VERSION 5.8 ;
BUSBITCHARS "[]" ;
DIVIDERCHAR "/" ;
UNITS
    DATABASE MICRONS 1000 ;
END UNITS

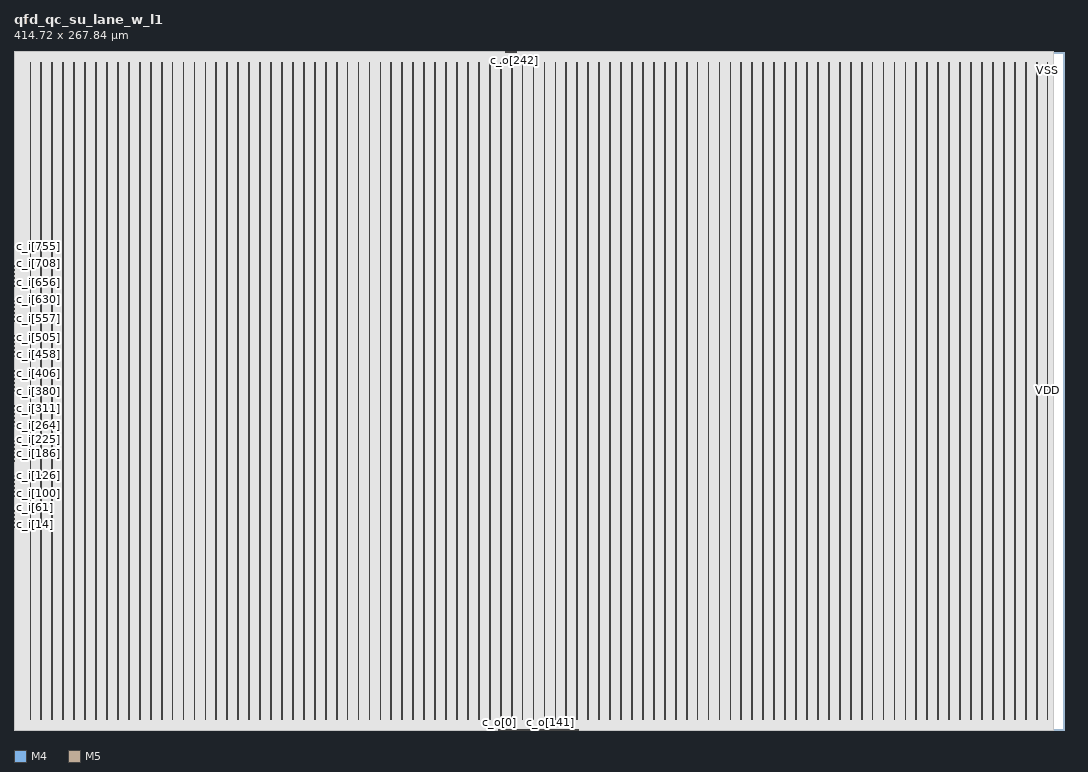
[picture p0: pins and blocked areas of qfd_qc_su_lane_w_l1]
MACRO qfd_qc_su_lane_w_l1
  FOREIGN qfd_qc_su_lane_w_l1 0 0 ;
  CLASS BLOCK ;
  SIZE 414.72 BY 267.84 ;
  PIN c_i[0]
    DIRECTION INPUT ;
    USE SIGNAL ;
    PORT
      LAYER M4 ;
        RECT  0 79.152 0.084 79.176 ;
    END
  END c_i[0]
  PIN c_i[100]
    DIRECTION INPUT ;
    USE SIGNAL ;
    PORT
      LAYER M4 ;
        RECT  0 93.552 0.084 93.576 ;
    END
  END c_i[100]
  PIN c_i[101]
    DIRECTION INPUT ;
    USE SIGNAL ;
    PORT
      LAYER M4 ;
        RECT  0 93.696 0.084 93.72 ;
    END
  END c_i[101]
  PIN c_i[102]
    DIRECTION INPUT ;
    USE SIGNAL ;
    PORT
      LAYER M4 ;
        RECT  0 93.84 0.084 93.864 ;
    END
  END c_i[102]
  PIN c_i[103]
    DIRECTION INPUT ;
    USE SIGNAL ;
    PORT
      LAYER M4 ;
        RECT  0 93.984 0.084 94.008 ;
    END
  END c_i[103]
  PIN c_i[104]
    DIRECTION INPUT ;
    USE SIGNAL ;
    PORT
      LAYER M4 ;
        RECT  0 94.128 0.084 94.152 ;
    END
  END c_i[104]
  PIN c_i[105]
    DIRECTION INPUT ;
    USE SIGNAL ;
    PORT
      LAYER M4 ;
        RECT  0 94.272 0.084 94.296 ;
    END
  END c_i[105]
  PIN c_i[106]
    DIRECTION INPUT ;
    USE SIGNAL ;
    PORT
      LAYER M4 ;
        RECT  0 94.416 0.084 94.44 ;
    END
  END c_i[106]
  PIN c_i[107]
    DIRECTION INPUT ;
    USE SIGNAL ;
    PORT
      LAYER M4 ;
        RECT  0 94.56 0.084 94.584 ;
    END
  END c_i[107]
  PIN c_i[108]
    DIRECTION INPUT ;
    USE SIGNAL ;
    PORT
      LAYER M4 ;
        RECT  0 94.704 0.084 94.728 ;
    END
  END c_i[108]
  PIN c_i[109]
    DIRECTION INPUT ;
    USE SIGNAL ;
    PORT
      LAYER M4 ;
        RECT  0 94.848 0.084 94.872 ;
    END
  END c_i[109]
  PIN c_i[10]
    DIRECTION INPUT ;
    USE SIGNAL ;
    PORT
      LAYER M4 ;
        RECT  0 80.592 0.084 80.616 ;
    END
  END c_i[10]
  PIN c_i[110]
    DIRECTION INPUT ;
    USE SIGNAL ;
    PORT
      LAYER M4 ;
        RECT  0 94.992 0.084 95.016 ;
    END
  END c_i[110]
  PIN c_i[111]
    DIRECTION INPUT ;
    USE SIGNAL ;
    PORT
      LAYER M4 ;
        RECT  0 95.136 0.084 95.16 ;
    END
  END c_i[111]
  PIN c_i[112]
    DIRECTION INPUT ;
    USE SIGNAL ;
    PORT
      LAYER M4 ;
        RECT  0 95.28 0.084 95.304 ;
    END
  END c_i[112]
  PIN c_i[113]
    DIRECTION INPUT ;
    USE SIGNAL ;
    PORT
      LAYER M4 ;
        RECT  0 95.424 0.084 95.448 ;
    END
  END c_i[113]
  PIN c_i[114]
    DIRECTION INPUT ;
    USE SIGNAL ;
    PORT
      LAYER M4 ;
        RECT  0 95.568 0.084 95.592 ;
    END
  END c_i[114]
  PIN c_i[115]
    DIRECTION INPUT ;
    USE SIGNAL ;
    PORT
      LAYER M4 ;
        RECT  0 95.712 0.084 95.736 ;
    END
  END c_i[115]
  PIN c_i[116]
    DIRECTION INPUT ;
    USE SIGNAL ;
    PORT
      LAYER M4 ;
        RECT  0 95.856 0.084 95.88 ;
    END
  END c_i[116]
  PIN c_i[117]
    DIRECTION INPUT ;
    USE SIGNAL ;
    PORT
      LAYER M4 ;
        RECT  0 96 0.084 96.024 ;
    END
  END c_i[117]
  PIN c_i[118]
    DIRECTION INPUT ;
    USE SIGNAL ;
    PORT
      LAYER M4 ;
        RECT  0 96.144 0.084 96.168 ;
    END
  END c_i[118]
  PIN c_i[119]
    DIRECTION INPUT ;
    USE SIGNAL ;
    PORT
      LAYER M4 ;
        RECT  0 96.288 0.084 96.312 ;
    END
  END c_i[119]
  PIN c_i[11]
    DIRECTION INPUT ;
    USE SIGNAL ;
    PORT
      LAYER M4 ;
        RECT  0 80.736 0.084 80.76 ;
    END
  END c_i[11]
  PIN c_i[120]
    DIRECTION INPUT ;
    USE SIGNAL ;
    PORT
      LAYER M4 ;
        RECT  0 96.432 0.084 96.456 ;
    END
  END c_i[120]
  PIN c_i[121]
    DIRECTION INPUT ;
    USE SIGNAL ;
    PORT
      LAYER M4 ;
        RECT  0 96.576 0.084 96.6 ;
    END
  END c_i[121]
  PIN c_i[122]
    DIRECTION INPUT ;
    USE SIGNAL ;
    PORT
      LAYER M4 ;
        RECT  0 96.72 0.084 96.744 ;
    END
  END c_i[122]
  PIN c_i[123]
    DIRECTION INPUT ;
    USE SIGNAL ;
    PORT
      LAYER M4 ;
        RECT  0 96.864 0.084 96.888 ;
    END
  END c_i[123]
  PIN c_i[124]
    DIRECTION INPUT ;
    USE SIGNAL ;
    PORT
      LAYER M4 ;
        RECT  0 97.008 0.084 97.032 ;
    END
  END c_i[124]
  PIN c_i[125]
    DIRECTION INPUT ;
    USE SIGNAL ;
    PORT
      LAYER M4 ;
        RECT  0 97.152 0.084 97.176 ;
    END
  END c_i[125]
  PIN c_i[126]
    DIRECTION INPUT ;
    USE SIGNAL ;
    PORT
      LAYER M4 ;
        RECT  0 97.296 0.084 97.32 ;
    END
  END c_i[126]
  PIN c_i[127]
    DIRECTION INPUT ;
    USE SIGNAL ;
    PORT
      LAYER M4 ;
        RECT  0 97.44 0.084 97.464 ;
    END
  END c_i[127]
  PIN c_i[128]
    DIRECTION INPUT ;
    USE SIGNAL ;
    PORT
      LAYER M4 ;
        RECT  0 97.584 0.084 97.608 ;
    END
  END c_i[128]
  PIN c_i[129]
    DIRECTION INPUT ;
    USE SIGNAL ;
    PORT
      LAYER M4 ;
        RECT  0 97.728 0.084 97.752 ;
    END
  END c_i[129]
  PIN c_i[12]
    DIRECTION INPUT ;
    USE SIGNAL ;
    PORT
      LAYER M4 ;
        RECT  0 80.88 0.084 80.904 ;
    END
  END c_i[12]
  PIN c_i[130]
    DIRECTION INPUT ;
    USE SIGNAL ;
    PORT
      LAYER M4 ;
        RECT  0 97.872 0.084 97.896 ;
    END
  END c_i[130]
  PIN c_i[131]
    DIRECTION INPUT ;
    USE SIGNAL ;
    PORT
      LAYER M4 ;
        RECT  0 98.016 0.084 98.04 ;
    END
  END c_i[131]
  PIN c_i[132]
    DIRECTION INPUT ;
    USE SIGNAL ;
    PORT
      LAYER M4 ;
        RECT  0 98.16 0.084 98.184 ;
    END
  END c_i[132]
  PIN c_i[133]
    DIRECTION INPUT ;
    USE SIGNAL ;
    PORT
      LAYER M4 ;
        RECT  0 98.304 0.084 98.328 ;
    END
  END c_i[133]
  PIN c_i[134]
    DIRECTION INPUT ;
    USE SIGNAL ;
    PORT
      LAYER M4 ;
        RECT  0 98.448 0.084 98.472 ;
    END
  END c_i[134]
  PIN c_i[135]
    DIRECTION INPUT ;
    USE SIGNAL ;
    PORT
      LAYER M4 ;
        RECT  0 98.592 0.084 98.616 ;
    END
  END c_i[135]
  PIN c_i[136]
    DIRECTION INPUT ;
    USE SIGNAL ;
    PORT
      LAYER M4 ;
        RECT  0 98.736 0.084 98.76 ;
    END
  END c_i[136]
  PIN c_i[137]
    DIRECTION INPUT ;
    USE SIGNAL ;
    PORT
      LAYER M4 ;
        RECT  0 98.88 0.084 98.904 ;
    END
  END c_i[137]
  PIN c_i[138]
    DIRECTION INPUT ;
    USE SIGNAL ;
    PORT
      LAYER M4 ;
        RECT  0 99.024 0.084 99.048 ;
    END
  END c_i[138]
  PIN c_i[139]
    DIRECTION INPUT ;
    USE SIGNAL ;
    PORT
      LAYER M4 ;
        RECT  0 99.168 0.084 99.192 ;
    END
  END c_i[139]
  PIN c_i[13]
    DIRECTION INPUT ;
    USE SIGNAL ;
    PORT
      LAYER M4 ;
        RECT  0 81.024 0.084 81.048 ;
    END
  END c_i[13]
  PIN c_i[140]
    DIRECTION INPUT ;
    USE SIGNAL ;
    PORT
      LAYER M4 ;
        RECT  0 99.312 0.084 99.336 ;
    END
  END c_i[140]
  PIN c_i[141]
    DIRECTION INPUT ;
    USE SIGNAL ;
    PORT
      LAYER M4 ;
        RECT  0 99.456 0.084 99.48 ;
    END
  END c_i[141]
  PIN c_i[142]
    DIRECTION INPUT ;
    USE SIGNAL ;
    PORT
      LAYER M4 ;
        RECT  0 99.6 0.084 99.624 ;
    END
  END c_i[142]
  PIN c_i[143]
    DIRECTION INPUT ;
    USE SIGNAL ;
    PORT
      LAYER M4 ;
        RECT  0 99.744 0.084 99.768 ;
    END
  END c_i[143]
  PIN c_i[144]
    DIRECTION INPUT ;
    USE SIGNAL ;
    PORT
      LAYER M4 ;
        RECT  0 99.888 0.084 99.912 ;
    END
  END c_i[144]
  PIN c_i[145]
    DIRECTION INPUT ;
    USE SIGNAL ;
    PORT
      LAYER M4 ;
        RECT  0 100.032 0.084 100.056 ;
    END
  END c_i[145]
  PIN c_i[146]
    DIRECTION INPUT ;
    USE SIGNAL ;
    PORT
      LAYER M4 ;
        RECT  0 100.176 0.084 100.2 ;
    END
  END c_i[146]
  PIN c_i[147]
    DIRECTION INPUT ;
    USE SIGNAL ;
    PORT
      LAYER M4 ;
        RECT  0 100.32 0.084 100.344 ;
    END
  END c_i[147]
  PIN c_i[148]
    DIRECTION INPUT ;
    USE SIGNAL ;
    PORT
      LAYER M4 ;
        RECT  0 100.464 0.084 100.488 ;
    END
  END c_i[148]
  PIN c_i[149]
    DIRECTION INPUT ;
    USE SIGNAL ;
    PORT
      LAYER M4 ;
        RECT  0 100.608 0.084 100.632 ;
    END
  END c_i[149]
  PIN c_i[14]
    DIRECTION INPUT ;
    USE SIGNAL ;
    PORT
      LAYER M4 ;
        RECT  0 81.168 0.084 81.192 ;
    END
  END c_i[14]
  PIN c_i[150]
    DIRECTION INPUT ;
    USE SIGNAL ;
    PORT
      LAYER M4 ;
        RECT  0 100.752 0.084 100.776 ;
    END
  END c_i[150]
  PIN c_i[151]
    DIRECTION INPUT ;
    USE SIGNAL ;
    PORT
      LAYER M4 ;
        RECT  0 100.896 0.084 100.92 ;
    END
  END c_i[151]
  PIN c_i[152]
    DIRECTION INPUT ;
    USE SIGNAL ;
    PORT
      LAYER M4 ;
        RECT  0 101.04 0.084 101.064 ;
    END
  END c_i[152]
  PIN c_i[153]
    DIRECTION INPUT ;
    USE SIGNAL ;
    PORT
      LAYER M4 ;
        RECT  0 101.184 0.084 101.208 ;
    END
  END c_i[153]
  PIN c_i[154]
    DIRECTION INPUT ;
    USE SIGNAL ;
    PORT
      LAYER M4 ;
        RECT  0 101.328 0.084 101.352 ;
    END
  END c_i[154]
  PIN c_i[155]
    DIRECTION INPUT ;
    USE SIGNAL ;
    PORT
      LAYER M4 ;
        RECT  0 101.472 0.084 101.496 ;
    END
  END c_i[155]
  PIN c_i[156]
    DIRECTION INPUT ;
    USE SIGNAL ;
    PORT
      LAYER M4 ;
        RECT  0 101.616 0.084 101.64 ;
    END
  END c_i[156]
  PIN c_i[157]
    DIRECTION INPUT ;
    USE SIGNAL ;
    PORT
      LAYER M4 ;
        RECT  0 101.76 0.084 101.784 ;
    END
  END c_i[157]
  PIN c_i[158]
    DIRECTION INPUT ;
    USE SIGNAL ;
    PORT
      LAYER M4 ;
        RECT  0 101.904 0.084 101.928 ;
    END
  END c_i[158]
  PIN c_i[159]
    DIRECTION INPUT ;
    USE SIGNAL ;
    PORT
      LAYER M4 ;
        RECT  0 102.048 0.084 102.072 ;
    END
  END c_i[159]
  PIN c_i[15]
    DIRECTION INPUT ;
    USE SIGNAL ;
    PORT
      LAYER M4 ;
        RECT  0 81.312 0.084 81.336 ;
    END
  END c_i[15]
  PIN c_i[160]
    DIRECTION INPUT ;
    USE SIGNAL ;
    PORT
      LAYER M4 ;
        RECT  0 102.192 0.084 102.216 ;
    END
  END c_i[160]
  PIN c_i[161]
    DIRECTION INPUT ;
    USE SIGNAL ;
    PORT
      LAYER M4 ;
        RECT  0 102.336 0.084 102.36 ;
    END
  END c_i[161]
  PIN c_i[162]
    DIRECTION INPUT ;
    USE SIGNAL ;
    PORT
      LAYER M4 ;
        RECT  0 102.48 0.084 102.504 ;
    END
  END c_i[162]
  PIN c_i[163]
    DIRECTION INPUT ;
    USE SIGNAL ;
    PORT
      LAYER M4 ;
        RECT  0 102.624 0.084 102.648 ;
    END
  END c_i[163]
  PIN c_i[164]
    DIRECTION INPUT ;
    USE SIGNAL ;
    PORT
      LAYER M4 ;
        RECT  0 102.768 0.084 102.792 ;
    END
  END c_i[164]
  PIN c_i[165]
    DIRECTION INPUT ;
    USE SIGNAL ;
    PORT
      LAYER M4 ;
        RECT  0 102.912 0.084 102.936 ;
    END
  END c_i[165]
  PIN c_i[166]
    DIRECTION INPUT ;
    USE SIGNAL ;
    PORT
      LAYER M4 ;
        RECT  0 103.056 0.084 103.08 ;
    END
  END c_i[166]
  PIN c_i[167]
    DIRECTION INPUT ;
    USE SIGNAL ;
    PORT
      LAYER M4 ;
        RECT  0 103.2 0.084 103.224 ;
    END
  END c_i[167]
  PIN c_i[168]
    DIRECTION INPUT ;
    USE SIGNAL ;
    PORT
      LAYER M4 ;
        RECT  0 103.344 0.084 103.368 ;
    END
  END c_i[168]
  PIN c_i[169]
    DIRECTION INPUT ;
    USE SIGNAL ;
    PORT
      LAYER M4 ;
        RECT  0 103.488 0.084 103.512 ;
    END
  END c_i[169]
  PIN c_i[16]
    DIRECTION INPUT ;
    USE SIGNAL ;
    PORT
      LAYER M4 ;
        RECT  0 81.456 0.084 81.48 ;
    END
  END c_i[16]
  PIN c_i[170]
    DIRECTION INPUT ;
    USE SIGNAL ;
    PORT
      LAYER M4 ;
        RECT  0 103.632 0.084 103.656 ;
    END
  END c_i[170]
  PIN c_i[171]
    DIRECTION INPUT ;
    USE SIGNAL ;
    PORT
      LAYER M4 ;
        RECT  0 103.776 0.084 103.8 ;
    END
  END c_i[171]
  PIN c_i[172]
    DIRECTION INPUT ;
    USE SIGNAL ;
    PORT
      LAYER M4 ;
        RECT  0 103.92 0.084 103.944 ;
    END
  END c_i[172]
  PIN c_i[173]
    DIRECTION INPUT ;
    USE SIGNAL ;
    PORT
      LAYER M4 ;
        RECT  0 104.064 0.084 104.088 ;
    END
  END c_i[173]
  PIN c_i[174]
    DIRECTION INPUT ;
    USE SIGNAL ;
    PORT
      LAYER M4 ;
        RECT  0 104.208 0.084 104.232 ;
    END
  END c_i[174]
  PIN c_i[175]
    DIRECTION INPUT ;
    USE SIGNAL ;
    PORT
      LAYER M4 ;
        RECT  0 104.352 0.084 104.376 ;
    END
  END c_i[175]
  PIN c_i[176]
    DIRECTION INPUT ;
    USE SIGNAL ;
    PORT
      LAYER M4 ;
        RECT  0 104.496 0.084 104.52 ;
    END
  END c_i[176]
  PIN c_i[177]
    DIRECTION INPUT ;
    USE SIGNAL ;
    PORT
      LAYER M4 ;
        RECT  0 104.64 0.084 104.664 ;
    END
  END c_i[177]
  PIN c_i[178]
    DIRECTION INPUT ;
    USE SIGNAL ;
    PORT
      LAYER M4 ;
        RECT  0 104.784 0.084 104.808 ;
    END
  END c_i[178]
  PIN c_i[179]
    DIRECTION INPUT ;
    USE SIGNAL ;
    PORT
      LAYER M4 ;
        RECT  0 104.928 0.084 104.952 ;
    END
  END c_i[179]
  PIN c_i[17]
    DIRECTION INPUT ;
    USE SIGNAL ;
    PORT
      LAYER M4 ;
        RECT  0 81.6 0.084 81.624 ;
    END
  END c_i[17]
  PIN c_i[180]
    DIRECTION INPUT ;
    USE SIGNAL ;
    PORT
      LAYER M4 ;
        RECT  0 105.072 0.084 105.096 ;
    END
  END c_i[180]
  PIN c_i[181]
    DIRECTION INPUT ;
    USE SIGNAL ;
    PORT
      LAYER M4 ;
        RECT  0 105.216 0.084 105.24 ;
    END
  END c_i[181]
  PIN c_i[182]
    DIRECTION INPUT ;
    USE SIGNAL ;
    PORT
      LAYER M4 ;
        RECT  0 105.36 0.084 105.384 ;
    END
  END c_i[182]
  PIN c_i[183]
    DIRECTION INPUT ;
    USE SIGNAL ;
    PORT
      LAYER M4 ;
        RECT  0 105.504 0.084 105.528 ;
    END
  END c_i[183]
  PIN c_i[184]
    DIRECTION INPUT ;
    USE SIGNAL ;
    PORT
      LAYER M4 ;
        RECT  0 105.648 0.084 105.672 ;
    END
  END c_i[184]
  PIN c_i[185]
    DIRECTION INPUT ;
    USE SIGNAL ;
    PORT
      LAYER M4 ;
        RECT  0 105.792 0.084 105.816 ;
    END
  END c_i[185]
  PIN c_i[186]
    DIRECTION INPUT ;
    USE SIGNAL ;
    PORT
      LAYER M4 ;
        RECT  0 105.936 0.084 105.96 ;
    END
  END c_i[186]
  PIN c_i[187]
    DIRECTION INPUT ;
    USE SIGNAL ;
    PORT
      LAYER M4 ;
        RECT  0 106.08 0.084 106.104 ;
    END
  END c_i[187]
  PIN c_i[188]
    DIRECTION INPUT ;
    USE SIGNAL ;
    PORT
      LAYER M4 ;
        RECT  0 106.224 0.084 106.248 ;
    END
  END c_i[188]
  PIN c_i[189]
    DIRECTION INPUT ;
    USE SIGNAL ;
    PORT
      LAYER M4 ;
        RECT  0 106.368 0.084 106.392 ;
    END
  END c_i[189]
  PIN c_i[18]
    DIRECTION INPUT ;
    USE SIGNAL ;
    PORT
      LAYER M4 ;
        RECT  0 81.744 0.084 81.768 ;
    END
  END c_i[18]
  PIN c_i[190]
    DIRECTION INPUT ;
    USE SIGNAL ;
    PORT
      LAYER M4 ;
        RECT  0 106.512 0.084 106.536 ;
    END
  END c_i[190]
  PIN c_i[191]
    DIRECTION INPUT ;
    USE SIGNAL ;
    PORT
      LAYER M4 ;
        RECT  0 106.656 0.084 106.68 ;
    END
  END c_i[191]
  PIN c_i[192]
    DIRECTION INPUT ;
    USE SIGNAL ;
    PORT
      LAYER M4 ;
        RECT  0 106.8 0.084 106.824 ;
    END
  END c_i[192]
  PIN c_i[193]
    DIRECTION INPUT ;
    USE SIGNAL ;
    PORT
      LAYER M4 ;
        RECT  0 106.944 0.084 106.968 ;
    END
  END c_i[193]
  PIN c_i[194]
    DIRECTION INPUT ;
    USE SIGNAL ;
    PORT
      LAYER M4 ;
        RECT  0 107.088 0.084 107.112 ;
    END
  END c_i[194]
  PIN c_i[195]
    DIRECTION INPUT ;
    USE SIGNAL ;
    PORT
      LAYER M4 ;
        RECT  0 107.232 0.084 107.256 ;
    END
  END c_i[195]
  PIN c_i[196]
    DIRECTION INPUT ;
    USE SIGNAL ;
    PORT
      LAYER M4 ;
        RECT  0 107.376 0.084 107.4 ;
    END
  END c_i[196]
  PIN c_i[197]
    DIRECTION INPUT ;
    USE SIGNAL ;
    PORT
      LAYER M4 ;
        RECT  0 107.52 0.084 107.544 ;
    END
  END c_i[197]
  PIN c_i[198]
    DIRECTION INPUT ;
    USE SIGNAL ;
    PORT
      LAYER M4 ;
        RECT  0 107.664 0.084 107.688 ;
    END
  END c_i[198]
  PIN c_i[199]
    DIRECTION INPUT ;
    USE SIGNAL ;
    PORT
      LAYER M4 ;
        RECT  0 107.808 0.084 107.832 ;
    END
  END c_i[199]
  PIN c_i[19]
    DIRECTION INPUT ;
    USE SIGNAL ;
    PORT
      LAYER M4 ;
        RECT  0 81.888 0.084 81.912 ;
    END
  END c_i[19]
  PIN c_i[1]
    DIRECTION INPUT ;
    USE SIGNAL ;
    PORT
      LAYER M4 ;
        RECT  0 79.296 0.084 79.32 ;
    END
  END c_i[1]
  PIN c_i[200]
    DIRECTION INPUT ;
    USE SIGNAL ;
    PORT
      LAYER M4 ;
        RECT  0 107.952 0.084 107.976 ;
    END
  END c_i[200]
  PIN c_i[201]
    DIRECTION INPUT ;
    USE SIGNAL ;
    PORT
      LAYER M4 ;
        RECT  0 108.096 0.084 108.12 ;
    END
  END c_i[201]
  PIN c_i[202]
    DIRECTION INPUT ;
    USE SIGNAL ;
    PORT
      LAYER M4 ;
        RECT  0 108.24 0.084 108.264 ;
    END
  END c_i[202]
  PIN c_i[203]
    DIRECTION INPUT ;
    USE SIGNAL ;
    PORT
      LAYER M4 ;
        RECT  0 108.384 0.084 108.408 ;
    END
  END c_i[203]
  PIN c_i[204]
    DIRECTION INPUT ;
    USE SIGNAL ;
    PORT
      LAYER M4 ;
        RECT  0 108.528 0.084 108.552 ;
    END
  END c_i[204]
  PIN c_i[205]
    DIRECTION INPUT ;
    USE SIGNAL ;
    PORT
      LAYER M4 ;
        RECT  0 108.672 0.084 108.696 ;
    END
  END c_i[205]
  PIN c_i[206]
    DIRECTION INPUT ;
    USE SIGNAL ;
    PORT
      LAYER M4 ;
        RECT  0 108.816 0.084 108.84 ;
    END
  END c_i[206]
  PIN c_i[207]
    DIRECTION INPUT ;
    USE SIGNAL ;
    PORT
      LAYER M4 ;
        RECT  0 108.96 0.084 108.984 ;
    END
  END c_i[207]
  PIN c_i[208]
    DIRECTION INPUT ;
    USE SIGNAL ;
    PORT
      LAYER M4 ;
        RECT  0 109.104 0.084 109.128 ;
    END
  END c_i[208]
  PIN c_i[209]
    DIRECTION INPUT ;
    USE SIGNAL ;
    PORT
      LAYER M4 ;
        RECT  0 109.248 0.084 109.272 ;
    END
  END c_i[209]
  PIN c_i[20]
    DIRECTION INPUT ;
    USE SIGNAL ;
    PORT
      LAYER M4 ;
        RECT  0 82.032 0.084 82.056 ;
    END
  END c_i[20]
  PIN c_i[210]
    DIRECTION INPUT ;
    USE SIGNAL ;
    PORT
      LAYER M4 ;
        RECT  0 109.392 0.084 109.416 ;
    END
  END c_i[210]
  PIN c_i[211]
    DIRECTION INPUT ;
    USE SIGNAL ;
    PORT
      LAYER M4 ;
        RECT  0 109.536 0.084 109.56 ;
    END
  END c_i[211]
  PIN c_i[212]
    DIRECTION INPUT ;
    USE SIGNAL ;
    PORT
      LAYER M4 ;
        RECT  0 109.68 0.084 109.704 ;
    END
  END c_i[212]
  PIN c_i[213]
    DIRECTION INPUT ;
    USE SIGNAL ;
    PORT
      LAYER M4 ;
        RECT  0 109.824 0.084 109.848 ;
    END
  END c_i[213]
  PIN c_i[214]
    DIRECTION INPUT ;
    USE SIGNAL ;
    PORT
      LAYER M4 ;
        RECT  0 109.968 0.084 109.992 ;
    END
  END c_i[214]
  PIN c_i[215]
    DIRECTION INPUT ;
    USE SIGNAL ;
    PORT
      LAYER M4 ;
        RECT  0 110.112 0.084 110.136 ;
    END
  END c_i[215]
  PIN c_i[216]
    DIRECTION INPUT ;
    USE SIGNAL ;
    PORT
      LAYER M4 ;
        RECT  0 110.256 0.084 110.28 ;
    END
  END c_i[216]
  PIN c_i[217]
    DIRECTION INPUT ;
    USE SIGNAL ;
    PORT
      LAYER M4 ;
        RECT  0 110.4 0.084 110.424 ;
    END
  END c_i[217]
  PIN c_i[218]
    DIRECTION INPUT ;
    USE SIGNAL ;
    PORT
      LAYER M4 ;
        RECT  0 110.544 0.084 110.568 ;
    END
  END c_i[218]
  PIN c_i[219]
    DIRECTION INPUT ;
    USE SIGNAL ;
    PORT
      LAYER M4 ;
        RECT  0 110.688 0.084 110.712 ;
    END
  END c_i[219]
  PIN c_i[21]
    DIRECTION INPUT ;
    USE SIGNAL ;
    PORT
      LAYER M4 ;
        RECT  0 82.176 0.084 82.2 ;
    END
  END c_i[21]
  PIN c_i[220]
    DIRECTION INPUT ;
    USE SIGNAL ;
    PORT
      LAYER M4 ;
        RECT  0 110.832 0.084 110.856 ;
    END
  END c_i[220]
  PIN c_i[221]
    DIRECTION INPUT ;
    USE SIGNAL ;
    PORT
      LAYER M4 ;
        RECT  0 110.976 0.084 111 ;
    END
  END c_i[221]
  PIN c_i[222]
    DIRECTION INPUT ;
    USE SIGNAL ;
    PORT
      LAYER M4 ;
        RECT  0 111.12 0.084 111.144 ;
    END
  END c_i[222]
  PIN c_i[223]
    DIRECTION INPUT ;
    USE SIGNAL ;
    PORT
      LAYER M4 ;
        RECT  0 111.264 0.084 111.288 ;
    END
  END c_i[223]
  PIN c_i[224]
    DIRECTION INPUT ;
    USE SIGNAL ;
    PORT
      LAYER M4 ;
        RECT  0 111.408 0.084 111.432 ;
    END
  END c_i[224]
  PIN c_i[225]
    DIRECTION INPUT ;
    USE SIGNAL ;
    PORT
      LAYER M4 ;
        RECT  0 111.552 0.084 111.576 ;
    END
  END c_i[225]
  PIN c_i[226]
    DIRECTION INPUT ;
    USE SIGNAL ;
    PORT
      LAYER M4 ;
        RECT  0 111.696 0.084 111.72 ;
    END
  END c_i[226]
  PIN c_i[227]
    DIRECTION INPUT ;
    USE SIGNAL ;
    PORT
      LAYER M4 ;
        RECT  0 111.84 0.084 111.864 ;
    END
  END c_i[227]
  PIN c_i[228]
    DIRECTION INPUT ;
    USE SIGNAL ;
    PORT
      LAYER M4 ;
        RECT  0 111.984 0.084 112.008 ;
    END
  END c_i[228]
  PIN c_i[229]
    DIRECTION INPUT ;
    USE SIGNAL ;
    PORT
      LAYER M4 ;
        RECT  0 112.128 0.084 112.152 ;
    END
  END c_i[229]
  PIN c_i[22]
    DIRECTION INPUT ;
    USE SIGNAL ;
    PORT
      LAYER M4 ;
        RECT  0 82.32 0.084 82.344 ;
    END
  END c_i[22]
  PIN c_i[230]
    DIRECTION INPUT ;
    USE SIGNAL ;
    PORT
      LAYER M4 ;
        RECT  0 112.272 0.084 112.296 ;
    END
  END c_i[230]
  PIN c_i[231]
    DIRECTION INPUT ;
    USE SIGNAL ;
    PORT
      LAYER M4 ;
        RECT  0 112.416 0.084 112.44 ;
    END
  END c_i[231]
  PIN c_i[232]
    DIRECTION INPUT ;
    USE SIGNAL ;
    PORT
      LAYER M4 ;
        RECT  0 112.56 0.084 112.584 ;
    END
  END c_i[232]
  PIN c_i[233]
    DIRECTION INPUT ;
    USE SIGNAL ;
    PORT
      LAYER M4 ;
        RECT  0 112.704 0.084 112.728 ;
    END
  END c_i[233]
  PIN c_i[234]
    DIRECTION INPUT ;
    USE SIGNAL ;
    PORT
      LAYER M4 ;
        RECT  0 112.848 0.084 112.872 ;
    END
  END c_i[234]
  PIN c_i[235]
    DIRECTION INPUT ;
    USE SIGNAL ;
    PORT
      LAYER M4 ;
        RECT  0 112.992 0.084 113.016 ;
    END
  END c_i[235]
  PIN c_i[236]
    DIRECTION INPUT ;
    USE SIGNAL ;
    PORT
      LAYER M4 ;
        RECT  0 113.136 0.084 113.16 ;
    END
  END c_i[236]
  PIN c_i[237]
    DIRECTION INPUT ;
    USE SIGNAL ;
    PORT
      LAYER M4 ;
        RECT  0 113.28 0.084 113.304 ;
    END
  END c_i[237]
  PIN c_i[238]
    DIRECTION INPUT ;
    USE SIGNAL ;
    PORT
      LAYER M4 ;
        RECT  0 113.424 0.084 113.448 ;
    END
  END c_i[238]
  PIN c_i[239]
    DIRECTION INPUT ;
    USE SIGNAL ;
    PORT
      LAYER M4 ;
        RECT  0 113.568 0.084 113.592 ;
    END
  END c_i[239]
  PIN c_i[23]
    DIRECTION INPUT ;
    USE SIGNAL ;
    PORT
      LAYER M4 ;
        RECT  0 82.464 0.084 82.488 ;
    END
  END c_i[23]
  PIN c_i[240]
    DIRECTION INPUT ;
    USE SIGNAL ;
    PORT
      LAYER M4 ;
        RECT  0 113.712 0.084 113.736 ;
    END
  END c_i[240]
  PIN c_i[241]
    DIRECTION INPUT ;
    USE SIGNAL ;
    PORT
      LAYER M4 ;
        RECT  0 113.856 0.084 113.88 ;
    END
  END c_i[241]
  PIN c_i[242]
    DIRECTION INPUT ;
    USE SIGNAL ;
    PORT
      LAYER M4 ;
        RECT  0 114 0.084 114.024 ;
    END
  END c_i[242]
  PIN c_i[243]
    DIRECTION INPUT ;
    USE SIGNAL ;
    PORT
      LAYER M4 ;
        RECT  0 114.144 0.084 114.168 ;
    END
  END c_i[243]
  PIN c_i[244]
    DIRECTION INPUT ;
    USE SIGNAL ;
    PORT
      LAYER M4 ;
        RECT  0 114.288 0.084 114.312 ;
    END
  END c_i[244]
  PIN c_i[245]
    DIRECTION INPUT ;
    USE SIGNAL ;
    PORT
      LAYER M4 ;
        RECT  0 114.432 0.084 114.456 ;
    END
  END c_i[245]
  PIN c_i[246]
    DIRECTION INPUT ;
    USE SIGNAL ;
    PORT
      LAYER M4 ;
        RECT  0 114.576 0.084 114.6 ;
    END
  END c_i[246]
  PIN c_i[247]
    DIRECTION INPUT ;
    USE SIGNAL ;
    PORT
      LAYER M4 ;
        RECT  0 114.72 0.084 114.744 ;
    END
  END c_i[247]
  PIN c_i[248]
    DIRECTION INPUT ;
    USE SIGNAL ;
    PORT
      LAYER M4 ;
        RECT  0 114.864 0.084 114.888 ;
    END
  END c_i[248]
  PIN c_i[249]
    DIRECTION INPUT ;
    USE SIGNAL ;
    PORT
      LAYER M4 ;
        RECT  0 115.008 0.084 115.032 ;
    END
  END c_i[249]
  PIN c_i[24]
    DIRECTION INPUT ;
    USE SIGNAL ;
    PORT
      LAYER M4 ;
        RECT  0 82.608 0.084 82.632 ;
    END
  END c_i[24]
  PIN c_i[250]
    DIRECTION INPUT ;
    USE SIGNAL ;
    PORT
      LAYER M4 ;
        RECT  0 115.152 0.084 115.176 ;
    END
  END c_i[250]
  PIN c_i[251]
    DIRECTION INPUT ;
    USE SIGNAL ;
    PORT
      LAYER M4 ;
        RECT  0 115.296 0.084 115.32 ;
    END
  END c_i[251]
  PIN c_i[252]
    DIRECTION INPUT ;
    USE SIGNAL ;
    PORT
      LAYER M4 ;
        RECT  0 115.44 0.084 115.464 ;
    END
  END c_i[252]
  PIN c_i[253]
    DIRECTION INPUT ;
    USE SIGNAL ;
    PORT
      LAYER M4 ;
        RECT  0 115.584 0.084 115.608 ;
    END
  END c_i[253]
  PIN c_i[254]
    DIRECTION INPUT ;
    USE SIGNAL ;
    PORT
      LAYER M4 ;
        RECT  0 115.728 0.084 115.752 ;
    END
  END c_i[254]
  PIN c_i[255]
    DIRECTION INPUT ;
    USE SIGNAL ;
    PORT
      LAYER M4 ;
        RECT  0 115.872 0.084 115.896 ;
    END
  END c_i[255]
  PIN c_i[256]
    DIRECTION INPUT ;
    USE SIGNAL ;
    PORT
      LAYER M4 ;
        RECT  0 116.016 0.084 116.04 ;
    END
  END c_i[256]
  PIN c_i[257]
    DIRECTION INPUT ;
    USE SIGNAL ;
    PORT
      LAYER M4 ;
        RECT  0 116.16 0.084 116.184 ;
    END
  END c_i[257]
  PIN c_i[258]
    DIRECTION INPUT ;
    USE SIGNAL ;
    PORT
      LAYER M4 ;
        RECT  0 116.304 0.084 116.328 ;
    END
  END c_i[258]
  PIN c_i[259]
    DIRECTION INPUT ;
    USE SIGNAL ;
    PORT
      LAYER M4 ;
        RECT  0 116.448 0.084 116.472 ;
    END
  END c_i[259]
  PIN c_i[25]
    DIRECTION INPUT ;
    USE SIGNAL ;
    PORT
      LAYER M4 ;
        RECT  0 82.752 0.084 82.776 ;
    END
  END c_i[25]
  PIN c_i[260]
    DIRECTION INPUT ;
    USE SIGNAL ;
    PORT
      LAYER M4 ;
        RECT  0 116.592 0.084 116.616 ;
    END
  END c_i[260]
  PIN c_i[261]
    DIRECTION INPUT ;
    USE SIGNAL ;
    PORT
      LAYER M4 ;
        RECT  0 116.736 0.084 116.76 ;
    END
  END c_i[261]
  PIN c_i[262]
    DIRECTION INPUT ;
    USE SIGNAL ;
    PORT
      LAYER M4 ;
        RECT  0 116.88 0.084 116.904 ;
    END
  END c_i[262]
  PIN c_i[263]
    DIRECTION INPUT ;
    USE SIGNAL ;
    PORT
      LAYER M4 ;
        RECT  0 117.024 0.084 117.048 ;
    END
  END c_i[263]
  PIN c_i[264]
    DIRECTION INPUT ;
    USE SIGNAL ;
    PORT
      LAYER M4 ;
        RECT  0 117.168 0.084 117.192 ;
    END
  END c_i[264]
  PIN c_i[265]
    DIRECTION INPUT ;
    USE SIGNAL ;
    PORT
      LAYER M4 ;
        RECT  0 117.312 0.084 117.336 ;
    END
  END c_i[265]
  PIN c_i[266]
    DIRECTION INPUT ;
    USE SIGNAL ;
    PORT
      LAYER M4 ;
        RECT  0 117.456 0.084 117.48 ;
    END
  END c_i[266]
  PIN c_i[267]
    DIRECTION INPUT ;
    USE SIGNAL ;
    PORT
      LAYER M4 ;
        RECT  0 117.6 0.084 117.624 ;
    END
  END c_i[267]
  PIN c_i[268]
    DIRECTION INPUT ;
    USE SIGNAL ;
    PORT
      LAYER M4 ;
        RECT  0 117.744 0.084 117.768 ;
    END
  END c_i[268]
  PIN c_i[269]
    DIRECTION INPUT ;
    USE SIGNAL ;
    PORT
      LAYER M4 ;
        RECT  0 117.888 0.084 117.912 ;
    END
  END c_i[269]
  PIN c_i[26]
    DIRECTION INPUT ;
    USE SIGNAL ;
    PORT
      LAYER M4 ;
        RECT  0 82.896 0.084 82.92 ;
    END
  END c_i[26]
  PIN c_i[270]
    DIRECTION INPUT ;
    USE SIGNAL ;
    PORT
      LAYER M4 ;
        RECT  0 118.032 0.084 118.056 ;
    END
  END c_i[270]
  PIN c_i[271]
    DIRECTION INPUT ;
    USE SIGNAL ;
    PORT
      LAYER M4 ;
        RECT  0 118.176 0.084 118.2 ;
    END
  END c_i[271]
  PIN c_i[272]
    DIRECTION INPUT ;
    USE SIGNAL ;
    PORT
      LAYER M4 ;
        RECT  0 118.32 0.084 118.344 ;
    END
  END c_i[272]
  PIN c_i[273]
    DIRECTION INPUT ;
    USE SIGNAL ;
    PORT
      LAYER M4 ;
        RECT  0 118.464 0.084 118.488 ;
    END
  END c_i[273]
  PIN c_i[274]
    DIRECTION INPUT ;
    USE SIGNAL ;
    PORT
      LAYER M4 ;
        RECT  0 118.608 0.084 118.632 ;
    END
  END c_i[274]
  PIN c_i[275]
    DIRECTION INPUT ;
    USE SIGNAL ;
    PORT
      LAYER M4 ;
        RECT  0 118.752 0.084 118.776 ;
    END
  END c_i[275]
  PIN c_i[276]
    DIRECTION INPUT ;
    USE SIGNAL ;
    PORT
      LAYER M4 ;
        RECT  0 118.896 0.084 118.92 ;
    END
  END c_i[276]
  PIN c_i[277]
    DIRECTION INPUT ;
    USE SIGNAL ;
    PORT
      LAYER M4 ;
        RECT  0 119.04 0.084 119.064 ;
    END
  END c_i[277]
  PIN c_i[278]
    DIRECTION INPUT ;
    USE SIGNAL ;
    PORT
      LAYER M4 ;
        RECT  0 119.184 0.084 119.208 ;
    END
  END c_i[278]
  PIN c_i[279]
    DIRECTION INPUT ;
    USE SIGNAL ;
    PORT
      LAYER M4 ;
        RECT  0 119.328 0.084 119.352 ;
    END
  END c_i[279]
  PIN c_i[27]
    DIRECTION INPUT ;
    USE SIGNAL ;
    PORT
      LAYER M4 ;
        RECT  0 83.04 0.084 83.064 ;
    END
  END c_i[27]
  PIN c_i[280]
    DIRECTION INPUT ;
    USE SIGNAL ;
    PORT
      LAYER M4 ;
        RECT  0 119.472 0.084 119.496 ;
    END
  END c_i[280]
  PIN c_i[281]
    DIRECTION INPUT ;
    USE SIGNAL ;
    PORT
      LAYER M4 ;
        RECT  0 119.616 0.084 119.64 ;
    END
  END c_i[281]
  PIN c_i[282]
    DIRECTION INPUT ;
    USE SIGNAL ;
    PORT
      LAYER M4 ;
        RECT  0 119.76 0.084 119.784 ;
    END
  END c_i[282]
  PIN c_i[283]
    DIRECTION INPUT ;
    USE SIGNAL ;
    PORT
      LAYER M4 ;
        RECT  0 119.904 0.084 119.928 ;
    END
  END c_i[283]
  PIN c_i[284]
    DIRECTION INPUT ;
    USE SIGNAL ;
    PORT
      LAYER M4 ;
        RECT  0 120.048 0.084 120.072 ;
    END
  END c_i[284]
  PIN c_i[285]
    DIRECTION INPUT ;
    USE SIGNAL ;
    PORT
      LAYER M4 ;
        RECT  0 120.192 0.084 120.216 ;
    END
  END c_i[285]
  PIN c_i[286]
    DIRECTION INPUT ;
    USE SIGNAL ;
    PORT
      LAYER M4 ;
        RECT  0 120.336 0.084 120.36 ;
    END
  END c_i[286]
  PIN c_i[287]
    DIRECTION INPUT ;
    USE SIGNAL ;
    PORT
      LAYER M4 ;
        RECT  0 120.48 0.084 120.504 ;
    END
  END c_i[287]
  PIN c_i[288]
    DIRECTION INPUT ;
    USE SIGNAL ;
    PORT
      LAYER M4 ;
        RECT  0 120.624 0.084 120.648 ;
    END
  END c_i[288]
  PIN c_i[289]
    DIRECTION INPUT ;
    USE SIGNAL ;
    PORT
      LAYER M4 ;
        RECT  0 120.768 0.084 120.792 ;
    END
  END c_i[289]
  PIN c_i[28]
    DIRECTION INPUT ;
    USE SIGNAL ;
    PORT
      LAYER M4 ;
        RECT  0 83.184 0.084 83.208 ;
    END
  END c_i[28]
  PIN c_i[290]
    DIRECTION INPUT ;
    USE SIGNAL ;
    PORT
      LAYER M4 ;
        RECT  0 120.912 0.084 120.936 ;
    END
  END c_i[290]
  PIN c_i[291]
    DIRECTION INPUT ;
    USE SIGNAL ;
    PORT
      LAYER M4 ;
        RECT  0 121.056 0.084 121.08 ;
    END
  END c_i[291]
  PIN c_i[292]
    DIRECTION INPUT ;
    USE SIGNAL ;
    PORT
      LAYER M4 ;
        RECT  0 121.2 0.084 121.224 ;
    END
  END c_i[292]
  PIN c_i[293]
    DIRECTION INPUT ;
    USE SIGNAL ;
    PORT
      LAYER M4 ;
        RECT  0 121.344 0.084 121.368 ;
    END
  END c_i[293]
  PIN c_i[294]
    DIRECTION INPUT ;
    USE SIGNAL ;
    PORT
      LAYER M4 ;
        RECT  0 121.488 0.084 121.512 ;
    END
  END c_i[294]
  PIN c_i[295]
    DIRECTION INPUT ;
    USE SIGNAL ;
    PORT
      LAYER M4 ;
        RECT  0 121.632 0.084 121.656 ;
    END
  END c_i[295]
  PIN c_i[296]
    DIRECTION INPUT ;
    USE SIGNAL ;
    PORT
      LAYER M4 ;
        RECT  0 121.776 0.084 121.8 ;
    END
  END c_i[296]
  PIN c_i[297]
    DIRECTION INPUT ;
    USE SIGNAL ;
    PORT
      LAYER M4 ;
        RECT  0 121.92 0.084 121.944 ;
    END
  END c_i[297]
  PIN c_i[298]
    DIRECTION INPUT ;
    USE SIGNAL ;
    PORT
      LAYER M4 ;
        RECT  0 122.064 0.084 122.088 ;
    END
  END c_i[298]
  PIN c_i[299]
    DIRECTION INPUT ;
    USE SIGNAL ;
    PORT
      LAYER M4 ;
        RECT  0 122.208 0.084 122.232 ;
    END
  END c_i[299]
  PIN c_i[29]
    DIRECTION INPUT ;
    USE SIGNAL ;
    PORT
      LAYER M4 ;
        RECT  0 83.328 0.084 83.352 ;
    END
  END c_i[29]
  PIN c_i[2]
    DIRECTION INPUT ;
    USE SIGNAL ;
    PORT
      LAYER M4 ;
        RECT  0 79.44 0.084 79.464 ;
    END
  END c_i[2]
  PIN c_i[300]
    DIRECTION INPUT ;
    USE SIGNAL ;
    PORT
      LAYER M4 ;
        RECT  0 122.352 0.084 122.376 ;
    END
  END c_i[300]
  PIN c_i[301]
    DIRECTION INPUT ;
    USE SIGNAL ;
    PORT
      LAYER M4 ;
        RECT  0 122.496 0.084 122.52 ;
    END
  END c_i[301]
  PIN c_i[302]
    DIRECTION INPUT ;
    USE SIGNAL ;
    PORT
      LAYER M4 ;
        RECT  0 122.64 0.084 122.664 ;
    END
  END c_i[302]
  PIN c_i[303]
    DIRECTION INPUT ;
    USE SIGNAL ;
    PORT
      LAYER M4 ;
        RECT  0 122.784 0.084 122.808 ;
    END
  END c_i[303]
  PIN c_i[304]
    DIRECTION INPUT ;
    USE SIGNAL ;
    PORT
      LAYER M4 ;
        RECT  0 122.928 0.084 122.952 ;
    END
  END c_i[304]
  PIN c_i[305]
    DIRECTION INPUT ;
    USE SIGNAL ;
    PORT
      LAYER M4 ;
        RECT  0 123.072 0.084 123.096 ;
    END
  END c_i[305]
  PIN c_i[306]
    DIRECTION INPUT ;
    USE SIGNAL ;
    PORT
      LAYER M4 ;
        RECT  0 123.216 0.084 123.24 ;
    END
  END c_i[306]
  PIN c_i[307]
    DIRECTION INPUT ;
    USE SIGNAL ;
    PORT
      LAYER M4 ;
        RECT  0 123.36 0.084 123.384 ;
    END
  END c_i[307]
  PIN c_i[308]
    DIRECTION INPUT ;
    USE SIGNAL ;
    PORT
      LAYER M4 ;
        RECT  0 123.504 0.084 123.528 ;
    END
  END c_i[308]
  PIN c_i[309]
    DIRECTION INPUT ;
    USE SIGNAL ;
    PORT
      LAYER M4 ;
        RECT  0 123.648 0.084 123.672 ;
    END
  END c_i[309]
  PIN c_i[30]
    DIRECTION INPUT ;
    USE SIGNAL ;
    PORT
      LAYER M4 ;
        RECT  0 83.472 0.084 83.496 ;
    END
  END c_i[30]
  PIN c_i[310]
    DIRECTION INPUT ;
    USE SIGNAL ;
    PORT
      LAYER M4 ;
        RECT  0 123.792 0.084 123.816 ;
    END
  END c_i[310]
  PIN c_i[311]
    DIRECTION INPUT ;
    USE SIGNAL ;
    PORT
      LAYER M4 ;
        RECT  0 123.936 0.084 123.96 ;
    END
  END c_i[311]
  PIN c_i[312]
    DIRECTION INPUT ;
    USE SIGNAL ;
    PORT
      LAYER M4 ;
        RECT  0 124.08 0.084 124.104 ;
    END
  END c_i[312]
  PIN c_i[313]
    DIRECTION INPUT ;
    USE SIGNAL ;
    PORT
      LAYER M4 ;
        RECT  0 124.224 0.084 124.248 ;
    END
  END c_i[313]
  PIN c_i[314]
    DIRECTION INPUT ;
    USE SIGNAL ;
    PORT
      LAYER M4 ;
        RECT  0 124.368 0.084 124.392 ;
    END
  END c_i[314]
  PIN c_i[315]
    DIRECTION INPUT ;
    USE SIGNAL ;
    PORT
      LAYER M4 ;
        RECT  0 124.512 0.084 124.536 ;
    END
  END c_i[315]
  PIN c_i[316]
    DIRECTION INPUT ;
    USE SIGNAL ;
    PORT
      LAYER M4 ;
        RECT  0 124.656 0.084 124.68 ;
    END
  END c_i[316]
  PIN c_i[317]
    DIRECTION INPUT ;
    USE SIGNAL ;
    PORT
      LAYER M4 ;
        RECT  0 124.8 0.084 124.824 ;
    END
  END c_i[317]
  PIN c_i[318]
    DIRECTION INPUT ;
    USE SIGNAL ;
    PORT
      LAYER M4 ;
        RECT  0 124.944 0.084 124.968 ;
    END
  END c_i[318]
  PIN c_i[319]
    DIRECTION INPUT ;
    USE SIGNAL ;
    PORT
      LAYER M4 ;
        RECT  0 125.088 0.084 125.112 ;
    END
  END c_i[319]
  PIN c_i[31]
    DIRECTION INPUT ;
    USE SIGNAL ;
    PORT
      LAYER M4 ;
        RECT  0 83.616 0.084 83.64 ;
    END
  END c_i[31]
  PIN c_i[320]
    DIRECTION INPUT ;
    USE SIGNAL ;
    PORT
      LAYER M4 ;
        RECT  0 125.232 0.084 125.256 ;
    END
  END c_i[320]
  PIN c_i[321]
    DIRECTION INPUT ;
    USE SIGNAL ;
    PORT
      LAYER M4 ;
        RECT  0 125.376 0.084 125.4 ;
    END
  END c_i[321]
  PIN c_i[322]
    DIRECTION INPUT ;
    USE SIGNAL ;
    PORT
      LAYER M4 ;
        RECT  0 125.52 0.084 125.544 ;
    END
  END c_i[322]
  PIN c_i[323]
    DIRECTION INPUT ;
    USE SIGNAL ;
    PORT
      LAYER M4 ;
        RECT  0 125.664 0.084 125.688 ;
    END
  END c_i[323]
  PIN c_i[324]
    DIRECTION INPUT ;
    USE SIGNAL ;
    PORT
      LAYER M4 ;
        RECT  0 125.808 0.084 125.832 ;
    END
  END c_i[324]
  PIN c_i[325]
    DIRECTION INPUT ;
    USE SIGNAL ;
    PORT
      LAYER M4 ;
        RECT  0 125.952 0.084 125.976 ;
    END
  END c_i[325]
  PIN c_i[326]
    DIRECTION INPUT ;
    USE SIGNAL ;
    PORT
      LAYER M4 ;
        RECT  0 126.096 0.084 126.12 ;
    END
  END c_i[326]
  PIN c_i[327]
    DIRECTION INPUT ;
    USE SIGNAL ;
    PORT
      LAYER M4 ;
        RECT  0 126.24 0.084 126.264 ;
    END
  END c_i[327]
  PIN c_i[328]
    DIRECTION INPUT ;
    USE SIGNAL ;
    PORT
      LAYER M4 ;
        RECT  0 126.384 0.084 126.408 ;
    END
  END c_i[328]
  PIN c_i[329]
    DIRECTION INPUT ;
    USE SIGNAL ;
    PORT
      LAYER M4 ;
        RECT  0 126.528 0.084 126.552 ;
    END
  END c_i[329]
  PIN c_i[32]
    DIRECTION INPUT ;
    USE SIGNAL ;
    PORT
      LAYER M4 ;
        RECT  0 83.76 0.084 83.784 ;
    END
  END c_i[32]
  PIN c_i[330]
    DIRECTION INPUT ;
    USE SIGNAL ;
    PORT
      LAYER M4 ;
        RECT  0 126.672 0.084 126.696 ;
    END
  END c_i[330]
  PIN c_i[331]
    DIRECTION INPUT ;
    USE SIGNAL ;
    PORT
      LAYER M4 ;
        RECT  0 126.816 0.084 126.84 ;
    END
  END c_i[331]
  PIN c_i[332]
    DIRECTION INPUT ;
    USE SIGNAL ;
    PORT
      LAYER M4 ;
        RECT  0 126.96 0.084 126.984 ;
    END
  END c_i[332]
  PIN c_i[333]
    DIRECTION INPUT ;
    USE SIGNAL ;
    PORT
      LAYER M4 ;
        RECT  0 127.104 0.084 127.128 ;
    END
  END c_i[333]
  PIN c_i[334]
    DIRECTION INPUT ;
    USE SIGNAL ;
    PORT
      LAYER M4 ;
        RECT  0 127.248 0.084 127.272 ;
    END
  END c_i[334]
  PIN c_i[335]
    DIRECTION INPUT ;
    USE SIGNAL ;
    PORT
      LAYER M4 ;
        RECT  0 127.392 0.084 127.416 ;
    END
  END c_i[335]
  PIN c_i[336]
    DIRECTION INPUT ;
    USE SIGNAL ;
    PORT
      LAYER M4 ;
        RECT  0 127.536 0.084 127.56 ;
    END
  END c_i[336]
  PIN c_i[337]
    DIRECTION INPUT ;
    USE SIGNAL ;
    PORT
      LAYER M4 ;
        RECT  0 127.68 0.084 127.704 ;
    END
  END c_i[337]
  PIN c_i[338]
    DIRECTION INPUT ;
    USE SIGNAL ;
    PORT
      LAYER M4 ;
        RECT  0 127.824 0.084 127.848 ;
    END
  END c_i[338]
  PIN c_i[339]
    DIRECTION INPUT ;
    USE SIGNAL ;
    PORT
      LAYER M4 ;
        RECT  0 127.968 0.084 127.992 ;
    END
  END c_i[339]
  PIN c_i[33]
    DIRECTION INPUT ;
    USE SIGNAL ;
    PORT
      LAYER M4 ;
        RECT  0 83.904 0.084 83.928 ;
    END
  END c_i[33]
  PIN c_i[340]
    DIRECTION INPUT ;
    USE SIGNAL ;
    PORT
      LAYER M4 ;
        RECT  0 128.112 0.084 128.136 ;
    END
  END c_i[340]
  PIN c_i[341]
    DIRECTION INPUT ;
    USE SIGNAL ;
    PORT
      LAYER M4 ;
        RECT  0 128.256 0.084 128.28 ;
    END
  END c_i[341]
  PIN c_i[342]
    DIRECTION INPUT ;
    USE SIGNAL ;
    PORT
      LAYER M4 ;
        RECT  0 128.4 0.084 128.424 ;
    END
  END c_i[342]
  PIN c_i[343]
    DIRECTION INPUT ;
    USE SIGNAL ;
    PORT
      LAYER M4 ;
        RECT  0 128.544 0.084 128.568 ;
    END
  END c_i[343]
  PIN c_i[344]
    DIRECTION INPUT ;
    USE SIGNAL ;
    PORT
      LAYER M4 ;
        RECT  0 128.688 0.084 128.712 ;
    END
  END c_i[344]
  PIN c_i[345]
    DIRECTION INPUT ;
    USE SIGNAL ;
    PORT
      LAYER M4 ;
        RECT  0 128.832 0.084 128.856 ;
    END
  END c_i[345]
  PIN c_i[346]
    DIRECTION INPUT ;
    USE SIGNAL ;
    PORT
      LAYER M4 ;
        RECT  0 128.976 0.084 129 ;
    END
  END c_i[346]
  PIN c_i[347]
    DIRECTION INPUT ;
    USE SIGNAL ;
    PORT
      LAYER M4 ;
        RECT  0 129.12 0.084 129.144 ;
    END
  END c_i[347]
  PIN c_i[348]
    DIRECTION INPUT ;
    USE SIGNAL ;
    PORT
      LAYER M4 ;
        RECT  0 129.264 0.084 129.288 ;
    END
  END c_i[348]
  PIN c_i[349]
    DIRECTION INPUT ;
    USE SIGNAL ;
    PORT
      LAYER M4 ;
        RECT  0 129.408 0.084 129.432 ;
    END
  END c_i[349]
  PIN c_i[34]
    DIRECTION INPUT ;
    USE SIGNAL ;
    PORT
      LAYER M4 ;
        RECT  0 84.048 0.084 84.072 ;
    END
  END c_i[34]
  PIN c_i[350]
    DIRECTION INPUT ;
    USE SIGNAL ;
    PORT
      LAYER M4 ;
        RECT  0 129.552 0.084 129.576 ;
    END
  END c_i[350]
  PIN c_i[351]
    DIRECTION INPUT ;
    USE SIGNAL ;
    PORT
      LAYER M4 ;
        RECT  0 129.696 0.084 129.72 ;
    END
  END c_i[351]
  PIN c_i[352]
    DIRECTION INPUT ;
    USE SIGNAL ;
    PORT
      LAYER M4 ;
        RECT  0 129.84 0.084 129.864 ;
    END
  END c_i[352]
  PIN c_i[353]
    DIRECTION INPUT ;
    USE SIGNAL ;
    PORT
      LAYER M4 ;
        RECT  0 129.984 0.084 130.008 ;
    END
  END c_i[353]
  PIN c_i[354]
    DIRECTION INPUT ;
    USE SIGNAL ;
    PORT
      LAYER M4 ;
        RECT  0 130.128 0.084 130.152 ;
    END
  END c_i[354]
  PIN c_i[355]
    DIRECTION INPUT ;
    USE SIGNAL ;
    PORT
      LAYER M4 ;
        RECT  0 130.272 0.084 130.296 ;
    END
  END c_i[355]
  PIN c_i[356]
    DIRECTION INPUT ;
    USE SIGNAL ;
    PORT
      LAYER M4 ;
        RECT  0 130.416 0.084 130.44 ;
    END
  END c_i[356]
  PIN c_i[357]
    DIRECTION INPUT ;
    USE SIGNAL ;
    PORT
      LAYER M4 ;
        RECT  0 130.56 0.084 130.584 ;
    END
  END c_i[357]
  PIN c_i[358]
    DIRECTION INPUT ;
    USE SIGNAL ;
    PORT
      LAYER M4 ;
        RECT  0 130.704 0.084 130.728 ;
    END
  END c_i[358]
  PIN c_i[359]
    DIRECTION INPUT ;
    USE SIGNAL ;
    PORT
      LAYER M4 ;
        RECT  0 130.848 0.084 130.872 ;
    END
  END c_i[359]
  PIN c_i[35]
    DIRECTION INPUT ;
    USE SIGNAL ;
    PORT
      LAYER M4 ;
        RECT  0 84.192 0.084 84.216 ;
    END
  END c_i[35]
  PIN c_i[360]
    DIRECTION INPUT ;
    USE SIGNAL ;
    PORT
      LAYER M4 ;
        RECT  0 130.992 0.084 131.016 ;
    END
  END c_i[360]
  PIN c_i[361]
    DIRECTION INPUT ;
    USE SIGNAL ;
    PORT
      LAYER M4 ;
        RECT  0 131.136 0.084 131.16 ;
    END
  END c_i[361]
  PIN c_i[362]
    DIRECTION INPUT ;
    USE SIGNAL ;
    PORT
      LAYER M4 ;
        RECT  0 131.28 0.084 131.304 ;
    END
  END c_i[362]
  PIN c_i[363]
    DIRECTION INPUT ;
    USE SIGNAL ;
    PORT
      LAYER M4 ;
        RECT  0 131.424 0.084 131.448 ;
    END
  END c_i[363]
  PIN c_i[364]
    DIRECTION INPUT ;
    USE SIGNAL ;
    PORT
      LAYER M4 ;
        RECT  0 131.568 0.084 131.592 ;
    END
  END c_i[364]
  PIN c_i[365]
    DIRECTION INPUT ;
    USE SIGNAL ;
    PORT
      LAYER M4 ;
        RECT  0 131.712 0.084 131.736 ;
    END
  END c_i[365]
  PIN c_i[366]
    DIRECTION INPUT ;
    USE SIGNAL ;
    PORT
      LAYER M4 ;
        RECT  0 131.856 0.084 131.88 ;
    END
  END c_i[366]
  PIN c_i[367]
    DIRECTION INPUT ;
    USE SIGNAL ;
    PORT
      LAYER M4 ;
        RECT  0 132 0.084 132.024 ;
    END
  END c_i[367]
  PIN c_i[368]
    DIRECTION INPUT ;
    USE SIGNAL ;
    PORT
      LAYER M4 ;
        RECT  0 132.144 0.084 132.168 ;
    END
  END c_i[368]
  PIN c_i[369]
    DIRECTION INPUT ;
    USE SIGNAL ;
    PORT
      LAYER M4 ;
        RECT  0 132.288 0.084 132.312 ;
    END
  END c_i[369]
  PIN c_i[36]
    DIRECTION INPUT ;
    USE SIGNAL ;
    PORT
      LAYER M4 ;
        RECT  0 84.336 0.084 84.36 ;
    END
  END c_i[36]
  PIN c_i[370]
    DIRECTION INPUT ;
    USE SIGNAL ;
    PORT
      LAYER M4 ;
        RECT  0 132.432 0.084 132.456 ;
    END
  END c_i[370]
  PIN c_i[371]
    DIRECTION INPUT ;
    USE SIGNAL ;
    PORT
      LAYER M4 ;
        RECT  0 132.576 0.084 132.6 ;
    END
  END c_i[371]
  PIN c_i[372]
    DIRECTION INPUT ;
    USE SIGNAL ;
    PORT
      LAYER M4 ;
        RECT  0 132.72 0.084 132.744 ;
    END
  END c_i[372]
  PIN c_i[373]
    DIRECTION INPUT ;
    USE SIGNAL ;
    PORT
      LAYER M4 ;
        RECT  0 132.864 0.084 132.888 ;
    END
  END c_i[373]
  PIN c_i[374]
    DIRECTION INPUT ;
    USE SIGNAL ;
    PORT
      LAYER M4 ;
        RECT  0 133.008 0.084 133.032 ;
    END
  END c_i[374]
  PIN c_i[375]
    DIRECTION INPUT ;
    USE SIGNAL ;
    PORT
      LAYER M4 ;
        RECT  0 133.152 0.084 133.176 ;
    END
  END c_i[375]
  PIN c_i[376]
    DIRECTION INPUT ;
    USE SIGNAL ;
    PORT
      LAYER M4 ;
        RECT  0 133.296 0.084 133.32 ;
    END
  END c_i[376]
  PIN c_i[377]
    DIRECTION INPUT ;
    USE SIGNAL ;
    PORT
      LAYER M4 ;
        RECT  0 133.44 0.084 133.464 ;
    END
  END c_i[377]
  PIN c_i[378]
    DIRECTION INPUT ;
    USE SIGNAL ;
    PORT
      LAYER M4 ;
        RECT  0 133.584 0.084 133.608 ;
    END
  END c_i[378]
  PIN c_i[379]
    DIRECTION INPUT ;
    USE SIGNAL ;
    PORT
      LAYER M4 ;
        RECT  0 133.728 0.084 133.752 ;
    END
  END c_i[379]
  PIN c_i[37]
    DIRECTION INPUT ;
    USE SIGNAL ;
    PORT
      LAYER M4 ;
        RECT  0 84.48 0.084 84.504 ;
    END
  END c_i[37]
  PIN c_i[380]
    DIRECTION INPUT ;
    USE SIGNAL ;
    PORT
      LAYER M4 ;
        RECT  0 133.872 0.084 133.896 ;
    END
  END c_i[380]
  PIN c_i[381]
    DIRECTION INPUT ;
    USE SIGNAL ;
    PORT
      LAYER M4 ;
        RECT  0 134.016 0.084 134.04 ;
    END
  END c_i[381]
  PIN c_i[382]
    DIRECTION INPUT ;
    USE SIGNAL ;
    PORT
      LAYER M4 ;
        RECT  0 134.16 0.084 134.184 ;
    END
  END c_i[382]
  PIN c_i[383]
    DIRECTION INPUT ;
    USE SIGNAL ;
    PORT
      LAYER M4 ;
        RECT  0 134.304 0.084 134.328 ;
    END
  END c_i[383]
  PIN c_i[384]
    DIRECTION INPUT ;
    USE SIGNAL ;
    PORT
      LAYER M4 ;
        RECT  0 134.448 0.084 134.472 ;
    END
  END c_i[384]
  PIN c_i[385]
    DIRECTION INPUT ;
    USE SIGNAL ;
    PORT
      LAYER M4 ;
        RECT  0 134.592 0.084 134.616 ;
    END
  END c_i[385]
  PIN c_i[386]
    DIRECTION INPUT ;
    USE SIGNAL ;
    PORT
      LAYER M4 ;
        RECT  0 134.736 0.084 134.76 ;
    END
  END c_i[386]
  PIN c_i[387]
    DIRECTION INPUT ;
    USE SIGNAL ;
    PORT
      LAYER M4 ;
        RECT  0 134.88 0.084 134.904 ;
    END
  END c_i[387]
  PIN c_i[388]
    DIRECTION INPUT ;
    USE SIGNAL ;
    PORT
      LAYER M4 ;
        RECT  0 135.024 0.084 135.048 ;
    END
  END c_i[388]
  PIN c_i[389]
    DIRECTION INPUT ;
    USE SIGNAL ;
    PORT
      LAYER M4 ;
        RECT  0 135.168 0.084 135.192 ;
    END
  END c_i[389]
  PIN c_i[38]
    DIRECTION INPUT ;
    USE SIGNAL ;
    PORT
      LAYER M4 ;
        RECT  0 84.624 0.084 84.648 ;
    END
  END c_i[38]
  PIN c_i[390]
    DIRECTION INPUT ;
    USE SIGNAL ;
    PORT
      LAYER M4 ;
        RECT  0 135.312 0.084 135.336 ;
    END
  END c_i[390]
  PIN c_i[391]
    DIRECTION INPUT ;
    USE SIGNAL ;
    PORT
      LAYER M4 ;
        RECT  0 135.456 0.084 135.48 ;
    END
  END c_i[391]
  PIN c_i[392]
    DIRECTION INPUT ;
    USE SIGNAL ;
    PORT
      LAYER M4 ;
        RECT  0 135.6 0.084 135.624 ;
    END
  END c_i[392]
  PIN c_i[393]
    DIRECTION INPUT ;
    USE SIGNAL ;
    PORT
      LAYER M4 ;
        RECT  0 135.744 0.084 135.768 ;
    END
  END c_i[393]
  PIN c_i[394]
    DIRECTION INPUT ;
    USE SIGNAL ;
    PORT
      LAYER M4 ;
        RECT  0 135.888 0.084 135.912 ;
    END
  END c_i[394]
  PIN c_i[395]
    DIRECTION INPUT ;
    USE SIGNAL ;
    PORT
      LAYER M4 ;
        RECT  0 136.032 0.084 136.056 ;
    END
  END c_i[395]
  PIN c_i[396]
    DIRECTION INPUT ;
    USE SIGNAL ;
    PORT
      LAYER M4 ;
        RECT  0 136.176 0.084 136.2 ;
    END
  END c_i[396]
  PIN c_i[397]
    DIRECTION INPUT ;
    USE SIGNAL ;
    PORT
      LAYER M4 ;
        RECT  0 136.32 0.084 136.344 ;
    END
  END c_i[397]
  PIN c_i[398]
    DIRECTION INPUT ;
    USE SIGNAL ;
    PORT
      LAYER M4 ;
        RECT  0 136.464 0.084 136.488 ;
    END
  END c_i[398]
  PIN c_i[399]
    DIRECTION INPUT ;
    USE SIGNAL ;
    PORT
      LAYER M4 ;
        RECT  0 136.608 0.084 136.632 ;
    END
  END c_i[399]
  PIN c_i[39]
    DIRECTION INPUT ;
    USE SIGNAL ;
    PORT
      LAYER M4 ;
        RECT  0 84.768 0.084 84.792 ;
    END
  END c_i[39]
  PIN c_i[3]
    DIRECTION INPUT ;
    USE SIGNAL ;
    PORT
      LAYER M4 ;
        RECT  0 79.584 0.084 79.608 ;
    END
  END c_i[3]
  PIN c_i[400]
    DIRECTION INPUT ;
    USE SIGNAL ;
    PORT
      LAYER M4 ;
        RECT  0 136.752 0.084 136.776 ;
    END
  END c_i[400]
  PIN c_i[401]
    DIRECTION INPUT ;
    USE SIGNAL ;
    PORT
      LAYER M4 ;
        RECT  0 136.896 0.084 136.92 ;
    END
  END c_i[401]
  PIN c_i[402]
    DIRECTION INPUT ;
    USE SIGNAL ;
    PORT
      LAYER M4 ;
        RECT  0 137.04 0.084 137.064 ;
    END
  END c_i[402]
  PIN c_i[403]
    DIRECTION INPUT ;
    USE SIGNAL ;
    PORT
      LAYER M4 ;
        RECT  0 137.184 0.084 137.208 ;
    END
  END c_i[403]
  PIN c_i[404]
    DIRECTION INPUT ;
    USE SIGNAL ;
    PORT
      LAYER M4 ;
        RECT  0 137.328 0.084 137.352 ;
    END
  END c_i[404]
  PIN c_i[405]
    DIRECTION INPUT ;
    USE SIGNAL ;
    PORT
      LAYER M4 ;
        RECT  0 137.472 0.084 137.496 ;
    END
  END c_i[405]
  PIN c_i[406]
    DIRECTION INPUT ;
    USE SIGNAL ;
    PORT
      LAYER M4 ;
        RECT  0 137.616 0.084 137.64 ;
    END
  END c_i[406]
  PIN c_i[407]
    DIRECTION INPUT ;
    USE SIGNAL ;
    PORT
      LAYER M4 ;
        RECT  0 137.76 0.084 137.784 ;
    END
  END c_i[407]
  PIN c_i[408]
    DIRECTION INPUT ;
    USE SIGNAL ;
    PORT
      LAYER M4 ;
        RECT  0 137.904 0.084 137.928 ;
    END
  END c_i[408]
  PIN c_i[409]
    DIRECTION INPUT ;
    USE SIGNAL ;
    PORT
      LAYER M4 ;
        RECT  0 138.048 0.084 138.072 ;
    END
  END c_i[409]
  PIN c_i[40]
    DIRECTION INPUT ;
    USE SIGNAL ;
    PORT
      LAYER M4 ;
        RECT  0 84.912 0.084 84.936 ;
    END
  END c_i[40]
  PIN c_i[410]
    DIRECTION INPUT ;
    USE SIGNAL ;
    PORT
      LAYER M4 ;
        RECT  0 138.192 0.084 138.216 ;
    END
  END c_i[410]
  PIN c_i[411]
    DIRECTION INPUT ;
    USE SIGNAL ;
    PORT
      LAYER M4 ;
        RECT  0 138.336 0.084 138.36 ;
    END
  END c_i[411]
  PIN c_i[412]
    DIRECTION INPUT ;
    USE SIGNAL ;
    PORT
      LAYER M4 ;
        RECT  0 138.48 0.084 138.504 ;
    END
  END c_i[412]
  PIN c_i[413]
    DIRECTION INPUT ;
    USE SIGNAL ;
    PORT
      LAYER M4 ;
        RECT  0 138.624 0.084 138.648 ;
    END
  END c_i[413]
  PIN c_i[414]
    DIRECTION INPUT ;
    USE SIGNAL ;
    PORT
      LAYER M4 ;
        RECT  0 138.768 0.084 138.792 ;
    END
  END c_i[414]
  PIN c_i[415]
    DIRECTION INPUT ;
    USE SIGNAL ;
    PORT
      LAYER M4 ;
        RECT  0 138.912 0.084 138.936 ;
    END
  END c_i[415]
  PIN c_i[416]
    DIRECTION INPUT ;
    USE SIGNAL ;
    PORT
      LAYER M4 ;
        RECT  0 139.056 0.084 139.08 ;
    END
  END c_i[416]
  PIN c_i[417]
    DIRECTION INPUT ;
    USE SIGNAL ;
    PORT
      LAYER M4 ;
        RECT  0 139.2 0.084 139.224 ;
    END
  END c_i[417]
  PIN c_i[418]
    DIRECTION INPUT ;
    USE SIGNAL ;
    PORT
      LAYER M4 ;
        RECT  0 139.344 0.084 139.368 ;
    END
  END c_i[418]
  PIN c_i[419]
    DIRECTION INPUT ;
    USE SIGNAL ;
    PORT
      LAYER M4 ;
        RECT  0 139.488 0.084 139.512 ;
    END
  END c_i[419]
  PIN c_i[41]
    DIRECTION INPUT ;
    USE SIGNAL ;
    PORT
      LAYER M4 ;
        RECT  0 85.056 0.084 85.08 ;
    END
  END c_i[41]
  PIN c_i[420]
    DIRECTION INPUT ;
    USE SIGNAL ;
    PORT
      LAYER M4 ;
        RECT  0 139.632 0.084 139.656 ;
    END
  END c_i[420]
  PIN c_i[421]
    DIRECTION INPUT ;
    USE SIGNAL ;
    PORT
      LAYER M4 ;
        RECT  0 139.776 0.084 139.8 ;
    END
  END c_i[421]
  PIN c_i[422]
    DIRECTION INPUT ;
    USE SIGNAL ;
    PORT
      LAYER M4 ;
        RECT  0 139.92 0.084 139.944 ;
    END
  END c_i[422]
  PIN c_i[423]
    DIRECTION INPUT ;
    USE SIGNAL ;
    PORT
      LAYER M4 ;
        RECT  0 140.064 0.084 140.088 ;
    END
  END c_i[423]
  PIN c_i[424]
    DIRECTION INPUT ;
    USE SIGNAL ;
    PORT
      LAYER M4 ;
        RECT  0 140.208 0.084 140.232 ;
    END
  END c_i[424]
  PIN c_i[425]
    DIRECTION INPUT ;
    USE SIGNAL ;
    PORT
      LAYER M4 ;
        RECT  0 140.352 0.084 140.376 ;
    END
  END c_i[425]
  PIN c_i[426]
    DIRECTION INPUT ;
    USE SIGNAL ;
    PORT
      LAYER M4 ;
        RECT  0 140.496 0.084 140.52 ;
    END
  END c_i[426]
  PIN c_i[427]
    DIRECTION INPUT ;
    USE SIGNAL ;
    PORT
      LAYER M4 ;
        RECT  0 140.64 0.084 140.664 ;
    END
  END c_i[427]
  PIN c_i[428]
    DIRECTION INPUT ;
    USE SIGNAL ;
    PORT
      LAYER M4 ;
        RECT  0 140.784 0.084 140.808 ;
    END
  END c_i[428]
  PIN c_i[429]
    DIRECTION INPUT ;
    USE SIGNAL ;
    PORT
      LAYER M4 ;
        RECT  0 140.928 0.084 140.952 ;
    END
  END c_i[429]
  PIN c_i[42]
    DIRECTION INPUT ;
    USE SIGNAL ;
    PORT
      LAYER M4 ;
        RECT  0 85.2 0.084 85.224 ;
    END
  END c_i[42]
  PIN c_i[430]
    DIRECTION INPUT ;
    USE SIGNAL ;
    PORT
      LAYER M4 ;
        RECT  0 141.072 0.084 141.096 ;
    END
  END c_i[430]
  PIN c_i[431]
    DIRECTION INPUT ;
    USE SIGNAL ;
    PORT
      LAYER M4 ;
        RECT  0 141.216 0.084 141.24 ;
    END
  END c_i[431]
  PIN c_i[432]
    DIRECTION INPUT ;
    USE SIGNAL ;
    PORT
      LAYER M4 ;
        RECT  0 141.36 0.084 141.384 ;
    END
  END c_i[432]
  PIN c_i[433]
    DIRECTION INPUT ;
    USE SIGNAL ;
    PORT
      LAYER M4 ;
        RECT  0 141.504 0.084 141.528 ;
    END
  END c_i[433]
  PIN c_i[434]
    DIRECTION INPUT ;
    USE SIGNAL ;
    PORT
      LAYER M4 ;
        RECT  0 141.648 0.084 141.672 ;
    END
  END c_i[434]
  PIN c_i[435]
    DIRECTION INPUT ;
    USE SIGNAL ;
    PORT
      LAYER M4 ;
        RECT  0 141.792 0.084 141.816 ;
    END
  END c_i[435]
  PIN c_i[436]
    DIRECTION INPUT ;
    USE SIGNAL ;
    PORT
      LAYER M4 ;
        RECT  0 141.936 0.084 141.96 ;
    END
  END c_i[436]
  PIN c_i[437]
    DIRECTION INPUT ;
    USE SIGNAL ;
    PORT
      LAYER M4 ;
        RECT  0 142.08 0.084 142.104 ;
    END
  END c_i[437]
  PIN c_i[438]
    DIRECTION INPUT ;
    USE SIGNAL ;
    PORT
      LAYER M4 ;
        RECT  0 142.224 0.084 142.248 ;
    END
  END c_i[438]
  PIN c_i[439]
    DIRECTION INPUT ;
    USE SIGNAL ;
    PORT
      LAYER M4 ;
        RECT  0 142.368 0.084 142.392 ;
    END
  END c_i[439]
  PIN c_i[43]
    DIRECTION INPUT ;
    USE SIGNAL ;
    PORT
      LAYER M4 ;
        RECT  0 85.344 0.084 85.368 ;
    END
  END c_i[43]
  PIN c_i[440]
    DIRECTION INPUT ;
    USE SIGNAL ;
    PORT
      LAYER M4 ;
        RECT  0 142.512 0.084 142.536 ;
    END
  END c_i[440]
  PIN c_i[441]
    DIRECTION INPUT ;
    USE SIGNAL ;
    PORT
      LAYER M4 ;
        RECT  0 142.656 0.084 142.68 ;
    END
  END c_i[441]
  PIN c_i[442]
    DIRECTION INPUT ;
    USE SIGNAL ;
    PORT
      LAYER M4 ;
        RECT  0 142.8 0.084 142.824 ;
    END
  END c_i[442]
  PIN c_i[443]
    DIRECTION INPUT ;
    USE SIGNAL ;
    PORT
      LAYER M4 ;
        RECT  0 142.944 0.084 142.968 ;
    END
  END c_i[443]
  PIN c_i[444]
    DIRECTION INPUT ;
    USE SIGNAL ;
    PORT
      LAYER M4 ;
        RECT  0 143.088 0.084 143.112 ;
    END
  END c_i[444]
  PIN c_i[445]
    DIRECTION INPUT ;
    USE SIGNAL ;
    PORT
      LAYER M4 ;
        RECT  0 143.232 0.084 143.256 ;
    END
  END c_i[445]
  PIN c_i[446]
    DIRECTION INPUT ;
    USE SIGNAL ;
    PORT
      LAYER M4 ;
        RECT  0 143.376 0.084 143.4 ;
    END
  END c_i[446]
  PIN c_i[447]
    DIRECTION INPUT ;
    USE SIGNAL ;
    PORT
      LAYER M4 ;
        RECT  0 143.52 0.084 143.544 ;
    END
  END c_i[447]
  PIN c_i[448]
    DIRECTION INPUT ;
    USE SIGNAL ;
    PORT
      LAYER M4 ;
        RECT  0 143.664 0.084 143.688 ;
    END
  END c_i[448]
  PIN c_i[449]
    DIRECTION INPUT ;
    USE SIGNAL ;
    PORT
      LAYER M4 ;
        RECT  0 143.808 0.084 143.832 ;
    END
  END c_i[449]
  PIN c_i[44]
    DIRECTION INPUT ;
    USE SIGNAL ;
    PORT
      LAYER M4 ;
        RECT  0 85.488 0.084 85.512 ;
    END
  END c_i[44]
  PIN c_i[450]
    DIRECTION INPUT ;
    USE SIGNAL ;
    PORT
      LAYER M4 ;
        RECT  0 143.952 0.084 143.976 ;
    END
  END c_i[450]
  PIN c_i[451]
    DIRECTION INPUT ;
    USE SIGNAL ;
    PORT
      LAYER M4 ;
        RECT  0 144.096 0.084 144.12 ;
    END
  END c_i[451]
  PIN c_i[452]
    DIRECTION INPUT ;
    USE SIGNAL ;
    PORT
      LAYER M4 ;
        RECT  0 144.24 0.084 144.264 ;
    END
  END c_i[452]
  PIN c_i[453]
    DIRECTION INPUT ;
    USE SIGNAL ;
    PORT
      LAYER M4 ;
        RECT  0 144.384 0.084 144.408 ;
    END
  END c_i[453]
  PIN c_i[454]
    DIRECTION INPUT ;
    USE SIGNAL ;
    PORT
      LAYER M4 ;
        RECT  0 144.528 0.084 144.552 ;
    END
  END c_i[454]
  PIN c_i[455]
    DIRECTION INPUT ;
    USE SIGNAL ;
    PORT
      LAYER M4 ;
        RECT  0 144.672 0.084 144.696 ;
    END
  END c_i[455]
  PIN c_i[456]
    DIRECTION INPUT ;
    USE SIGNAL ;
    PORT
      LAYER M4 ;
        RECT  0 144.816 0.084 144.84 ;
    END
  END c_i[456]
  PIN c_i[457]
    DIRECTION INPUT ;
    USE SIGNAL ;
    PORT
      LAYER M4 ;
        RECT  0 144.96 0.084 144.984 ;
    END
  END c_i[457]
  PIN c_i[458]
    DIRECTION INPUT ;
    USE SIGNAL ;
    PORT
      LAYER M4 ;
        RECT  0 145.104 0.084 145.128 ;
    END
  END c_i[458]
  PIN c_i[459]
    DIRECTION INPUT ;
    USE SIGNAL ;
    PORT
      LAYER M4 ;
        RECT  0 145.248 0.084 145.272 ;
    END
  END c_i[459]
  PIN c_i[45]
    DIRECTION INPUT ;
    USE SIGNAL ;
    PORT
      LAYER M4 ;
        RECT  0 85.632 0.084 85.656 ;
    END
  END c_i[45]
  PIN c_i[460]
    DIRECTION INPUT ;
    USE SIGNAL ;
    PORT
      LAYER M4 ;
        RECT  0 145.392 0.084 145.416 ;
    END
  END c_i[460]
  PIN c_i[461]
    DIRECTION INPUT ;
    USE SIGNAL ;
    PORT
      LAYER M4 ;
        RECT  0 145.536 0.084 145.56 ;
    END
  END c_i[461]
  PIN c_i[462]
    DIRECTION INPUT ;
    USE SIGNAL ;
    PORT
      LAYER M4 ;
        RECT  0 145.68 0.084 145.704 ;
    END
  END c_i[462]
  PIN c_i[463]
    DIRECTION INPUT ;
    USE SIGNAL ;
    PORT
      LAYER M4 ;
        RECT  0 145.824 0.084 145.848 ;
    END
  END c_i[463]
  PIN c_i[464]
    DIRECTION INPUT ;
    USE SIGNAL ;
    PORT
      LAYER M4 ;
        RECT  0 145.968 0.084 145.992 ;
    END
  END c_i[464]
  PIN c_i[465]
    DIRECTION INPUT ;
    USE SIGNAL ;
    PORT
      LAYER M4 ;
        RECT  0 146.112 0.084 146.136 ;
    END
  END c_i[465]
  PIN c_i[466]
    DIRECTION INPUT ;
    USE SIGNAL ;
    PORT
      LAYER M4 ;
        RECT  0 146.256 0.084 146.28 ;
    END
  END c_i[466]
  PIN c_i[467]
    DIRECTION INPUT ;
    USE SIGNAL ;
    PORT
      LAYER M4 ;
        RECT  0 146.4 0.084 146.424 ;
    END
  END c_i[467]
  PIN c_i[468]
    DIRECTION INPUT ;
    USE SIGNAL ;
    PORT
      LAYER M4 ;
        RECT  0 146.544 0.084 146.568 ;
    END
  END c_i[468]
  PIN c_i[469]
    DIRECTION INPUT ;
    USE SIGNAL ;
    PORT
      LAYER M4 ;
        RECT  0 146.688 0.084 146.712 ;
    END
  END c_i[469]
  PIN c_i[46]
    DIRECTION INPUT ;
    USE SIGNAL ;
    PORT
      LAYER M4 ;
        RECT  0 85.776 0.084 85.8 ;
    END
  END c_i[46]
  PIN c_i[470]
    DIRECTION INPUT ;
    USE SIGNAL ;
    PORT
      LAYER M4 ;
        RECT  0 146.832 0.084 146.856 ;
    END
  END c_i[470]
  PIN c_i[471]
    DIRECTION INPUT ;
    USE SIGNAL ;
    PORT
      LAYER M4 ;
        RECT  0 146.976 0.084 147 ;
    END
  END c_i[471]
  PIN c_i[472]
    DIRECTION INPUT ;
    USE SIGNAL ;
    PORT
      LAYER M4 ;
        RECT  0 147.12 0.084 147.144 ;
    END
  END c_i[472]
  PIN c_i[473]
    DIRECTION INPUT ;
    USE SIGNAL ;
    PORT
      LAYER M4 ;
        RECT  0 147.264 0.084 147.288 ;
    END
  END c_i[473]
  PIN c_i[474]
    DIRECTION INPUT ;
    USE SIGNAL ;
    PORT
      LAYER M4 ;
        RECT  0 147.408 0.084 147.432 ;
    END
  END c_i[474]
  PIN c_i[475]
    DIRECTION INPUT ;
    USE SIGNAL ;
    PORT
      LAYER M4 ;
        RECT  0 147.552 0.084 147.576 ;
    END
  END c_i[475]
  PIN c_i[476]
    DIRECTION INPUT ;
    USE SIGNAL ;
    PORT
      LAYER M4 ;
        RECT  0 147.696 0.084 147.72 ;
    END
  END c_i[476]
  PIN c_i[477]
    DIRECTION INPUT ;
    USE SIGNAL ;
    PORT
      LAYER M4 ;
        RECT  0 147.84 0.084 147.864 ;
    END
  END c_i[477]
  PIN c_i[478]
    DIRECTION INPUT ;
    USE SIGNAL ;
    PORT
      LAYER M4 ;
        RECT  0 147.984 0.084 148.008 ;
    END
  END c_i[478]
  PIN c_i[479]
    DIRECTION INPUT ;
    USE SIGNAL ;
    PORT
      LAYER M4 ;
        RECT  0 148.128 0.084 148.152 ;
    END
  END c_i[479]
  PIN c_i[47]
    DIRECTION INPUT ;
    USE SIGNAL ;
    PORT
      LAYER M4 ;
        RECT  0 85.92 0.084 85.944 ;
    END
  END c_i[47]
  PIN c_i[480]
    DIRECTION INPUT ;
    USE SIGNAL ;
    PORT
      LAYER M4 ;
        RECT  0 148.272 0.084 148.296 ;
    END
  END c_i[480]
  PIN c_i[481]
    DIRECTION INPUT ;
    USE SIGNAL ;
    PORT
      LAYER M4 ;
        RECT  0 148.416 0.084 148.44 ;
    END
  END c_i[481]
  PIN c_i[482]
    DIRECTION INPUT ;
    USE SIGNAL ;
    PORT
      LAYER M4 ;
        RECT  0 148.56 0.084 148.584 ;
    END
  END c_i[482]
  PIN c_i[483]
    DIRECTION INPUT ;
    USE SIGNAL ;
    PORT
      LAYER M4 ;
        RECT  0 148.704 0.084 148.728 ;
    END
  END c_i[483]
  PIN c_i[484]
    DIRECTION INPUT ;
    USE SIGNAL ;
    PORT
      LAYER M4 ;
        RECT  0 148.848 0.084 148.872 ;
    END
  END c_i[484]
  PIN c_i[485]
    DIRECTION INPUT ;
    USE SIGNAL ;
    PORT
      LAYER M4 ;
        RECT  0 148.992 0.084 149.016 ;
    END
  END c_i[485]
  PIN c_i[486]
    DIRECTION INPUT ;
    USE SIGNAL ;
    PORT
      LAYER M4 ;
        RECT  0 149.136 0.084 149.16 ;
    END
  END c_i[486]
  PIN c_i[487]
    DIRECTION INPUT ;
    USE SIGNAL ;
    PORT
      LAYER M4 ;
        RECT  0 149.28 0.084 149.304 ;
    END
  END c_i[487]
  PIN c_i[488]
    DIRECTION INPUT ;
    USE SIGNAL ;
    PORT
      LAYER M4 ;
        RECT  0 149.424 0.084 149.448 ;
    END
  END c_i[488]
  PIN c_i[489]
    DIRECTION INPUT ;
    USE SIGNAL ;
    PORT
      LAYER M4 ;
        RECT  0 149.568 0.084 149.592 ;
    END
  END c_i[489]
  PIN c_i[48]
    DIRECTION INPUT ;
    USE SIGNAL ;
    PORT
      LAYER M4 ;
        RECT  0 86.064 0.084 86.088 ;
    END
  END c_i[48]
  PIN c_i[490]
    DIRECTION INPUT ;
    USE SIGNAL ;
    PORT
      LAYER M4 ;
        RECT  0 149.712 0.084 149.736 ;
    END
  END c_i[490]
  PIN c_i[491]
    DIRECTION INPUT ;
    USE SIGNAL ;
    PORT
      LAYER M4 ;
        RECT  0 149.856 0.084 149.88 ;
    END
  END c_i[491]
  PIN c_i[492]
    DIRECTION INPUT ;
    USE SIGNAL ;
    PORT
      LAYER M4 ;
        RECT  0 150 0.084 150.024 ;
    END
  END c_i[492]
  PIN c_i[493]
    DIRECTION INPUT ;
    USE SIGNAL ;
    PORT
      LAYER M4 ;
        RECT  0 150.144 0.084 150.168 ;
    END
  END c_i[493]
  PIN c_i[494]
    DIRECTION INPUT ;
    USE SIGNAL ;
    PORT
      LAYER M4 ;
        RECT  0 150.288 0.084 150.312 ;
    END
  END c_i[494]
  PIN c_i[495]
    DIRECTION INPUT ;
    USE SIGNAL ;
    PORT
      LAYER M4 ;
        RECT  0 150.432 0.084 150.456 ;
    END
  END c_i[495]
  PIN c_i[496]
    DIRECTION INPUT ;
    USE SIGNAL ;
    PORT
      LAYER M4 ;
        RECT  0 150.576 0.084 150.6 ;
    END
  END c_i[496]
  PIN c_i[497]
    DIRECTION INPUT ;
    USE SIGNAL ;
    PORT
      LAYER M4 ;
        RECT  0 150.72 0.084 150.744 ;
    END
  END c_i[497]
  PIN c_i[498]
    DIRECTION INPUT ;
    USE SIGNAL ;
    PORT
      LAYER M4 ;
        RECT  0 150.864 0.084 150.888 ;
    END
  END c_i[498]
  PIN c_i[499]
    DIRECTION INPUT ;
    USE SIGNAL ;
    PORT
      LAYER M4 ;
        RECT  0 151.008 0.084 151.032 ;
    END
  END c_i[499]
  PIN c_i[49]
    DIRECTION INPUT ;
    USE SIGNAL ;
    PORT
      LAYER M4 ;
        RECT  0 86.208 0.084 86.232 ;
    END
  END c_i[49]
  PIN c_i[4]
    DIRECTION INPUT ;
    USE SIGNAL ;
    PORT
      LAYER M4 ;
        RECT  0 79.728 0.084 79.752 ;
    END
  END c_i[4]
  PIN c_i[500]
    DIRECTION INPUT ;
    USE SIGNAL ;
    PORT
      LAYER M4 ;
        RECT  0 151.152 0.084 151.176 ;
    END
  END c_i[500]
  PIN c_i[501]
    DIRECTION INPUT ;
    USE SIGNAL ;
    PORT
      LAYER M4 ;
        RECT  0 151.296 0.084 151.32 ;
    END
  END c_i[501]
  PIN c_i[502]
    DIRECTION INPUT ;
    USE SIGNAL ;
    PORT
      LAYER M4 ;
        RECT  0 151.44 0.084 151.464 ;
    END
  END c_i[502]
  PIN c_i[503]
    DIRECTION INPUT ;
    USE SIGNAL ;
    PORT
      LAYER M4 ;
        RECT  0 151.584 0.084 151.608 ;
    END
  END c_i[503]
  PIN c_i[504]
    DIRECTION INPUT ;
    USE SIGNAL ;
    PORT
      LAYER M4 ;
        RECT  0 151.728 0.084 151.752 ;
    END
  END c_i[504]
  PIN c_i[505]
    DIRECTION INPUT ;
    USE SIGNAL ;
    PORT
      LAYER M4 ;
        RECT  0 151.872 0.084 151.896 ;
    END
  END c_i[505]
  PIN c_i[506]
    DIRECTION INPUT ;
    USE SIGNAL ;
    PORT
      LAYER M4 ;
        RECT  0 152.016 0.084 152.04 ;
    END
  END c_i[506]
  PIN c_i[507]
    DIRECTION INPUT ;
    USE SIGNAL ;
    PORT
      LAYER M4 ;
        RECT  0 152.16 0.084 152.184 ;
    END
  END c_i[507]
  PIN c_i[508]
    DIRECTION INPUT ;
    USE SIGNAL ;
    PORT
      LAYER M4 ;
        RECT  0 152.304 0.084 152.328 ;
    END
  END c_i[508]
  PIN c_i[509]
    DIRECTION INPUT ;
    USE SIGNAL ;
    PORT
      LAYER M4 ;
        RECT  0 152.448 0.084 152.472 ;
    END
  END c_i[509]
  PIN c_i[50]
    DIRECTION INPUT ;
    USE SIGNAL ;
    PORT
      LAYER M4 ;
        RECT  0 86.352 0.084 86.376 ;
    END
  END c_i[50]
  PIN c_i[510]
    DIRECTION INPUT ;
    USE SIGNAL ;
    PORT
      LAYER M4 ;
        RECT  0 152.592 0.084 152.616 ;
    END
  END c_i[510]
  PIN c_i[511]
    DIRECTION INPUT ;
    USE SIGNAL ;
    PORT
      LAYER M4 ;
        RECT  0 152.736 0.084 152.76 ;
    END
  END c_i[511]
  PIN c_i[512]
    DIRECTION INPUT ;
    USE SIGNAL ;
    PORT
      LAYER M4 ;
        RECT  0 152.88 0.084 152.904 ;
    END
  END c_i[512]
  PIN c_i[513]
    DIRECTION INPUT ;
    USE SIGNAL ;
    PORT
      LAYER M4 ;
        RECT  0 153.024 0.084 153.048 ;
    END
  END c_i[513]
  PIN c_i[514]
    DIRECTION INPUT ;
    USE SIGNAL ;
    PORT
      LAYER M4 ;
        RECT  0 153.168 0.084 153.192 ;
    END
  END c_i[514]
  PIN c_i[515]
    DIRECTION INPUT ;
    USE SIGNAL ;
    PORT
      LAYER M4 ;
        RECT  0 153.312 0.084 153.336 ;
    END
  END c_i[515]
  PIN c_i[516]
    DIRECTION INPUT ;
    USE SIGNAL ;
    PORT
      LAYER M4 ;
        RECT  0 153.456 0.084 153.48 ;
    END
  END c_i[516]
  PIN c_i[517]
    DIRECTION INPUT ;
    USE SIGNAL ;
    PORT
      LAYER M4 ;
        RECT  0 153.6 0.084 153.624 ;
    END
  END c_i[517]
  PIN c_i[518]
    DIRECTION INPUT ;
    USE SIGNAL ;
    PORT
      LAYER M4 ;
        RECT  0 153.744 0.084 153.768 ;
    END
  END c_i[518]
  PIN c_i[519]
    DIRECTION INPUT ;
    USE SIGNAL ;
    PORT
      LAYER M4 ;
        RECT  0 153.888 0.084 153.912 ;
    END
  END c_i[519]
  PIN c_i[51]
    DIRECTION INPUT ;
    USE SIGNAL ;
    PORT
      LAYER M4 ;
        RECT  0 86.496 0.084 86.52 ;
    END
  END c_i[51]
  PIN c_i[520]
    DIRECTION INPUT ;
    USE SIGNAL ;
    PORT
      LAYER M4 ;
        RECT  0 154.032 0.084 154.056 ;
    END
  END c_i[520]
  PIN c_i[521]
    DIRECTION INPUT ;
    USE SIGNAL ;
    PORT
      LAYER M4 ;
        RECT  0 154.176 0.084 154.2 ;
    END
  END c_i[521]
  PIN c_i[522]
    DIRECTION INPUT ;
    USE SIGNAL ;
    PORT
      LAYER M4 ;
        RECT  0 154.32 0.084 154.344 ;
    END
  END c_i[522]
  PIN c_i[523]
    DIRECTION INPUT ;
    USE SIGNAL ;
    PORT
      LAYER M4 ;
        RECT  0 154.464 0.084 154.488 ;
    END
  END c_i[523]
  PIN c_i[524]
    DIRECTION INPUT ;
    USE SIGNAL ;
    PORT
      LAYER M4 ;
        RECT  0 154.608 0.084 154.632 ;
    END
  END c_i[524]
  PIN c_i[525]
    DIRECTION INPUT ;
    USE SIGNAL ;
    PORT
      LAYER M4 ;
        RECT  0 154.752 0.084 154.776 ;
    END
  END c_i[525]
  PIN c_i[526]
    DIRECTION INPUT ;
    USE SIGNAL ;
    PORT
      LAYER M4 ;
        RECT  0 154.896 0.084 154.92 ;
    END
  END c_i[526]
  PIN c_i[527]
    DIRECTION INPUT ;
    USE SIGNAL ;
    PORT
      LAYER M4 ;
        RECT  0 155.04 0.084 155.064 ;
    END
  END c_i[527]
  PIN c_i[528]
    DIRECTION INPUT ;
    USE SIGNAL ;
    PORT
      LAYER M4 ;
        RECT  0 155.184 0.084 155.208 ;
    END
  END c_i[528]
  PIN c_i[529]
    DIRECTION INPUT ;
    USE SIGNAL ;
    PORT
      LAYER M4 ;
        RECT  0 155.328 0.084 155.352 ;
    END
  END c_i[529]
  PIN c_i[52]
    DIRECTION INPUT ;
    USE SIGNAL ;
    PORT
      LAYER M4 ;
        RECT  0 86.64 0.084 86.664 ;
    END
  END c_i[52]
  PIN c_i[530]
    DIRECTION INPUT ;
    USE SIGNAL ;
    PORT
      LAYER M4 ;
        RECT  0 155.472 0.084 155.496 ;
    END
  END c_i[530]
  PIN c_i[531]
    DIRECTION INPUT ;
    USE SIGNAL ;
    PORT
      LAYER M4 ;
        RECT  0 155.616 0.084 155.64 ;
    END
  END c_i[531]
  PIN c_i[532]
    DIRECTION INPUT ;
    USE SIGNAL ;
    PORT
      LAYER M4 ;
        RECT  0 155.76 0.084 155.784 ;
    END
  END c_i[532]
  PIN c_i[533]
    DIRECTION INPUT ;
    USE SIGNAL ;
    PORT
      LAYER M4 ;
        RECT  0 155.904 0.084 155.928 ;
    END
  END c_i[533]
  PIN c_i[534]
    DIRECTION INPUT ;
    USE SIGNAL ;
    PORT
      LAYER M4 ;
        RECT  0 156.048 0.084 156.072 ;
    END
  END c_i[534]
  PIN c_i[535]
    DIRECTION INPUT ;
    USE SIGNAL ;
    PORT
      LAYER M4 ;
        RECT  0 156.192 0.084 156.216 ;
    END
  END c_i[535]
  PIN c_i[536]
    DIRECTION INPUT ;
    USE SIGNAL ;
    PORT
      LAYER M4 ;
        RECT  0 156.336 0.084 156.36 ;
    END
  END c_i[536]
  PIN c_i[537]
    DIRECTION INPUT ;
    USE SIGNAL ;
    PORT
      LAYER M4 ;
        RECT  0 156.48 0.084 156.504 ;
    END
  END c_i[537]
  PIN c_i[538]
    DIRECTION INPUT ;
    USE SIGNAL ;
    PORT
      LAYER M4 ;
        RECT  0 156.624 0.084 156.648 ;
    END
  END c_i[538]
  PIN c_i[539]
    DIRECTION INPUT ;
    USE SIGNAL ;
    PORT
      LAYER M4 ;
        RECT  0 156.768 0.084 156.792 ;
    END
  END c_i[539]
  PIN c_i[53]
    DIRECTION INPUT ;
    USE SIGNAL ;
    PORT
      LAYER M4 ;
        RECT  0 86.784 0.084 86.808 ;
    END
  END c_i[53]
  PIN c_i[540]
    DIRECTION INPUT ;
    USE SIGNAL ;
    PORT
      LAYER M4 ;
        RECT  0 156.912 0.084 156.936 ;
    END
  END c_i[540]
  PIN c_i[541]
    DIRECTION INPUT ;
    USE SIGNAL ;
    PORT
      LAYER M4 ;
        RECT  0 157.056 0.084 157.08 ;
    END
  END c_i[541]
  PIN c_i[542]
    DIRECTION INPUT ;
    USE SIGNAL ;
    PORT
      LAYER M4 ;
        RECT  0 157.2 0.084 157.224 ;
    END
  END c_i[542]
  PIN c_i[543]
    DIRECTION INPUT ;
    USE SIGNAL ;
    PORT
      LAYER M4 ;
        RECT  0 157.344 0.084 157.368 ;
    END
  END c_i[543]
  PIN c_i[544]
    DIRECTION INPUT ;
    USE SIGNAL ;
    PORT
      LAYER M4 ;
        RECT  0 157.488 0.084 157.512 ;
    END
  END c_i[544]
  PIN c_i[545]
    DIRECTION INPUT ;
    USE SIGNAL ;
    PORT
      LAYER M4 ;
        RECT  0 157.632 0.084 157.656 ;
    END
  END c_i[545]
  PIN c_i[546]
    DIRECTION INPUT ;
    USE SIGNAL ;
    PORT
      LAYER M4 ;
        RECT  0 157.776 0.084 157.8 ;
    END
  END c_i[546]
  PIN c_i[547]
    DIRECTION INPUT ;
    USE SIGNAL ;
    PORT
      LAYER M4 ;
        RECT  0 157.92 0.084 157.944 ;
    END
  END c_i[547]
  PIN c_i[548]
    DIRECTION INPUT ;
    USE SIGNAL ;
    PORT
      LAYER M4 ;
        RECT  0 158.064 0.084 158.088 ;
    END
  END c_i[548]
  PIN c_i[549]
    DIRECTION INPUT ;
    USE SIGNAL ;
    PORT
      LAYER M4 ;
        RECT  0 158.208 0.084 158.232 ;
    END
  END c_i[549]
  PIN c_i[54]
    DIRECTION INPUT ;
    USE SIGNAL ;
    PORT
      LAYER M4 ;
        RECT  0 86.928 0.084 86.952 ;
    END
  END c_i[54]
  PIN c_i[550]
    DIRECTION INPUT ;
    USE SIGNAL ;
    PORT
      LAYER M4 ;
        RECT  0 158.352 0.084 158.376 ;
    END
  END c_i[550]
  PIN c_i[551]
    DIRECTION INPUT ;
    USE SIGNAL ;
    PORT
      LAYER M4 ;
        RECT  0 158.496 0.084 158.52 ;
    END
  END c_i[551]
  PIN c_i[552]
    DIRECTION INPUT ;
    USE SIGNAL ;
    PORT
      LAYER M4 ;
        RECT  0 158.64 0.084 158.664 ;
    END
  END c_i[552]
  PIN c_i[553]
    DIRECTION INPUT ;
    USE SIGNAL ;
    PORT
      LAYER M4 ;
        RECT  0 158.784 0.084 158.808 ;
    END
  END c_i[553]
  PIN c_i[554]
    DIRECTION INPUT ;
    USE SIGNAL ;
    PORT
      LAYER M4 ;
        RECT  0 158.928 0.084 158.952 ;
    END
  END c_i[554]
  PIN c_i[555]
    DIRECTION INPUT ;
    USE SIGNAL ;
    PORT
      LAYER M4 ;
        RECT  0 159.072 0.084 159.096 ;
    END
  END c_i[555]
  PIN c_i[556]
    DIRECTION INPUT ;
    USE SIGNAL ;
    PORT
      LAYER M4 ;
        RECT  0 159.216 0.084 159.24 ;
    END
  END c_i[556]
  PIN c_i[557]
    DIRECTION INPUT ;
    USE SIGNAL ;
    PORT
      LAYER M4 ;
        RECT  0 159.36 0.084 159.384 ;
    END
  END c_i[557]
  PIN c_i[558]
    DIRECTION INPUT ;
    USE SIGNAL ;
    PORT
      LAYER M4 ;
        RECT  0 159.504 0.084 159.528 ;
    END
  END c_i[558]
  PIN c_i[559]
    DIRECTION INPUT ;
    USE SIGNAL ;
    PORT
      LAYER M4 ;
        RECT  0 159.648 0.084 159.672 ;
    END
  END c_i[559]
  PIN c_i[55]
    DIRECTION INPUT ;
    USE SIGNAL ;
    PORT
      LAYER M4 ;
        RECT  0 87.072 0.084 87.096 ;
    END
  END c_i[55]
  PIN c_i[560]
    DIRECTION INPUT ;
    USE SIGNAL ;
    PORT
      LAYER M4 ;
        RECT  0 159.792 0.084 159.816 ;
    END
  END c_i[560]
  PIN c_i[561]
    DIRECTION INPUT ;
    USE SIGNAL ;
    PORT
      LAYER M4 ;
        RECT  0 159.936 0.084 159.96 ;
    END
  END c_i[561]
  PIN c_i[562]
    DIRECTION INPUT ;
    USE SIGNAL ;
    PORT
      LAYER M4 ;
        RECT  0 160.08 0.084 160.104 ;
    END
  END c_i[562]
  PIN c_i[563]
    DIRECTION INPUT ;
    USE SIGNAL ;
    PORT
      LAYER M4 ;
        RECT  0 160.224 0.084 160.248 ;
    END
  END c_i[563]
  PIN c_i[564]
    DIRECTION INPUT ;
    USE SIGNAL ;
    PORT
      LAYER M4 ;
        RECT  0 160.368 0.084 160.392 ;
    END
  END c_i[564]
  PIN c_i[565]
    DIRECTION INPUT ;
    USE SIGNAL ;
    PORT
      LAYER M4 ;
        RECT  0 160.512 0.084 160.536 ;
    END
  END c_i[565]
  PIN c_i[566]
    DIRECTION INPUT ;
    USE SIGNAL ;
    PORT
      LAYER M4 ;
        RECT  0 160.656 0.084 160.68 ;
    END
  END c_i[566]
  PIN c_i[567]
    DIRECTION INPUT ;
    USE SIGNAL ;
    PORT
      LAYER M4 ;
        RECT  0 160.8 0.084 160.824 ;
    END
  END c_i[567]
  PIN c_i[568]
    DIRECTION INPUT ;
    USE SIGNAL ;
    PORT
      LAYER M4 ;
        RECT  0 160.944 0.084 160.968 ;
    END
  END c_i[568]
  PIN c_i[569]
    DIRECTION INPUT ;
    USE SIGNAL ;
    PORT
      LAYER M4 ;
        RECT  0 161.088 0.084 161.112 ;
    END
  END c_i[569]
  PIN c_i[56]
    DIRECTION INPUT ;
    USE SIGNAL ;
    PORT
      LAYER M4 ;
        RECT  0 87.216 0.084 87.24 ;
    END
  END c_i[56]
  PIN c_i[570]
    DIRECTION INPUT ;
    USE SIGNAL ;
    PORT
      LAYER M4 ;
        RECT  0 161.232 0.084 161.256 ;
    END
  END c_i[570]
  PIN c_i[571]
    DIRECTION INPUT ;
    USE SIGNAL ;
    PORT
      LAYER M4 ;
        RECT  0 161.376 0.084 161.4 ;
    END
  END c_i[571]
  PIN c_i[572]
    DIRECTION INPUT ;
    USE SIGNAL ;
    PORT
      LAYER M4 ;
        RECT  0 161.52 0.084 161.544 ;
    END
  END c_i[572]
  PIN c_i[573]
    DIRECTION INPUT ;
    USE SIGNAL ;
    PORT
      LAYER M4 ;
        RECT  0 161.664 0.084 161.688 ;
    END
  END c_i[573]
  PIN c_i[574]
    DIRECTION INPUT ;
    USE SIGNAL ;
    PORT
      LAYER M4 ;
        RECT  0 161.808 0.084 161.832 ;
    END
  END c_i[574]
  PIN c_i[575]
    DIRECTION INPUT ;
    USE SIGNAL ;
    PORT
      LAYER M4 ;
        RECT  0 161.952 0.084 161.976 ;
    END
  END c_i[575]
  PIN c_i[576]
    DIRECTION INPUT ;
    USE SIGNAL ;
    PORT
      LAYER M4 ;
        RECT  0 162.096 0.084 162.12 ;
    END
  END c_i[576]
  PIN c_i[577]
    DIRECTION INPUT ;
    USE SIGNAL ;
    PORT
      LAYER M4 ;
        RECT  0 162.24 0.084 162.264 ;
    END
  END c_i[577]
  PIN c_i[578]
    DIRECTION INPUT ;
    USE SIGNAL ;
    PORT
      LAYER M4 ;
        RECT  0 162.384 0.084 162.408 ;
    END
  END c_i[578]
  PIN c_i[579]
    DIRECTION INPUT ;
    USE SIGNAL ;
    PORT
      LAYER M4 ;
        RECT  0 162.528 0.084 162.552 ;
    END
  END c_i[579]
  PIN c_i[57]
    DIRECTION INPUT ;
    USE SIGNAL ;
    PORT
      LAYER M4 ;
        RECT  0 87.36 0.084 87.384 ;
    END
  END c_i[57]
  PIN c_i[580]
    DIRECTION INPUT ;
    USE SIGNAL ;
    PORT
      LAYER M4 ;
        RECT  0 162.672 0.084 162.696 ;
    END
  END c_i[580]
  PIN c_i[581]
    DIRECTION INPUT ;
    USE SIGNAL ;
    PORT
      LAYER M4 ;
        RECT  0 162.816 0.084 162.84 ;
    END
  END c_i[581]
  PIN c_i[582]
    DIRECTION INPUT ;
    USE SIGNAL ;
    PORT
      LAYER M4 ;
        RECT  0 162.96 0.084 162.984 ;
    END
  END c_i[582]
  PIN c_i[583]
    DIRECTION INPUT ;
    USE SIGNAL ;
    PORT
      LAYER M4 ;
        RECT  0 163.104 0.084 163.128 ;
    END
  END c_i[583]
  PIN c_i[584]
    DIRECTION INPUT ;
    USE SIGNAL ;
    PORT
      LAYER M4 ;
        RECT  0 163.248 0.084 163.272 ;
    END
  END c_i[584]
  PIN c_i[585]
    DIRECTION INPUT ;
    USE SIGNAL ;
    PORT
      LAYER M4 ;
        RECT  0 163.392 0.084 163.416 ;
    END
  END c_i[585]
  PIN c_i[586]
    DIRECTION INPUT ;
    USE SIGNAL ;
    PORT
      LAYER M4 ;
        RECT  0 163.536 0.084 163.56 ;
    END
  END c_i[586]
  PIN c_i[587]
    DIRECTION INPUT ;
    USE SIGNAL ;
    PORT
      LAYER M4 ;
        RECT  0 163.68 0.084 163.704 ;
    END
  END c_i[587]
  PIN c_i[588]
    DIRECTION INPUT ;
    USE SIGNAL ;
    PORT
      LAYER M4 ;
        RECT  0 163.824 0.084 163.848 ;
    END
  END c_i[588]
  PIN c_i[589]
    DIRECTION INPUT ;
    USE SIGNAL ;
    PORT
      LAYER M4 ;
        RECT  0 163.968 0.084 163.992 ;
    END
  END c_i[589]
  PIN c_i[58]
    DIRECTION INPUT ;
    USE SIGNAL ;
    PORT
      LAYER M4 ;
        RECT  0 87.504 0.084 87.528 ;
    END
  END c_i[58]
  PIN c_i[590]
    DIRECTION INPUT ;
    USE SIGNAL ;
    PORT
      LAYER M4 ;
        RECT  0 164.112 0.084 164.136 ;
    END
  END c_i[590]
  PIN c_i[591]
    DIRECTION INPUT ;
    USE SIGNAL ;
    PORT
      LAYER M4 ;
        RECT  0 164.256 0.084 164.28 ;
    END
  END c_i[591]
  PIN c_i[592]
    DIRECTION INPUT ;
    USE SIGNAL ;
    PORT
      LAYER M4 ;
        RECT  0 164.4 0.084 164.424 ;
    END
  END c_i[592]
  PIN c_i[593]
    DIRECTION INPUT ;
    USE SIGNAL ;
    PORT
      LAYER M4 ;
        RECT  0 164.544 0.084 164.568 ;
    END
  END c_i[593]
  PIN c_i[594]
    DIRECTION INPUT ;
    USE SIGNAL ;
    PORT
      LAYER M4 ;
        RECT  0 164.688 0.084 164.712 ;
    END
  END c_i[594]
  PIN c_i[595]
    DIRECTION INPUT ;
    USE SIGNAL ;
    PORT
      LAYER M4 ;
        RECT  0 164.832 0.084 164.856 ;
    END
  END c_i[595]
  PIN c_i[596]
    DIRECTION INPUT ;
    USE SIGNAL ;
    PORT
      LAYER M4 ;
        RECT  0 164.976 0.084 165 ;
    END
  END c_i[596]
  PIN c_i[597]
    DIRECTION INPUT ;
    USE SIGNAL ;
    PORT
      LAYER M4 ;
        RECT  0 165.12 0.084 165.144 ;
    END
  END c_i[597]
  PIN c_i[598]
    DIRECTION INPUT ;
    USE SIGNAL ;
    PORT
      LAYER M4 ;
        RECT  0 165.264 0.084 165.288 ;
    END
  END c_i[598]
  PIN c_i[599]
    DIRECTION INPUT ;
    USE SIGNAL ;
    PORT
      LAYER M4 ;
        RECT  0 165.408 0.084 165.432 ;
    END
  END c_i[599]
  PIN c_i[59]
    DIRECTION INPUT ;
    USE SIGNAL ;
    PORT
      LAYER M4 ;
        RECT  0 87.648 0.084 87.672 ;
    END
  END c_i[59]
  PIN c_i[5]
    DIRECTION INPUT ;
    USE SIGNAL ;
    PORT
      LAYER M4 ;
        RECT  0 79.872 0.084 79.896 ;
    END
  END c_i[5]
  PIN c_i[600]
    DIRECTION INPUT ;
    USE SIGNAL ;
    PORT
      LAYER M4 ;
        RECT  0 165.552 0.084 165.576 ;
    END
  END c_i[600]
  PIN c_i[601]
    DIRECTION INPUT ;
    USE SIGNAL ;
    PORT
      LAYER M4 ;
        RECT  0 165.696 0.084 165.72 ;
    END
  END c_i[601]
  PIN c_i[602]
    DIRECTION INPUT ;
    USE SIGNAL ;
    PORT
      LAYER M4 ;
        RECT  0 165.84 0.084 165.864 ;
    END
  END c_i[602]
  PIN c_i[603]
    DIRECTION INPUT ;
    USE SIGNAL ;
    PORT
      LAYER M4 ;
        RECT  0 165.984 0.084 166.008 ;
    END
  END c_i[603]
  PIN c_i[604]
    DIRECTION INPUT ;
    USE SIGNAL ;
    PORT
      LAYER M4 ;
        RECT  0 166.128 0.084 166.152 ;
    END
  END c_i[604]
  PIN c_i[605]
    DIRECTION INPUT ;
    USE SIGNAL ;
    PORT
      LAYER M4 ;
        RECT  0 166.272 0.084 166.296 ;
    END
  END c_i[605]
  PIN c_i[606]
    DIRECTION INPUT ;
    USE SIGNAL ;
    PORT
      LAYER M4 ;
        RECT  0 166.416 0.084 166.44 ;
    END
  END c_i[606]
  PIN c_i[607]
    DIRECTION INPUT ;
    USE SIGNAL ;
    PORT
      LAYER M4 ;
        RECT  0 166.56 0.084 166.584 ;
    END
  END c_i[607]
  PIN c_i[608]
    DIRECTION INPUT ;
    USE SIGNAL ;
    PORT
      LAYER M4 ;
        RECT  0 166.704 0.084 166.728 ;
    END
  END c_i[608]
  PIN c_i[609]
    DIRECTION INPUT ;
    USE SIGNAL ;
    PORT
      LAYER M4 ;
        RECT  0 166.848 0.084 166.872 ;
    END
  END c_i[609]
  PIN c_i[60]
    DIRECTION INPUT ;
    USE SIGNAL ;
    PORT
      LAYER M4 ;
        RECT  0 87.792 0.084 87.816 ;
    END
  END c_i[60]
  PIN c_i[610]
    DIRECTION INPUT ;
    USE SIGNAL ;
    PORT
      LAYER M4 ;
        RECT  0 166.992 0.084 167.016 ;
    END
  END c_i[610]
  PIN c_i[611]
    DIRECTION INPUT ;
    USE SIGNAL ;
    PORT
      LAYER M4 ;
        RECT  0 167.136 0.084 167.16 ;
    END
  END c_i[611]
  PIN c_i[612]
    DIRECTION INPUT ;
    USE SIGNAL ;
    PORT
      LAYER M4 ;
        RECT  0 167.28 0.084 167.304 ;
    END
  END c_i[612]
  PIN c_i[613]
    DIRECTION INPUT ;
    USE SIGNAL ;
    PORT
      LAYER M4 ;
        RECT  0 167.424 0.084 167.448 ;
    END
  END c_i[613]
  PIN c_i[614]
    DIRECTION INPUT ;
    USE SIGNAL ;
    PORT
      LAYER M4 ;
        RECT  0 167.568 0.084 167.592 ;
    END
  END c_i[614]
  PIN c_i[615]
    DIRECTION INPUT ;
    USE SIGNAL ;
    PORT
      LAYER M4 ;
        RECT  0 167.712 0.084 167.736 ;
    END
  END c_i[615]
  PIN c_i[616]
    DIRECTION INPUT ;
    USE SIGNAL ;
    PORT
      LAYER M4 ;
        RECT  0 167.856 0.084 167.88 ;
    END
  END c_i[616]
  PIN c_i[617]
    DIRECTION INPUT ;
    USE SIGNAL ;
    PORT
      LAYER M4 ;
        RECT  0 168 0.084 168.024 ;
    END
  END c_i[617]
  PIN c_i[618]
    DIRECTION INPUT ;
    USE SIGNAL ;
    PORT
      LAYER M4 ;
        RECT  0 168.144 0.084 168.168 ;
    END
  END c_i[618]
  PIN c_i[619]
    DIRECTION INPUT ;
    USE SIGNAL ;
    PORT
      LAYER M4 ;
        RECT  0 168.288 0.084 168.312 ;
    END
  END c_i[619]
  PIN c_i[61]
    DIRECTION INPUT ;
    USE SIGNAL ;
    PORT
      LAYER M4 ;
        RECT  0 87.936 0.084 87.96 ;
    END
  END c_i[61]
  PIN c_i[620]
    DIRECTION INPUT ;
    USE SIGNAL ;
    PORT
      LAYER M4 ;
        RECT  0 168.432 0.084 168.456 ;
    END
  END c_i[620]
  PIN c_i[621]
    DIRECTION INPUT ;
    USE SIGNAL ;
    PORT
      LAYER M4 ;
        RECT  0 168.576 0.084 168.6 ;
    END
  END c_i[621]
  PIN c_i[622]
    DIRECTION INPUT ;
    USE SIGNAL ;
    PORT
      LAYER M4 ;
        RECT  0 168.72 0.084 168.744 ;
    END
  END c_i[622]
  PIN c_i[623]
    DIRECTION INPUT ;
    USE SIGNAL ;
    PORT
      LAYER M4 ;
        RECT  0 168.864 0.084 168.888 ;
    END
  END c_i[623]
  PIN c_i[624]
    DIRECTION INPUT ;
    USE SIGNAL ;
    PORT
      LAYER M4 ;
        RECT  0 169.008 0.084 169.032 ;
    END
  END c_i[624]
  PIN c_i[625]
    DIRECTION INPUT ;
    USE SIGNAL ;
    PORT
      LAYER M4 ;
        RECT  0 169.152 0.084 169.176 ;
    END
  END c_i[625]
  PIN c_i[626]
    DIRECTION INPUT ;
    USE SIGNAL ;
    PORT
      LAYER M4 ;
        RECT  0 169.296 0.084 169.32 ;
    END
  END c_i[626]
  PIN c_i[627]
    DIRECTION INPUT ;
    USE SIGNAL ;
    PORT
      LAYER M4 ;
        RECT  0 169.44 0.084 169.464 ;
    END
  END c_i[627]
  PIN c_i[628]
    DIRECTION INPUT ;
    USE SIGNAL ;
    PORT
      LAYER M4 ;
        RECT  0 169.584 0.084 169.608 ;
    END
  END c_i[628]
  PIN c_i[629]
    DIRECTION INPUT ;
    USE SIGNAL ;
    PORT
      LAYER M4 ;
        RECT  0 169.728 0.084 169.752 ;
    END
  END c_i[629]
  PIN c_i[62]
    DIRECTION INPUT ;
    USE SIGNAL ;
    PORT
      LAYER M4 ;
        RECT  0 88.08 0.084 88.104 ;
    END
  END c_i[62]
  PIN c_i[630]
    DIRECTION INPUT ;
    USE SIGNAL ;
    PORT
      LAYER M4 ;
        RECT  0 169.872 0.084 169.896 ;
    END
  END c_i[630]
  PIN c_i[631]
    DIRECTION INPUT ;
    USE SIGNAL ;
    PORT
      LAYER M4 ;
        RECT  0 170.016 0.084 170.04 ;
    END
  END c_i[631]
  PIN c_i[632]
    DIRECTION INPUT ;
    USE SIGNAL ;
    PORT
      LAYER M4 ;
        RECT  0 170.16 0.084 170.184 ;
    END
  END c_i[632]
  PIN c_i[633]
    DIRECTION INPUT ;
    USE SIGNAL ;
    PORT
      LAYER M4 ;
        RECT  0 170.304 0.084 170.328 ;
    END
  END c_i[633]
  PIN c_i[634]
    DIRECTION INPUT ;
    USE SIGNAL ;
    PORT
      LAYER M4 ;
        RECT  0 170.448 0.084 170.472 ;
    END
  END c_i[634]
  PIN c_i[635]
    DIRECTION INPUT ;
    USE SIGNAL ;
    PORT
      LAYER M4 ;
        RECT  0 170.592 0.084 170.616 ;
    END
  END c_i[635]
  PIN c_i[636]
    DIRECTION INPUT ;
    USE SIGNAL ;
    PORT
      LAYER M4 ;
        RECT  0 170.736 0.084 170.76 ;
    END
  END c_i[636]
  PIN c_i[637]
    DIRECTION INPUT ;
    USE SIGNAL ;
    PORT
      LAYER M4 ;
        RECT  0 170.88 0.084 170.904 ;
    END
  END c_i[637]
  PIN c_i[638]
    DIRECTION INPUT ;
    USE SIGNAL ;
    PORT
      LAYER M4 ;
        RECT  0 171.024 0.084 171.048 ;
    END
  END c_i[638]
  PIN c_i[639]
    DIRECTION INPUT ;
    USE SIGNAL ;
    PORT
      LAYER M4 ;
        RECT  0 171.168 0.084 171.192 ;
    END
  END c_i[639]
  PIN c_i[63]
    DIRECTION INPUT ;
    USE SIGNAL ;
    PORT
      LAYER M4 ;
        RECT  0 88.224 0.084 88.248 ;
    END
  END c_i[63]
  PIN c_i[640]
    DIRECTION INPUT ;
    USE SIGNAL ;
    PORT
      LAYER M4 ;
        RECT  0 171.312 0.084 171.336 ;
    END
  END c_i[640]
  PIN c_i[641]
    DIRECTION INPUT ;
    USE SIGNAL ;
    PORT
      LAYER M4 ;
        RECT  0 171.456 0.084 171.48 ;
    END
  END c_i[641]
  PIN c_i[642]
    DIRECTION INPUT ;
    USE SIGNAL ;
    PORT
      LAYER M4 ;
        RECT  0 171.6 0.084 171.624 ;
    END
  END c_i[642]
  PIN c_i[643]
    DIRECTION INPUT ;
    USE SIGNAL ;
    PORT
      LAYER M4 ;
        RECT  0 171.744 0.084 171.768 ;
    END
  END c_i[643]
  PIN c_i[644]
    DIRECTION INPUT ;
    USE SIGNAL ;
    PORT
      LAYER M4 ;
        RECT  0 171.888 0.084 171.912 ;
    END
  END c_i[644]
  PIN c_i[645]
    DIRECTION INPUT ;
    USE SIGNAL ;
    PORT
      LAYER M4 ;
        RECT  0 172.032 0.084 172.056 ;
    END
  END c_i[645]
  PIN c_i[646]
    DIRECTION INPUT ;
    USE SIGNAL ;
    PORT
      LAYER M4 ;
        RECT  0 172.176 0.084 172.2 ;
    END
  END c_i[646]
  PIN c_i[647]
    DIRECTION INPUT ;
    USE SIGNAL ;
    PORT
      LAYER M4 ;
        RECT  0 172.32 0.084 172.344 ;
    END
  END c_i[647]
  PIN c_i[648]
    DIRECTION INPUT ;
    USE SIGNAL ;
    PORT
      LAYER M4 ;
        RECT  0 172.464 0.084 172.488 ;
    END
  END c_i[648]
  PIN c_i[649]
    DIRECTION INPUT ;
    USE SIGNAL ;
    PORT
      LAYER M4 ;
        RECT  0 172.608 0.084 172.632 ;
    END
  END c_i[649]
  PIN c_i[64]
    DIRECTION INPUT ;
    USE SIGNAL ;
    PORT
      LAYER M4 ;
        RECT  0 88.368 0.084 88.392 ;
    END
  END c_i[64]
  PIN c_i[650]
    DIRECTION INPUT ;
    USE SIGNAL ;
    PORT
      LAYER M4 ;
        RECT  0 172.752 0.084 172.776 ;
    END
  END c_i[650]
  PIN c_i[651]
    DIRECTION INPUT ;
    USE SIGNAL ;
    PORT
      LAYER M4 ;
        RECT  0 172.896 0.084 172.92 ;
    END
  END c_i[651]
  PIN c_i[652]
    DIRECTION INPUT ;
    USE SIGNAL ;
    PORT
      LAYER M4 ;
        RECT  0 173.04 0.084 173.064 ;
    END
  END c_i[652]
  PIN c_i[653]
    DIRECTION INPUT ;
    USE SIGNAL ;
    PORT
      LAYER M4 ;
        RECT  0 173.184 0.084 173.208 ;
    END
  END c_i[653]
  PIN c_i[654]
    DIRECTION INPUT ;
    USE SIGNAL ;
    PORT
      LAYER M4 ;
        RECT  0 173.328 0.084 173.352 ;
    END
  END c_i[654]
  PIN c_i[655]
    DIRECTION INPUT ;
    USE SIGNAL ;
    PORT
      LAYER M4 ;
        RECT  0 173.472 0.084 173.496 ;
    END
  END c_i[655]
  PIN c_i[656]
    DIRECTION INPUT ;
    USE SIGNAL ;
    PORT
      LAYER M4 ;
        RECT  0 173.616 0.084 173.64 ;
    END
  END c_i[656]
  PIN c_i[657]
    DIRECTION INPUT ;
    USE SIGNAL ;
    PORT
      LAYER M4 ;
        RECT  0 173.76 0.084 173.784 ;
    END
  END c_i[657]
  PIN c_i[658]
    DIRECTION INPUT ;
    USE SIGNAL ;
    PORT
      LAYER M4 ;
        RECT  0 173.904 0.084 173.928 ;
    END
  END c_i[658]
  PIN c_i[659]
    DIRECTION INPUT ;
    USE SIGNAL ;
    PORT
      LAYER M4 ;
        RECT  0 174.048 0.084 174.072 ;
    END
  END c_i[659]
  PIN c_i[65]
    DIRECTION INPUT ;
    USE SIGNAL ;
    PORT
      LAYER M4 ;
        RECT  0 88.512 0.084 88.536 ;
    END
  END c_i[65]
  PIN c_i[660]
    DIRECTION INPUT ;
    USE SIGNAL ;
    PORT
      LAYER M4 ;
        RECT  0 174.192 0.084 174.216 ;
    END
  END c_i[660]
  PIN c_i[661]
    DIRECTION INPUT ;
    USE SIGNAL ;
    PORT
      LAYER M4 ;
        RECT  0 174.336 0.084 174.36 ;
    END
  END c_i[661]
  PIN c_i[662]
    DIRECTION INPUT ;
    USE SIGNAL ;
    PORT
      LAYER M4 ;
        RECT  0 174.48 0.084 174.504 ;
    END
  END c_i[662]
  PIN c_i[663]
    DIRECTION INPUT ;
    USE SIGNAL ;
    PORT
      LAYER M4 ;
        RECT  0 174.624 0.084 174.648 ;
    END
  END c_i[663]
  PIN c_i[664]
    DIRECTION INPUT ;
    USE SIGNAL ;
    PORT
      LAYER M4 ;
        RECT  0 174.768 0.084 174.792 ;
    END
  END c_i[664]
  PIN c_i[665]
    DIRECTION INPUT ;
    USE SIGNAL ;
    PORT
      LAYER M4 ;
        RECT  0 174.912 0.084 174.936 ;
    END
  END c_i[665]
  PIN c_i[666]
    DIRECTION INPUT ;
    USE SIGNAL ;
    PORT
      LAYER M4 ;
        RECT  0 175.056 0.084 175.08 ;
    END
  END c_i[666]
  PIN c_i[667]
    DIRECTION INPUT ;
    USE SIGNAL ;
    PORT
      LAYER M4 ;
        RECT  0 175.2 0.084 175.224 ;
    END
  END c_i[667]
  PIN c_i[668]
    DIRECTION INPUT ;
    USE SIGNAL ;
    PORT
      LAYER M4 ;
        RECT  0 175.344 0.084 175.368 ;
    END
  END c_i[668]
  PIN c_i[669]
    DIRECTION INPUT ;
    USE SIGNAL ;
    PORT
      LAYER M4 ;
        RECT  0 175.488 0.084 175.512 ;
    END
  END c_i[669]
  PIN c_i[66]
    DIRECTION INPUT ;
    USE SIGNAL ;
    PORT
      LAYER M4 ;
        RECT  0 88.656 0.084 88.68 ;
    END
  END c_i[66]
  PIN c_i[670]
    DIRECTION INPUT ;
    USE SIGNAL ;
    PORT
      LAYER M4 ;
        RECT  0 175.632 0.084 175.656 ;
    END
  END c_i[670]
  PIN c_i[671]
    DIRECTION INPUT ;
    USE SIGNAL ;
    PORT
      LAYER M4 ;
        RECT  0 175.776 0.084 175.8 ;
    END
  END c_i[671]
  PIN c_i[672]
    DIRECTION INPUT ;
    USE SIGNAL ;
    PORT
      LAYER M4 ;
        RECT  0 175.92 0.084 175.944 ;
    END
  END c_i[672]
  PIN c_i[673]
    DIRECTION INPUT ;
    USE SIGNAL ;
    PORT
      LAYER M4 ;
        RECT  0 176.064 0.084 176.088 ;
    END
  END c_i[673]
  PIN c_i[674]
    DIRECTION INPUT ;
    USE SIGNAL ;
    PORT
      LAYER M4 ;
        RECT  0 176.208 0.084 176.232 ;
    END
  END c_i[674]
  PIN c_i[675]
    DIRECTION INPUT ;
    USE SIGNAL ;
    PORT
      LAYER M4 ;
        RECT  0 176.352 0.084 176.376 ;
    END
  END c_i[675]
  PIN c_i[676]
    DIRECTION INPUT ;
    USE SIGNAL ;
    PORT
      LAYER M4 ;
        RECT  0 176.496 0.084 176.52 ;
    END
  END c_i[676]
  PIN c_i[677]
    DIRECTION INPUT ;
    USE SIGNAL ;
    PORT
      LAYER M4 ;
        RECT  0 176.64 0.084 176.664 ;
    END
  END c_i[677]
  PIN c_i[678]
    DIRECTION INPUT ;
    USE SIGNAL ;
    PORT
      LAYER M4 ;
        RECT  0 176.784 0.084 176.808 ;
    END
  END c_i[678]
  PIN c_i[679]
    DIRECTION INPUT ;
    USE SIGNAL ;
    PORT
      LAYER M4 ;
        RECT  0 176.928 0.084 176.952 ;
    END
  END c_i[679]
  PIN c_i[67]
    DIRECTION INPUT ;
    USE SIGNAL ;
    PORT
      LAYER M4 ;
        RECT  0 88.8 0.084 88.824 ;
    END
  END c_i[67]
  PIN c_i[680]
    DIRECTION INPUT ;
    USE SIGNAL ;
    PORT
      LAYER M4 ;
        RECT  0 177.072 0.084 177.096 ;
    END
  END c_i[680]
  PIN c_i[681]
    DIRECTION INPUT ;
    USE SIGNAL ;
    PORT
      LAYER M4 ;
        RECT  0 177.216 0.084 177.24 ;
    END
  END c_i[681]
  PIN c_i[682]
    DIRECTION INPUT ;
    USE SIGNAL ;
    PORT
      LAYER M4 ;
        RECT  0 177.36 0.084 177.384 ;
    END
  END c_i[682]
  PIN c_i[683]
    DIRECTION INPUT ;
    USE SIGNAL ;
    PORT
      LAYER M4 ;
        RECT  0 177.504 0.084 177.528 ;
    END
  END c_i[683]
  PIN c_i[684]
    DIRECTION INPUT ;
    USE SIGNAL ;
    PORT
      LAYER M4 ;
        RECT  0 177.648 0.084 177.672 ;
    END
  END c_i[684]
  PIN c_i[685]
    DIRECTION INPUT ;
    USE SIGNAL ;
    PORT
      LAYER M4 ;
        RECT  0 177.792 0.084 177.816 ;
    END
  END c_i[685]
  PIN c_i[686]
    DIRECTION INPUT ;
    USE SIGNAL ;
    PORT
      LAYER M4 ;
        RECT  0 177.936 0.084 177.96 ;
    END
  END c_i[686]
  PIN c_i[687]
    DIRECTION INPUT ;
    USE SIGNAL ;
    PORT
      LAYER M4 ;
        RECT  0 178.08 0.084 178.104 ;
    END
  END c_i[687]
  PIN c_i[688]
    DIRECTION INPUT ;
    USE SIGNAL ;
    PORT
      LAYER M4 ;
        RECT  0 178.224 0.084 178.248 ;
    END
  END c_i[688]
  PIN c_i[689]
    DIRECTION INPUT ;
    USE SIGNAL ;
    PORT
      LAYER M4 ;
        RECT  0 178.368 0.084 178.392 ;
    END
  END c_i[689]
  PIN c_i[68]
    DIRECTION INPUT ;
    USE SIGNAL ;
    PORT
      LAYER M4 ;
        RECT  0 88.944 0.084 88.968 ;
    END
  END c_i[68]
  PIN c_i[690]
    DIRECTION INPUT ;
    USE SIGNAL ;
    PORT
      LAYER M4 ;
        RECT  0 178.512 0.084 178.536 ;
    END
  END c_i[690]
  PIN c_i[691]
    DIRECTION INPUT ;
    USE SIGNAL ;
    PORT
      LAYER M4 ;
        RECT  0 178.656 0.084 178.68 ;
    END
  END c_i[691]
  PIN c_i[692]
    DIRECTION INPUT ;
    USE SIGNAL ;
    PORT
      LAYER M4 ;
        RECT  0 178.8 0.084 178.824 ;
    END
  END c_i[692]
  PIN c_i[693]
    DIRECTION INPUT ;
    USE SIGNAL ;
    PORT
      LAYER M4 ;
        RECT  0 178.944 0.084 178.968 ;
    END
  END c_i[693]
  PIN c_i[694]
    DIRECTION INPUT ;
    USE SIGNAL ;
    PORT
      LAYER M4 ;
        RECT  0 179.088 0.084 179.112 ;
    END
  END c_i[694]
  PIN c_i[695]
    DIRECTION INPUT ;
    USE SIGNAL ;
    PORT
      LAYER M4 ;
        RECT  0 179.232 0.084 179.256 ;
    END
  END c_i[695]
  PIN c_i[696]
    DIRECTION INPUT ;
    USE SIGNAL ;
    PORT
      LAYER M4 ;
        RECT  0 179.376 0.084 179.4 ;
    END
  END c_i[696]
  PIN c_i[697]
    DIRECTION INPUT ;
    USE SIGNAL ;
    PORT
      LAYER M4 ;
        RECT  0 179.52 0.084 179.544 ;
    END
  END c_i[697]
  PIN c_i[698]
    DIRECTION INPUT ;
    USE SIGNAL ;
    PORT
      LAYER M4 ;
        RECT  0 179.664 0.084 179.688 ;
    END
  END c_i[698]
  PIN c_i[699]
    DIRECTION INPUT ;
    USE SIGNAL ;
    PORT
      LAYER M4 ;
        RECT  0 179.808 0.084 179.832 ;
    END
  END c_i[699]
  PIN c_i[69]
    DIRECTION INPUT ;
    USE SIGNAL ;
    PORT
      LAYER M4 ;
        RECT  0 89.088 0.084 89.112 ;
    END
  END c_i[69]
  PIN c_i[6]
    DIRECTION INPUT ;
    USE SIGNAL ;
    PORT
      LAYER M4 ;
        RECT  0 80.016 0.084 80.04 ;
    END
  END c_i[6]
  PIN c_i[700]
    DIRECTION INPUT ;
    USE SIGNAL ;
    PORT
      LAYER M4 ;
        RECT  0 179.952 0.084 179.976 ;
    END
  END c_i[700]
  PIN c_i[701]
    DIRECTION INPUT ;
    USE SIGNAL ;
    PORT
      LAYER M4 ;
        RECT  0 180.096 0.084 180.12 ;
    END
  END c_i[701]
  PIN c_i[702]
    DIRECTION INPUT ;
    USE SIGNAL ;
    PORT
      LAYER M4 ;
        RECT  0 180.24 0.084 180.264 ;
    END
  END c_i[702]
  PIN c_i[703]
    DIRECTION INPUT ;
    USE SIGNAL ;
    PORT
      LAYER M4 ;
        RECT  0 180.384 0.084 180.408 ;
    END
  END c_i[703]
  PIN c_i[704]
    DIRECTION INPUT ;
    USE SIGNAL ;
    PORT
      LAYER M4 ;
        RECT  0 180.528 0.084 180.552 ;
    END
  END c_i[704]
  PIN c_i[705]
    DIRECTION INPUT ;
    USE SIGNAL ;
    PORT
      LAYER M4 ;
        RECT  0 180.672 0.084 180.696 ;
    END
  END c_i[705]
  PIN c_i[706]
    DIRECTION INPUT ;
    USE SIGNAL ;
    PORT
      LAYER M4 ;
        RECT  0 180.816 0.084 180.84 ;
    END
  END c_i[706]
  PIN c_i[707]
    DIRECTION INPUT ;
    USE SIGNAL ;
    PORT
      LAYER M4 ;
        RECT  0 180.96 0.084 180.984 ;
    END
  END c_i[707]
  PIN c_i[708]
    DIRECTION INPUT ;
    USE SIGNAL ;
    PORT
      LAYER M4 ;
        RECT  0 181.104 0.084 181.128 ;
    END
  END c_i[708]
  PIN c_i[709]
    DIRECTION INPUT ;
    USE SIGNAL ;
    PORT
      LAYER M4 ;
        RECT  0 181.248 0.084 181.272 ;
    END
  END c_i[709]
  PIN c_i[70]
    DIRECTION INPUT ;
    USE SIGNAL ;
    PORT
      LAYER M4 ;
        RECT  0 89.232 0.084 89.256 ;
    END
  END c_i[70]
  PIN c_i[710]
    DIRECTION INPUT ;
    USE SIGNAL ;
    PORT
      LAYER M4 ;
        RECT  0 181.392 0.084 181.416 ;
    END
  END c_i[710]
  PIN c_i[711]
    DIRECTION INPUT ;
    USE SIGNAL ;
    PORT
      LAYER M4 ;
        RECT  0 181.536 0.084 181.56 ;
    END
  END c_i[711]
  PIN c_i[712]
    DIRECTION INPUT ;
    USE SIGNAL ;
    PORT
      LAYER M4 ;
        RECT  0 181.68 0.084 181.704 ;
    END
  END c_i[712]
  PIN c_i[713]
    DIRECTION INPUT ;
    USE SIGNAL ;
    PORT
      LAYER M4 ;
        RECT  0 181.824 0.084 181.848 ;
    END
  END c_i[713]
  PIN c_i[714]
    DIRECTION INPUT ;
    USE SIGNAL ;
    PORT
      LAYER M4 ;
        RECT  0 181.968 0.084 181.992 ;
    END
  END c_i[714]
  PIN c_i[715]
    DIRECTION INPUT ;
    USE SIGNAL ;
    PORT
      LAYER M4 ;
        RECT  0 182.112 0.084 182.136 ;
    END
  END c_i[715]
  PIN c_i[716]
    DIRECTION INPUT ;
    USE SIGNAL ;
    PORT
      LAYER M4 ;
        RECT  0 182.256 0.084 182.28 ;
    END
  END c_i[716]
  PIN c_i[717]
    DIRECTION INPUT ;
    USE SIGNAL ;
    PORT
      LAYER M4 ;
        RECT  0 182.4 0.084 182.424 ;
    END
  END c_i[717]
  PIN c_i[718]
    DIRECTION INPUT ;
    USE SIGNAL ;
    PORT
      LAYER M4 ;
        RECT  0 182.544 0.084 182.568 ;
    END
  END c_i[718]
  PIN c_i[719]
    DIRECTION INPUT ;
    USE SIGNAL ;
    PORT
      LAYER M4 ;
        RECT  0 182.688 0.084 182.712 ;
    END
  END c_i[719]
  PIN c_i[71]
    DIRECTION INPUT ;
    USE SIGNAL ;
    PORT
      LAYER M4 ;
        RECT  0 89.376 0.084 89.4 ;
    END
  END c_i[71]
  PIN c_i[720]
    DIRECTION INPUT ;
    USE SIGNAL ;
    PORT
      LAYER M4 ;
        RECT  0 182.832 0.084 182.856 ;
    END
  END c_i[720]
  PIN c_i[721]
    DIRECTION INPUT ;
    USE SIGNAL ;
    PORT
      LAYER M4 ;
        RECT  0 182.976 0.084 183 ;
    END
  END c_i[721]
  PIN c_i[722]
    DIRECTION INPUT ;
    USE SIGNAL ;
    PORT
      LAYER M4 ;
        RECT  0 183.12 0.084 183.144 ;
    END
  END c_i[722]
  PIN c_i[723]
    DIRECTION INPUT ;
    USE SIGNAL ;
    PORT
      LAYER M4 ;
        RECT  0 183.264 0.084 183.288 ;
    END
  END c_i[723]
  PIN c_i[724]
    DIRECTION INPUT ;
    USE SIGNAL ;
    PORT
      LAYER M4 ;
        RECT  0 183.408 0.084 183.432 ;
    END
  END c_i[724]
  PIN c_i[725]
    DIRECTION INPUT ;
    USE SIGNAL ;
    PORT
      LAYER M4 ;
        RECT  0 183.552 0.084 183.576 ;
    END
  END c_i[725]
  PIN c_i[726]
    DIRECTION INPUT ;
    USE SIGNAL ;
    PORT
      LAYER M4 ;
        RECT  0 183.696 0.084 183.72 ;
    END
  END c_i[726]
  PIN c_i[727]
    DIRECTION INPUT ;
    USE SIGNAL ;
    PORT
      LAYER M4 ;
        RECT  0 183.84 0.084 183.864 ;
    END
  END c_i[727]
  PIN c_i[728]
    DIRECTION INPUT ;
    USE SIGNAL ;
    PORT
      LAYER M4 ;
        RECT  0 183.984 0.084 184.008 ;
    END
  END c_i[728]
  PIN c_i[729]
    DIRECTION INPUT ;
    USE SIGNAL ;
    PORT
      LAYER M4 ;
        RECT  0 184.128 0.084 184.152 ;
    END
  END c_i[729]
  PIN c_i[72]
    DIRECTION INPUT ;
    USE SIGNAL ;
    PORT
      LAYER M4 ;
        RECT  0 89.52 0.084 89.544 ;
    END
  END c_i[72]
  PIN c_i[730]
    DIRECTION INPUT ;
    USE SIGNAL ;
    PORT
      LAYER M4 ;
        RECT  0 184.272 0.084 184.296 ;
    END
  END c_i[730]
  PIN c_i[731]
    DIRECTION INPUT ;
    USE SIGNAL ;
    PORT
      LAYER M4 ;
        RECT  0 184.416 0.084 184.44 ;
    END
  END c_i[731]
  PIN c_i[732]
    DIRECTION INPUT ;
    USE SIGNAL ;
    PORT
      LAYER M4 ;
        RECT  0 184.56 0.084 184.584 ;
    END
  END c_i[732]
  PIN c_i[733]
    DIRECTION INPUT ;
    USE SIGNAL ;
    PORT
      LAYER M4 ;
        RECT  0 184.704 0.084 184.728 ;
    END
  END c_i[733]
  PIN c_i[734]
    DIRECTION INPUT ;
    USE SIGNAL ;
    PORT
      LAYER M4 ;
        RECT  0 184.848 0.084 184.872 ;
    END
  END c_i[734]
  PIN c_i[735]
    DIRECTION INPUT ;
    USE SIGNAL ;
    PORT
      LAYER M4 ;
        RECT  0 184.992 0.084 185.016 ;
    END
  END c_i[735]
  PIN c_i[736]
    DIRECTION INPUT ;
    USE SIGNAL ;
    PORT
      LAYER M4 ;
        RECT  0 185.136 0.084 185.16 ;
    END
  END c_i[736]
  PIN c_i[737]
    DIRECTION INPUT ;
    USE SIGNAL ;
    PORT
      LAYER M4 ;
        RECT  0 185.28 0.084 185.304 ;
    END
  END c_i[737]
  PIN c_i[738]
    DIRECTION INPUT ;
    USE SIGNAL ;
    PORT
      LAYER M4 ;
        RECT  0 185.424 0.084 185.448 ;
    END
  END c_i[738]
  PIN c_i[739]
    DIRECTION INPUT ;
    USE SIGNAL ;
    PORT
      LAYER M4 ;
        RECT  0 185.568 0.084 185.592 ;
    END
  END c_i[739]
  PIN c_i[73]
    DIRECTION INPUT ;
    USE SIGNAL ;
    PORT
      LAYER M4 ;
        RECT  0 89.664 0.084 89.688 ;
    END
  END c_i[73]
  PIN c_i[740]
    DIRECTION INPUT ;
    USE SIGNAL ;
    PORT
      LAYER M4 ;
        RECT  0 185.712 0.084 185.736 ;
    END
  END c_i[740]
  PIN c_i[741]
    DIRECTION INPUT ;
    USE SIGNAL ;
    PORT
      LAYER M4 ;
        RECT  0 185.856 0.084 185.88 ;
    END
  END c_i[741]
  PIN c_i[742]
    DIRECTION INPUT ;
    USE SIGNAL ;
    PORT
      LAYER M4 ;
        RECT  0 186 0.084 186.024 ;
    END
  END c_i[742]
  PIN c_i[743]
    DIRECTION INPUT ;
    USE SIGNAL ;
    PORT
      LAYER M4 ;
        RECT  0 186.144 0.084 186.168 ;
    END
  END c_i[743]
  PIN c_i[744]
    DIRECTION INPUT ;
    USE SIGNAL ;
    PORT
      LAYER M4 ;
        RECT  0 186.288 0.084 186.312 ;
    END
  END c_i[744]
  PIN c_i[745]
    DIRECTION INPUT ;
    USE SIGNAL ;
    PORT
      LAYER M4 ;
        RECT  0 186.432 0.084 186.456 ;
    END
  END c_i[745]
  PIN c_i[746]
    DIRECTION INPUT ;
    USE SIGNAL ;
    PORT
      LAYER M4 ;
        RECT  0 186.576 0.084 186.6 ;
    END
  END c_i[746]
  PIN c_i[747]
    DIRECTION INPUT ;
    USE SIGNAL ;
    PORT
      LAYER M4 ;
        RECT  0 186.72 0.084 186.744 ;
    END
  END c_i[747]
  PIN c_i[748]
    DIRECTION INPUT ;
    USE SIGNAL ;
    PORT
      LAYER M4 ;
        RECT  0 186.864 0.084 186.888 ;
    END
  END c_i[748]
  PIN c_i[749]
    DIRECTION INPUT ;
    USE SIGNAL ;
    PORT
      LAYER M4 ;
        RECT  0 187.008 0.084 187.032 ;
    END
  END c_i[749]
  PIN c_i[74]
    DIRECTION INPUT ;
    USE SIGNAL ;
    PORT
      LAYER M4 ;
        RECT  0 89.808 0.084 89.832 ;
    END
  END c_i[74]
  PIN c_i[750]
    DIRECTION INPUT ;
    USE SIGNAL ;
    PORT
      LAYER M4 ;
        RECT  0 187.152 0.084 187.176 ;
    END
  END c_i[750]
  PIN c_i[751]
    DIRECTION INPUT ;
    USE SIGNAL ;
    PORT
      LAYER M4 ;
        RECT  0 187.296 0.084 187.32 ;
    END
  END c_i[751]
  PIN c_i[752]
    DIRECTION INPUT ;
    USE SIGNAL ;
    PORT
      LAYER M4 ;
        RECT  0 187.44 0.084 187.464 ;
    END
  END c_i[752]
  PIN c_i[753]
    DIRECTION INPUT ;
    USE SIGNAL ;
    PORT
      LAYER M4 ;
        RECT  0 187.584 0.084 187.608 ;
    END
  END c_i[753]
  PIN c_i[754]
    DIRECTION INPUT ;
    USE SIGNAL ;
    PORT
      LAYER M4 ;
        RECT  0 187.728 0.084 187.752 ;
    END
  END c_i[754]
  PIN c_i[755]
    DIRECTION INPUT ;
    USE SIGNAL ;
    PORT
      LAYER M4 ;
        RECT  0 187.872 0.084 187.896 ;
    END
  END c_i[755]
  PIN c_i[756]
    DIRECTION INPUT ;
    USE SIGNAL ;
    PORT
      LAYER M4 ;
        RECT  0 188.016 0.084 188.04 ;
    END
  END c_i[756]
  PIN c_i[757]
    DIRECTION INPUT ;
    USE SIGNAL ;
    PORT
      LAYER M4 ;
        RECT  0 188.16 0.084 188.184 ;
    END
  END c_i[757]
  PIN c_i[758]
    DIRECTION INPUT ;
    USE SIGNAL ;
    PORT
      LAYER M4 ;
        RECT  0 188.304 0.084 188.328 ;
    END
  END c_i[758]
  PIN c_i[759]
    DIRECTION INPUT ;
    USE SIGNAL ;
    PORT
      LAYER M4 ;
        RECT  0 188.448 0.084 188.472 ;
    END
  END c_i[759]
  PIN c_i[75]
    DIRECTION INPUT ;
    USE SIGNAL ;
    PORT
      LAYER M4 ;
        RECT  0 89.952 0.084 89.976 ;
    END
  END c_i[75]
  PIN c_i[76]
    DIRECTION INPUT ;
    USE SIGNAL ;
    PORT
      LAYER M4 ;
        RECT  0 90.096 0.084 90.12 ;
    END
  END c_i[76]
  PIN c_i[77]
    DIRECTION INPUT ;
    USE SIGNAL ;
    PORT
      LAYER M4 ;
        RECT  0 90.24 0.084 90.264 ;
    END
  END c_i[77]
  PIN c_i[78]
    DIRECTION INPUT ;
    USE SIGNAL ;
    PORT
      LAYER M4 ;
        RECT  0 90.384 0.084 90.408 ;
    END
  END c_i[78]
  PIN c_i[79]
    DIRECTION INPUT ;
    USE SIGNAL ;
    PORT
      LAYER M4 ;
        RECT  0 90.528 0.084 90.552 ;
    END
  END c_i[79]
  PIN c_i[7]
    DIRECTION INPUT ;
    USE SIGNAL ;
    PORT
      LAYER M4 ;
        RECT  0 80.16 0.084 80.184 ;
    END
  END c_i[7]
  PIN c_i[80]
    DIRECTION INPUT ;
    USE SIGNAL ;
    PORT
      LAYER M4 ;
        RECT  0 90.672 0.084 90.696 ;
    END
  END c_i[80]
  PIN c_i[81]
    DIRECTION INPUT ;
    USE SIGNAL ;
    PORT
      LAYER M4 ;
        RECT  0 90.816 0.084 90.84 ;
    END
  END c_i[81]
  PIN c_i[82]
    DIRECTION INPUT ;
    USE SIGNAL ;
    PORT
      LAYER M4 ;
        RECT  0 90.96 0.084 90.984 ;
    END
  END c_i[82]
  PIN c_i[83]
    DIRECTION INPUT ;
    USE SIGNAL ;
    PORT
      LAYER M4 ;
        RECT  0 91.104 0.084 91.128 ;
    END
  END c_i[83]
  PIN c_i[84]
    DIRECTION INPUT ;
    USE SIGNAL ;
    PORT
      LAYER M4 ;
        RECT  0 91.248 0.084 91.272 ;
    END
  END c_i[84]
  PIN c_i[85]
    DIRECTION INPUT ;
    USE SIGNAL ;
    PORT
      LAYER M4 ;
        RECT  0 91.392 0.084 91.416 ;
    END
  END c_i[85]
  PIN c_i[86]
    DIRECTION INPUT ;
    USE SIGNAL ;
    PORT
      LAYER M4 ;
        RECT  0 91.536 0.084 91.56 ;
    END
  END c_i[86]
  PIN c_i[87]
    DIRECTION INPUT ;
    USE SIGNAL ;
    PORT
      LAYER M4 ;
        RECT  0 91.68 0.084 91.704 ;
    END
  END c_i[87]
  PIN c_i[88]
    DIRECTION INPUT ;
    USE SIGNAL ;
    PORT
      LAYER M4 ;
        RECT  0 91.824 0.084 91.848 ;
    END
  END c_i[88]
  PIN c_i[89]
    DIRECTION INPUT ;
    USE SIGNAL ;
    PORT
      LAYER M4 ;
        RECT  0 91.968 0.084 91.992 ;
    END
  END c_i[89]
  PIN c_i[8]
    DIRECTION INPUT ;
    USE SIGNAL ;
    PORT
      LAYER M4 ;
        RECT  0 80.304 0.084 80.328 ;
    END
  END c_i[8]
  PIN c_i[90]
    DIRECTION INPUT ;
    USE SIGNAL ;
    PORT
      LAYER M4 ;
        RECT  0 92.112 0.084 92.136 ;
    END
  END c_i[90]
  PIN c_i[91]
    DIRECTION INPUT ;
    USE SIGNAL ;
    PORT
      LAYER M4 ;
        RECT  0 92.256 0.084 92.28 ;
    END
  END c_i[91]
  PIN c_i[92]
    DIRECTION INPUT ;
    USE SIGNAL ;
    PORT
      LAYER M4 ;
        RECT  0 92.4 0.084 92.424 ;
    END
  END c_i[92]
  PIN c_i[93]
    DIRECTION INPUT ;
    USE SIGNAL ;
    PORT
      LAYER M4 ;
        RECT  0 92.544 0.084 92.568 ;
    END
  END c_i[93]
  PIN c_i[94]
    DIRECTION INPUT ;
    USE SIGNAL ;
    PORT
      LAYER M4 ;
        RECT  0 92.688 0.084 92.712 ;
    END
  END c_i[94]
  PIN c_i[95]
    DIRECTION INPUT ;
    USE SIGNAL ;
    PORT
      LAYER M4 ;
        RECT  0 92.832 0.084 92.856 ;
    END
  END c_i[95]
  PIN c_i[96]
    DIRECTION INPUT ;
    USE SIGNAL ;
    PORT
      LAYER M4 ;
        RECT  0 92.976 0.084 93 ;
    END
  END c_i[96]
  PIN c_i[97]
    DIRECTION INPUT ;
    USE SIGNAL ;
    PORT
      LAYER M4 ;
        RECT  0 93.12 0.084 93.144 ;
    END
  END c_i[97]
  PIN c_i[98]
    DIRECTION INPUT ;
    USE SIGNAL ;
    PORT
      LAYER M4 ;
        RECT  0 93.264 0.084 93.288 ;
    END
  END c_i[98]
  PIN c_i[99]
    DIRECTION INPUT ;
    USE SIGNAL ;
    PORT
      LAYER M4 ;
        RECT  0 93.408 0.084 93.432 ;
    END
  END c_i[99]
  PIN c_i[9]
    DIRECTION INPUT ;
    USE SIGNAL ;
    PORT
      LAYER M4 ;
        RECT  0 80.448 0.084 80.472 ;
    END
  END c_i[9]
  PIN c_o[0]
    DIRECTION OUTPUT ;
    USE SIGNAL ;
    PORT
      LAYER M5 ;
        RECT  191.568 0 191.592 0.084 ;
    END
  END c_o[0]
  PIN c_o[100]
    DIRECTION OUTPUT ;
    USE SIGNAL ;
    PORT
      LAYER M5 ;
        RECT  205.968 0 205.992 0.084 ;
    END
  END c_o[100]
  PIN c_o[101]
    DIRECTION OUTPUT ;
    USE SIGNAL ;
    PORT
      LAYER M5 ;
        RECT  206.112 0 206.136 0.084 ;
    END
  END c_o[101]
  PIN c_o[102]
    DIRECTION OUTPUT ;
    USE SIGNAL ;
    PORT
      LAYER M5 ;
        RECT  206.256 0 206.28 0.084 ;
    END
  END c_o[102]
  PIN c_o[103]
    DIRECTION OUTPUT ;
    USE SIGNAL ;
    PORT
      LAYER M5 ;
        RECT  206.4 0 206.424 0.084 ;
    END
  END c_o[103]
  PIN c_o[104]
    DIRECTION OUTPUT ;
    USE SIGNAL ;
    PORT
      LAYER M5 ;
        RECT  206.544 0 206.568 0.084 ;
    END
  END c_o[104]
  PIN c_o[105]
    DIRECTION OUTPUT ;
    USE SIGNAL ;
    PORT
      LAYER M5 ;
        RECT  206.688 0 206.712 0.084 ;
    END
  END c_o[105]
  PIN c_o[106]
    DIRECTION OUTPUT ;
    USE SIGNAL ;
    PORT
      LAYER M5 ;
        RECT  206.832 0 206.856 0.084 ;
    END
  END c_o[106]
  PIN c_o[107]
    DIRECTION OUTPUT ;
    USE SIGNAL ;
    PORT
      LAYER M5 ;
        RECT  206.976 0 207 0.084 ;
    END
  END c_o[107]
  PIN c_o[108]
    DIRECTION OUTPUT ;
    USE SIGNAL ;
    PORT
      LAYER M5 ;
        RECT  207.12 0 207.144 0.084 ;
    END
  END c_o[108]
  PIN c_o[109]
    DIRECTION OUTPUT ;
    USE SIGNAL ;
    PORT
      LAYER M5 ;
        RECT  207.264 0 207.288 0.084 ;
    END
  END c_o[109]
  PIN c_o[10]
    DIRECTION OUTPUT ;
    USE SIGNAL ;
    PORT
      LAYER M5 ;
        RECT  193.008 0 193.032 0.084 ;
    END
  END c_o[10]
  PIN c_o[110]
    DIRECTION OUTPUT ;
    USE SIGNAL ;
    PORT
      LAYER M5 ;
        RECT  207.408 0 207.432 0.084 ;
    END
  END c_o[110]
  PIN c_o[111]
    DIRECTION OUTPUT ;
    USE SIGNAL ;
    PORT
      LAYER M5 ;
        RECT  207.552 0 207.576 0.084 ;
    END
  END c_o[111]
  PIN c_o[112]
    DIRECTION OUTPUT ;
    USE SIGNAL ;
    PORT
      LAYER M5 ;
        RECT  207.696 0 207.72 0.084 ;
    END
  END c_o[112]
  PIN c_o[113]
    DIRECTION OUTPUT ;
    USE SIGNAL ;
    PORT
      LAYER M5 ;
        RECT  207.84 0 207.864 0.084 ;
    END
  END c_o[113]
  PIN c_o[114]
    DIRECTION OUTPUT ;
    USE SIGNAL ;
    PORT
      LAYER M5 ;
        RECT  207.984 0 208.008 0.084 ;
    END
  END c_o[114]
  PIN c_o[115]
    DIRECTION OUTPUT ;
    USE SIGNAL ;
    PORT
      LAYER M5 ;
        RECT  208.128 0 208.152 0.084 ;
    END
  END c_o[115]
  PIN c_o[116]
    DIRECTION OUTPUT ;
    USE SIGNAL ;
    PORT
      LAYER M5 ;
        RECT  208.272 0 208.296 0.084 ;
    END
  END c_o[116]
  PIN c_o[117]
    DIRECTION OUTPUT ;
    USE SIGNAL ;
    PORT
      LAYER M5 ;
        RECT  208.416 0 208.44 0.084 ;
    END
  END c_o[117]
  PIN c_o[118]
    DIRECTION OUTPUT ;
    USE SIGNAL ;
    PORT
      LAYER M5 ;
        RECT  208.56 0 208.584 0.084 ;
    END
  END c_o[118]
  PIN c_o[119]
    DIRECTION OUTPUT ;
    USE SIGNAL ;
    PORT
      LAYER M5 ;
        RECT  208.704 0 208.728 0.084 ;
    END
  END c_o[119]
  PIN c_o[11]
    DIRECTION OUTPUT ;
    USE SIGNAL ;
    PORT
      LAYER M5 ;
        RECT  193.152 0 193.176 0.084 ;
    END
  END c_o[11]
  PIN c_o[120]
    DIRECTION OUTPUT ;
    USE SIGNAL ;
    PORT
      LAYER M5 ;
        RECT  208.848 0 208.872 0.084 ;
    END
  END c_o[120]
  PIN c_o[121]
    DIRECTION OUTPUT ;
    USE SIGNAL ;
    PORT
      LAYER M5 ;
        RECT  208.992 0 209.016 0.084 ;
    END
  END c_o[121]
  PIN c_o[122]
    DIRECTION OUTPUT ;
    USE SIGNAL ;
    PORT
      LAYER M5 ;
        RECT  209.136 0 209.16 0.084 ;
    END
  END c_o[122]
  PIN c_o[123]
    DIRECTION OUTPUT ;
    USE SIGNAL ;
    PORT
      LAYER M5 ;
        RECT  209.28 0 209.304 0.084 ;
    END
  END c_o[123]
  PIN c_o[124]
    DIRECTION OUTPUT ;
    USE SIGNAL ;
    PORT
      LAYER M5 ;
        RECT  209.424 0 209.448 0.084 ;
    END
  END c_o[124]
  PIN c_o[125]
    DIRECTION OUTPUT ;
    USE SIGNAL ;
    PORT
      LAYER M5 ;
        RECT  209.568 0 209.592 0.084 ;
    END
  END c_o[125]
  PIN c_o[126]
    DIRECTION OUTPUT ;
    USE SIGNAL ;
    PORT
      LAYER M5 ;
        RECT  209.712 0 209.736 0.084 ;
    END
  END c_o[126]
  PIN c_o[127]
    DIRECTION OUTPUT ;
    USE SIGNAL ;
    PORT
      LAYER M5 ;
        RECT  209.856 0 209.88 0.084 ;
    END
  END c_o[127]
  PIN c_o[128]
    DIRECTION OUTPUT ;
    USE SIGNAL ;
    PORT
      LAYER M5 ;
        RECT  210 0 210.024 0.084 ;
    END
  END c_o[128]
  PIN c_o[129]
    DIRECTION OUTPUT ;
    USE SIGNAL ;
    PORT
      LAYER M5 ;
        RECT  210.144 0 210.168 0.084 ;
    END
  END c_o[129]
  PIN c_o[12]
    DIRECTION OUTPUT ;
    USE SIGNAL ;
    PORT
      LAYER M5 ;
        RECT  193.296 0 193.32 0.084 ;
    END
  END c_o[12]
  PIN c_o[130]
    DIRECTION OUTPUT ;
    USE SIGNAL ;
    PORT
      LAYER M5 ;
        RECT  210.288 0 210.312 0.084 ;
    END
  END c_o[130]
  PIN c_o[131]
    DIRECTION OUTPUT ;
    USE SIGNAL ;
    PORT
      LAYER M5 ;
        RECT  210.432 0 210.456 0.084 ;
    END
  END c_o[131]
  PIN c_o[132]
    DIRECTION OUTPUT ;
    USE SIGNAL ;
    PORT
      LAYER M5 ;
        RECT  210.576 0 210.6 0.084 ;
    END
  END c_o[132]
  PIN c_o[133]
    DIRECTION OUTPUT ;
    USE SIGNAL ;
    PORT
      LAYER M5 ;
        RECT  210.72 0 210.744 0.084 ;
    END
  END c_o[133]
  PIN c_o[134]
    DIRECTION OUTPUT ;
    USE SIGNAL ;
    PORT
      LAYER M5 ;
        RECT  210.864 0 210.888 0.084 ;
    END
  END c_o[134]
  PIN c_o[135]
    DIRECTION OUTPUT ;
    USE SIGNAL ;
    PORT
      LAYER M5 ;
        RECT  211.008 0 211.032 0.084 ;
    END
  END c_o[135]
  PIN c_o[136]
    DIRECTION OUTPUT ;
    USE SIGNAL ;
    PORT
      LAYER M5 ;
        RECT  211.152 0 211.176 0.084 ;
    END
  END c_o[136]
  PIN c_o[137]
    DIRECTION OUTPUT ;
    USE SIGNAL ;
    PORT
      LAYER M5 ;
        RECT  211.296 0 211.32 0.084 ;
    END
  END c_o[137]
  PIN c_o[138]
    DIRECTION OUTPUT ;
    USE SIGNAL ;
    PORT
      LAYER M5 ;
        RECT  211.44 0 211.464 0.084 ;
    END
  END c_o[138]
  PIN c_o[139]
    DIRECTION OUTPUT ;
    USE SIGNAL ;
    PORT
      LAYER M5 ;
        RECT  211.584 0 211.608 0.084 ;
    END
  END c_o[139]
  PIN c_o[13]
    DIRECTION OUTPUT ;
    USE SIGNAL ;
    PORT
      LAYER M5 ;
        RECT  193.44 0 193.464 0.084 ;
    END
  END c_o[13]
  PIN c_o[140]
    DIRECTION OUTPUT ;
    USE SIGNAL ;
    PORT
      LAYER M5 ;
        RECT  211.728 0 211.752 0.084 ;
    END
  END c_o[140]
  PIN c_o[141]
    DIRECTION OUTPUT ;
    USE SIGNAL ;
    PORT
      LAYER M5 ;
        RECT  211.872 0 211.896 0.084 ;
    END
  END c_o[141]
  PIN c_o[142]
    DIRECTION OUTPUT ;
    USE SIGNAL ;
    PORT
      LAYER M5 ;
        RECT  212.016 0 212.04 0.084 ;
    END
  END c_o[142]
  PIN c_o[143]
    DIRECTION OUTPUT ;
    USE SIGNAL ;
    PORT
      LAYER M5 ;
        RECT  212.16 0 212.184 0.084 ;
    END
  END c_o[143]
  PIN c_o[144]
    DIRECTION OUTPUT ;
    USE SIGNAL ;
    PORT
      LAYER M5 ;
        RECT  212.304 0 212.328 0.084 ;
    END
  END c_o[144]
  PIN c_o[145]
    DIRECTION OUTPUT ;
    USE SIGNAL ;
    PORT
      LAYER M5 ;
        RECT  212.448 0 212.472 0.084 ;
    END
  END c_o[145]
  PIN c_o[146]
    DIRECTION OUTPUT ;
    USE SIGNAL ;
    PORT
      LAYER M5 ;
        RECT  212.592 0 212.616 0.084 ;
    END
  END c_o[146]
  PIN c_o[147]
    DIRECTION OUTPUT ;
    USE SIGNAL ;
    PORT
      LAYER M5 ;
        RECT  212.736 0 212.76 0.084 ;
    END
  END c_o[147]
  PIN c_o[148]
    DIRECTION OUTPUT ;
    USE SIGNAL ;
    PORT
      LAYER M5 ;
        RECT  212.88 0 212.904 0.084 ;
    END
  END c_o[148]
  PIN c_o[149]
    DIRECTION OUTPUT ;
    USE SIGNAL ;
    PORT
      LAYER M5 ;
        RECT  213.024 0 213.048 0.084 ;
    END
  END c_o[149]
  PIN c_o[14]
    DIRECTION OUTPUT ;
    USE SIGNAL ;
    PORT
      LAYER M5 ;
        RECT  193.584 0 193.608 0.084 ;
    END
  END c_o[14]
  PIN c_o[150]
    DIRECTION OUTPUT ;
    USE SIGNAL ;
    PORT
      LAYER M5 ;
        RECT  213.168 0 213.192 0.084 ;
    END
  END c_o[150]
  PIN c_o[151]
    DIRECTION OUTPUT ;
    USE SIGNAL ;
    PORT
      LAYER M5 ;
        RECT  213.312 0 213.336 0.084 ;
    END
  END c_o[151]
  PIN c_o[152]
    DIRECTION OUTPUT ;
    USE SIGNAL ;
    PORT
      LAYER M5 ;
        RECT  213.456 0 213.48 0.084 ;
    END
  END c_o[152]
  PIN c_o[153]
    DIRECTION OUTPUT ;
    USE SIGNAL ;
    PORT
      LAYER M5 ;
        RECT  213.6 0 213.624 0.084 ;
    END
  END c_o[153]
  PIN c_o[154]
    DIRECTION OUTPUT ;
    USE SIGNAL ;
    PORT
      LAYER M5 ;
        RECT  213.744 0 213.768 0.084 ;
    END
  END c_o[154]
  PIN c_o[155]
    DIRECTION OUTPUT ;
    USE SIGNAL ;
    PORT
      LAYER M5 ;
        RECT  213.888 0 213.912 0.084 ;
    END
  END c_o[155]
  PIN c_o[156]
    DIRECTION OUTPUT ;
    USE SIGNAL ;
    PORT
      LAYER M5 ;
        RECT  214.032 0 214.056 0.084 ;
    END
  END c_o[156]
  PIN c_o[157]
    DIRECTION OUTPUT ;
    USE SIGNAL ;
    PORT
      LAYER M5 ;
        RECT  214.176 0 214.2 0.084 ;
    END
  END c_o[157]
  PIN c_o[158]
    DIRECTION OUTPUT ;
    USE SIGNAL ;
    PORT
      LAYER M5 ;
        RECT  214.32 0 214.344 0.084 ;
    END
  END c_o[158]
  PIN c_o[159]
    DIRECTION OUTPUT ;
    USE SIGNAL ;
    PORT
      LAYER M5 ;
        RECT  214.464 0 214.488 0.084 ;
    END
  END c_o[159]
  PIN c_o[15]
    DIRECTION OUTPUT ;
    USE SIGNAL ;
    PORT
      LAYER M5 ;
        RECT  193.728 0 193.752 0.084 ;
    END
  END c_o[15]
  PIN c_o[160]
    DIRECTION OUTPUT ;
    USE SIGNAL ;
    PORT
      LAYER M5 ;
        RECT  214.608 0 214.632 0.084 ;
    END
  END c_o[160]
  PIN c_o[161]
    DIRECTION OUTPUT ;
    USE SIGNAL ;
    PORT
      LAYER M5 ;
        RECT  214.752 0 214.776 0.084 ;
    END
  END c_o[161]
  PIN c_o[162]
    DIRECTION OUTPUT ;
    USE SIGNAL ;
    PORT
      LAYER M5 ;
        RECT  214.896 0 214.92 0.084 ;
    END
  END c_o[162]
  PIN c_o[163]
    DIRECTION OUTPUT ;
    USE SIGNAL ;
    PORT
      LAYER M5 ;
        RECT  215.04 0 215.064 0.084 ;
    END
  END c_o[163]
  PIN c_o[164]
    DIRECTION OUTPUT ;
    USE SIGNAL ;
    PORT
      LAYER M5 ;
        RECT  215.184 0 215.208 0.084 ;
    END
  END c_o[164]
  PIN c_o[165]
    DIRECTION OUTPUT ;
    USE SIGNAL ;
    PORT
      LAYER M5 ;
        RECT  215.328 0 215.352 0.084 ;
    END
  END c_o[165]
  PIN c_o[166]
    DIRECTION OUTPUT ;
    USE SIGNAL ;
    PORT
      LAYER M5 ;
        RECT  215.472 0 215.496 0.084 ;
    END
  END c_o[166]
  PIN c_o[167]
    DIRECTION OUTPUT ;
    USE SIGNAL ;
    PORT
      LAYER M5 ;
        RECT  215.616 0 215.64 0.084 ;
    END
  END c_o[167]
  PIN c_o[168]
    DIRECTION OUTPUT ;
    USE SIGNAL ;
    PORT
      LAYER M5 ;
        RECT  215.76 0 215.784 0.084 ;
    END
  END c_o[168]
  PIN c_o[169]
    DIRECTION OUTPUT ;
    USE SIGNAL ;
    PORT
      LAYER M5 ;
        RECT  215.904 0 215.928 0.084 ;
    END
  END c_o[169]
  PIN c_o[16]
    DIRECTION OUTPUT ;
    USE SIGNAL ;
    PORT
      LAYER M5 ;
        RECT  193.872 0 193.896 0.084 ;
    END
  END c_o[16]
  PIN c_o[170]
    DIRECTION OUTPUT ;
    USE SIGNAL ;
    PORT
      LAYER M5 ;
        RECT  216.048 0 216.072 0.084 ;
    END
  END c_o[170]
  PIN c_o[171]
    DIRECTION OUTPUT ;
    USE SIGNAL ;
    PORT
      LAYER M5 ;
        RECT  216.192 0 216.216 0.084 ;
    END
  END c_o[171]
  PIN c_o[172]
    DIRECTION OUTPUT ;
    USE SIGNAL ;
    PORT
      LAYER M5 ;
        RECT  216.336 0 216.36 0.084 ;
    END
  END c_o[172]
  PIN c_o[173]
    DIRECTION OUTPUT ;
    USE SIGNAL ;
    PORT
      LAYER M5 ;
        RECT  216.48 0 216.504 0.084 ;
    END
  END c_o[173]
  PIN c_o[174]
    DIRECTION OUTPUT ;
    USE SIGNAL ;
    PORT
      LAYER M5 ;
        RECT  216.624 0 216.648 0.084 ;
    END
  END c_o[174]
  PIN c_o[175]
    DIRECTION OUTPUT ;
    USE SIGNAL ;
    PORT
      LAYER M5 ;
        RECT  216.768 0 216.792 0.084 ;
    END
  END c_o[175]
  PIN c_o[176]
    DIRECTION OUTPUT ;
    USE SIGNAL ;
    PORT
      LAYER M5 ;
        RECT  216.912 0 216.936 0.084 ;
    END
  END c_o[176]
  PIN c_o[177]
    DIRECTION OUTPUT ;
    USE SIGNAL ;
    PORT
      LAYER M5 ;
        RECT  217.056 0 217.08 0.084 ;
    END
  END c_o[177]
  PIN c_o[178]
    DIRECTION OUTPUT ;
    USE SIGNAL ;
    PORT
      LAYER M5 ;
        RECT  217.2 0 217.224 0.084 ;
    END
  END c_o[178]
  PIN c_o[179]
    DIRECTION OUTPUT ;
    USE SIGNAL ;
    PORT
      LAYER M5 ;
        RECT  217.344 0 217.368 0.084 ;
    END
  END c_o[179]
  PIN c_o[17]
    DIRECTION OUTPUT ;
    USE SIGNAL ;
    PORT
      LAYER M5 ;
        RECT  194.016 0 194.04 0.084 ;
    END
  END c_o[17]
  PIN c_o[180]
    DIRECTION OUTPUT ;
    USE SIGNAL ;
    PORT
      LAYER M5 ;
        RECT  217.488 0 217.512 0.084 ;
    END
  END c_o[180]
  PIN c_o[181]
    DIRECTION OUTPUT ;
    USE SIGNAL ;
    PORT
      LAYER M5 ;
        RECT  217.632 0 217.656 0.084 ;
    END
  END c_o[181]
  PIN c_o[182]
    DIRECTION OUTPUT ;
    USE SIGNAL ;
    PORT
      LAYER M5 ;
        RECT  217.776 0 217.8 0.084 ;
    END
  END c_o[182]
  PIN c_o[183]
    DIRECTION OUTPUT ;
    USE SIGNAL ;
    PORT
      LAYER M5 ;
        RECT  217.92 0 217.944 0.084 ;
    END
  END c_o[183]
  PIN c_o[184]
    DIRECTION OUTPUT ;
    USE SIGNAL ;
    PORT
      LAYER M5 ;
        RECT  218.064 0 218.088 0.084 ;
    END
  END c_o[184]
  PIN c_o[185]
    DIRECTION OUTPUT ;
    USE SIGNAL ;
    PORT
      LAYER M5 ;
        RECT  218.208 0 218.232 0.084 ;
    END
  END c_o[185]
  PIN c_o[186]
    DIRECTION OUTPUT ;
    USE SIGNAL ;
    PORT
      LAYER M5 ;
        RECT  218.352 0 218.376 0.084 ;
    END
  END c_o[186]
  PIN c_o[187]
    DIRECTION OUTPUT ;
    USE SIGNAL ;
    PORT
      LAYER M5 ;
        RECT  218.496 0 218.52 0.084 ;
    END
  END c_o[187]
  PIN c_o[188]
    DIRECTION OUTPUT ;
    USE SIGNAL ;
    PORT
      LAYER M5 ;
        RECT  218.64 0 218.664 0.084 ;
    END
  END c_o[188]
  PIN c_o[189]
    DIRECTION OUTPUT ;
    USE SIGNAL ;
    PORT
      LAYER M5 ;
        RECT  218.784 0 218.808 0.084 ;
    END
  END c_o[189]
  PIN c_o[18]
    DIRECTION OUTPUT ;
    USE SIGNAL ;
    PORT
      LAYER M5 ;
        RECT  194.16 0 194.184 0.084 ;
    END
  END c_o[18]
  PIN c_o[190]
    DIRECTION OUTPUT ;
    USE SIGNAL ;
    PORT
      LAYER M5 ;
        RECT  218.928 0 218.952 0.084 ;
    END
  END c_o[190]
  PIN c_o[191]
    DIRECTION OUTPUT ;
    USE SIGNAL ;
    PORT
      LAYER M5 ;
        RECT  219.072 0 219.096 0.084 ;
    END
  END c_o[191]
  PIN c_o[192]
    DIRECTION OUTPUT ;
    USE SIGNAL ;
    PORT
      LAYER M5 ;
        RECT  219.216 0 219.24 0.084 ;
    END
  END c_o[192]
  PIN c_o[193]
    DIRECTION OUTPUT ;
    USE SIGNAL ;
    PORT
      LAYER M5 ;
        RECT  219.36 0 219.384 0.084 ;
    END
  END c_o[193]
  PIN c_o[194]
    DIRECTION OUTPUT ;
    USE SIGNAL ;
    PORT
      LAYER M5 ;
        RECT  219.504 0 219.528 0.084 ;
    END
  END c_o[194]
  PIN c_o[195]
    DIRECTION OUTPUT ;
    USE SIGNAL ;
    PORT
      LAYER M5 ;
        RECT  219.648 0 219.672 0.084 ;
    END
  END c_o[195]
  PIN c_o[196]
    DIRECTION OUTPUT ;
    USE SIGNAL ;
    PORT
      LAYER M5 ;
        RECT  219.792 0 219.816 0.084 ;
    END
  END c_o[196]
  PIN c_o[197]
    DIRECTION OUTPUT ;
    USE SIGNAL ;
    PORT
      LAYER M5 ;
        RECT  219.936 0 219.96 0.084 ;
    END
  END c_o[197]
  PIN c_o[198]
    DIRECTION OUTPUT ;
    USE SIGNAL ;
    PORT
      LAYER M5 ;
        RECT  220.08 0 220.104 0.084 ;
    END
  END c_o[198]
  PIN c_o[199]
    DIRECTION OUTPUT ;
    USE SIGNAL ;
    PORT
      LAYER M5 ;
        RECT  220.224 0 220.248 0.084 ;
    END
  END c_o[199]
  PIN c_o[19]
    DIRECTION OUTPUT ;
    USE SIGNAL ;
    PORT
      LAYER M5 ;
        RECT  194.304 0 194.328 0.084 ;
    END
  END c_o[19]
  PIN c_o[1]
    DIRECTION OUTPUT ;
    USE SIGNAL ;
    PORT
      LAYER M5 ;
        RECT  191.712 0 191.736 0.084 ;
    END
  END c_o[1]
  PIN c_o[200]
    DIRECTION OUTPUT ;
    USE SIGNAL ;
    PORT
      LAYER M5 ;
        RECT  220.368 0 220.392 0.084 ;
    END
  END c_o[200]
  PIN c_o[201]
    DIRECTION OUTPUT ;
    USE SIGNAL ;
    PORT
      LAYER M5 ;
        RECT  220.512 0 220.536 0.084 ;
    END
  END c_o[201]
  PIN c_o[202]
    DIRECTION OUTPUT ;
    USE SIGNAL ;
    PORT
      LAYER M5 ;
        RECT  220.656 0 220.68 0.084 ;
    END
  END c_o[202]
  PIN c_o[203]
    DIRECTION OUTPUT ;
    USE SIGNAL ;
    PORT
      LAYER M5 ;
        RECT  220.8 0 220.824 0.084 ;
    END
  END c_o[203]
  PIN c_o[204]
    DIRECTION OUTPUT ;
    USE SIGNAL ;
    PORT
      LAYER M5 ;
        RECT  220.944 0 220.968 0.084 ;
    END
  END c_o[204]
  PIN c_o[205]
    DIRECTION OUTPUT ;
    USE SIGNAL ;
    PORT
      LAYER M5 ;
        RECT  221.088 0 221.112 0.084 ;
    END
  END c_o[205]
  PIN c_o[206]
    DIRECTION OUTPUT ;
    USE SIGNAL ;
    PORT
      LAYER M5 ;
        RECT  221.232 0 221.256 0.084 ;
    END
  END c_o[206]
  PIN c_o[207]
    DIRECTION OUTPUT ;
    USE SIGNAL ;
    PORT
      LAYER M5 ;
        RECT  221.376 0 221.4 0.084 ;
    END
  END c_o[207]
  PIN c_o[208]
    DIRECTION OUTPUT ;
    USE SIGNAL ;
    PORT
      LAYER M5 ;
        RECT  221.52 0 221.544 0.084 ;
    END
  END c_o[208]
  PIN c_o[209]
    DIRECTION OUTPUT ;
    USE SIGNAL ;
    PORT
      LAYER M5 ;
        RECT  221.664 0 221.688 0.084 ;
    END
  END c_o[209]
  PIN c_o[20]
    DIRECTION OUTPUT ;
    USE SIGNAL ;
    PORT
      LAYER M5 ;
        RECT  194.448 0 194.472 0.084 ;
    END
  END c_o[20]
  PIN c_o[210]
    DIRECTION OUTPUT ;
    USE SIGNAL ;
    PORT
      LAYER M5 ;
        RECT  221.808 0 221.832 0.084 ;
    END
  END c_o[210]
  PIN c_o[211]
    DIRECTION OUTPUT ;
    USE SIGNAL ;
    PORT
      LAYER M5 ;
        RECT  221.952 0 221.976 0.084 ;
    END
  END c_o[211]
  PIN c_o[212]
    DIRECTION OUTPUT ;
    USE SIGNAL ;
    PORT
      LAYER M5 ;
        RECT  222.096 0 222.12 0.084 ;
    END
  END c_o[212]
  PIN c_o[213]
    DIRECTION OUTPUT ;
    USE SIGNAL ;
    PORT
      LAYER M5 ;
        RECT  222.24 0 222.264 0.084 ;
    END
  END c_o[213]
  PIN c_o[214]
    DIRECTION OUTPUT ;
    USE SIGNAL ;
    PORT
      LAYER M5 ;
        RECT  222.384 0 222.408 0.084 ;
    END
  END c_o[214]
  PIN c_o[215]
    DIRECTION OUTPUT ;
    USE SIGNAL ;
    PORT
      LAYER M5 ;
        RECT  222.528 0 222.552 0.084 ;
    END
  END c_o[215]
  PIN c_o[216]
    DIRECTION OUTPUT ;
    USE SIGNAL ;
    PORT
      LAYER M5 ;
        RECT  222.672 0 222.696 0.084 ;
    END
  END c_o[216]
  PIN c_o[217]
    DIRECTION OUTPUT ;
    USE SIGNAL ;
    PORT
      LAYER M5 ;
        RECT  222.816 0 222.84 0.084 ;
    END
  END c_o[217]
  PIN c_o[218]
    DIRECTION OUTPUT ;
    USE SIGNAL ;
    PORT
      LAYER M5 ;
        RECT  222.96 0 222.984 0.084 ;
    END
  END c_o[218]
  PIN c_o[219]
    DIRECTION OUTPUT ;
    USE SIGNAL ;
    PORT
      LAYER M5 ;
        RECT  194.304 267.756 194.328 267.84 ;
    END
  END c_o[219]
  PIN c_o[21]
    DIRECTION OUTPUT ;
    USE SIGNAL ;
    PORT
      LAYER M5 ;
        RECT  194.592 0 194.616 0.084 ;
    END
  END c_o[21]
  PIN c_o[220]
    DIRECTION OUTPUT ;
    USE SIGNAL ;
    PORT
      LAYER M5 ;
        RECT  194.448 267.756 194.472 267.84 ;
    END
  END c_o[220]
  PIN c_o[221]
    DIRECTION OUTPUT ;
    USE SIGNAL ;
    PORT
      LAYER M5 ;
        RECT  194.592 267.756 194.616 267.84 ;
    END
  END c_o[221]
  PIN c_o[222]
    DIRECTION OUTPUT ;
    USE SIGNAL ;
    PORT
      LAYER M5 ;
        RECT  194.736 267.756 194.76 267.84 ;
    END
  END c_o[222]
  PIN c_o[223]
    DIRECTION OUTPUT ;
    USE SIGNAL ;
    PORT
      LAYER M5 ;
        RECT  194.88 267.756 194.904 267.84 ;
    END
  END c_o[223]
  PIN c_o[224]
    DIRECTION OUTPUT ;
    USE SIGNAL ;
    PORT
      LAYER M5 ;
        RECT  195.024 267.756 195.048 267.84 ;
    END
  END c_o[224]
  PIN c_o[225]
    DIRECTION OUTPUT ;
    USE SIGNAL ;
    PORT
      LAYER M5 ;
        RECT  195.168 267.756 195.192 267.84 ;
    END
  END c_o[225]
  PIN c_o[226]
    DIRECTION OUTPUT ;
    USE SIGNAL ;
    PORT
      LAYER M5 ;
        RECT  195.312 267.756 195.336 267.84 ;
    END
  END c_o[226]
  PIN c_o[227]
    DIRECTION OUTPUT ;
    USE SIGNAL ;
    PORT
      LAYER M5 ;
        RECT  195.456 267.756 195.48 267.84 ;
    END
  END c_o[227]
  PIN c_o[228]
    DIRECTION OUTPUT ;
    USE SIGNAL ;
    PORT
      LAYER M5 ;
        RECT  195.6 267.756 195.624 267.84 ;
    END
  END c_o[228]
  PIN c_o[229]
    DIRECTION OUTPUT ;
    USE SIGNAL ;
    PORT
      LAYER M5 ;
        RECT  195.744 267.756 195.768 267.84 ;
    END
  END c_o[229]
  PIN c_o[22]
    DIRECTION OUTPUT ;
    USE SIGNAL ;
    PORT
      LAYER M5 ;
        RECT  194.736 0 194.76 0.084 ;
    END
  END c_o[22]
  PIN c_o[230]
    DIRECTION OUTPUT ;
    USE SIGNAL ;
    PORT
      LAYER M5 ;
        RECT  195.888 267.756 195.912 267.84 ;
    END
  END c_o[230]
  PIN c_o[231]
    DIRECTION OUTPUT ;
    USE SIGNAL ;
    PORT
      LAYER M5 ;
        RECT  196.032 267.756 196.056 267.84 ;
    END
  END c_o[231]
  PIN c_o[232]
    DIRECTION OUTPUT ;
    USE SIGNAL ;
    PORT
      LAYER M5 ;
        RECT  196.176 267.756 196.2 267.84 ;
    END
  END c_o[232]
  PIN c_o[233]
    DIRECTION OUTPUT ;
    USE SIGNAL ;
    PORT
      LAYER M5 ;
        RECT  196.32 267.756 196.344 267.84 ;
    END
  END c_o[233]
  PIN c_o[234]
    DIRECTION OUTPUT ;
    USE SIGNAL ;
    PORT
      LAYER M5 ;
        RECT  196.464 267.756 196.488 267.84 ;
    END
  END c_o[234]
  PIN c_o[235]
    DIRECTION OUTPUT ;
    USE SIGNAL ;
    PORT
      LAYER M5 ;
        RECT  196.608 267.756 196.632 267.84 ;
    END
  END c_o[235]
  PIN c_o[236]
    DIRECTION OUTPUT ;
    USE SIGNAL ;
    PORT
      LAYER M5 ;
        RECT  196.752 267.756 196.776 267.84 ;
    END
  END c_o[236]
  PIN c_o[237]
    DIRECTION OUTPUT ;
    USE SIGNAL ;
    PORT
      LAYER M5 ;
        RECT  196.896 267.756 196.92 267.84 ;
    END
  END c_o[237]
  PIN c_o[238]
    DIRECTION OUTPUT ;
    USE SIGNAL ;
    PORT
      LAYER M5 ;
        RECT  197.04 267.756 197.064 267.84 ;
    END
  END c_o[238]
  PIN c_o[239]
    DIRECTION OUTPUT ;
    USE SIGNAL ;
    PORT
      LAYER M5 ;
        RECT  197.184 267.756 197.208 267.84 ;
    END
  END c_o[239]
  PIN c_o[23]
    DIRECTION OUTPUT ;
    USE SIGNAL ;
    PORT
      LAYER M5 ;
        RECT  194.88 0 194.904 0.084 ;
    END
  END c_o[23]
  PIN c_o[240]
    DIRECTION OUTPUT ;
    USE SIGNAL ;
    PORT
      LAYER M5 ;
        RECT  197.328 267.756 197.352 267.84 ;
    END
  END c_o[240]
  PIN c_o[241]
    DIRECTION OUTPUT ;
    USE SIGNAL ;
    PORT
      LAYER M5 ;
        RECT  197.472 267.756 197.496 267.84 ;
    END
  END c_o[241]
  PIN c_o[242]
    DIRECTION OUTPUT ;
    USE SIGNAL ;
    PORT
      LAYER M5 ;
        RECT  197.616 267.756 197.64 267.84 ;
    END
  END c_o[242]
  PIN c_o[243]
    DIRECTION OUTPUT ;
    USE SIGNAL ;
    PORT
      LAYER M5 ;
        RECT  197.76 267.756 197.784 267.84 ;
    END
  END c_o[243]
  PIN c_o[244]
    DIRECTION OUTPUT ;
    USE SIGNAL ;
    PORT
      LAYER M5 ;
        RECT  197.904 267.756 197.928 267.84 ;
    END
  END c_o[244]
  PIN c_o[245]
    DIRECTION OUTPUT ;
    USE SIGNAL ;
    PORT
      LAYER M5 ;
        RECT  198.048 267.756 198.072 267.84 ;
    END
  END c_o[245]
  PIN c_o[246]
    DIRECTION OUTPUT ;
    USE SIGNAL ;
    PORT
      LAYER M5 ;
        RECT  198.192 267.756 198.216 267.84 ;
    END
  END c_o[246]
  PIN c_o[247]
    DIRECTION OUTPUT ;
    USE SIGNAL ;
    PORT
      LAYER M5 ;
        RECT  198.336 267.756 198.36 267.84 ;
    END
  END c_o[247]
  PIN c_o[24]
    DIRECTION OUTPUT ;
    USE SIGNAL ;
    PORT
      LAYER M5 ;
        RECT  195.024 0 195.048 0.084 ;
    END
  END c_o[24]
  PIN c_o[25]
    DIRECTION OUTPUT ;
    USE SIGNAL ;
    PORT
      LAYER M5 ;
        RECT  195.168 0 195.192 0.084 ;
    END
  END c_o[25]
  PIN c_o[26]
    DIRECTION OUTPUT ;
    USE SIGNAL ;
    PORT
      LAYER M5 ;
        RECT  195.312 0 195.336 0.084 ;
    END
  END c_o[26]
  PIN c_o[27]
    DIRECTION OUTPUT ;
    USE SIGNAL ;
    PORT
      LAYER M5 ;
        RECT  195.456 0 195.48 0.084 ;
    END
  END c_o[27]
  PIN c_o[28]
    DIRECTION OUTPUT ;
    USE SIGNAL ;
    PORT
      LAYER M5 ;
        RECT  195.6 0 195.624 0.084 ;
    END
  END c_o[28]
  PIN c_o[29]
    DIRECTION OUTPUT ;
    USE SIGNAL ;
    PORT
      LAYER M5 ;
        RECT  195.744 0 195.768 0.084 ;
    END
  END c_o[29]
  PIN c_o[2]
    DIRECTION OUTPUT ;
    USE SIGNAL ;
    PORT
      LAYER M5 ;
        RECT  191.856 0 191.88 0.084 ;
    END
  END c_o[2]
  PIN c_o[30]
    DIRECTION OUTPUT ;
    USE SIGNAL ;
    PORT
      LAYER M5 ;
        RECT  195.888 0 195.912 0.084 ;
    END
  END c_o[30]
  PIN c_o[31]
    DIRECTION OUTPUT ;
    USE SIGNAL ;
    PORT
      LAYER M5 ;
        RECT  196.032 0 196.056 0.084 ;
    END
  END c_o[31]
  PIN c_o[32]
    DIRECTION OUTPUT ;
    USE SIGNAL ;
    PORT
      LAYER M5 ;
        RECT  196.176 0 196.2 0.084 ;
    END
  END c_o[32]
  PIN c_o[33]
    DIRECTION OUTPUT ;
    USE SIGNAL ;
    PORT
      LAYER M5 ;
        RECT  196.32 0 196.344 0.084 ;
    END
  END c_o[33]
  PIN c_o[34]
    DIRECTION OUTPUT ;
    USE SIGNAL ;
    PORT
      LAYER M5 ;
        RECT  196.464 0 196.488 0.084 ;
    END
  END c_o[34]
  PIN c_o[35]
    DIRECTION OUTPUT ;
    USE SIGNAL ;
    PORT
      LAYER M5 ;
        RECT  196.608 0 196.632 0.084 ;
    END
  END c_o[35]
  PIN c_o[36]
    DIRECTION OUTPUT ;
    USE SIGNAL ;
    PORT
      LAYER M5 ;
        RECT  196.752 0 196.776 0.084 ;
    END
  END c_o[36]
  PIN c_o[37]
    DIRECTION OUTPUT ;
    USE SIGNAL ;
    PORT
      LAYER M5 ;
        RECT  196.896 0 196.92 0.084 ;
    END
  END c_o[37]
  PIN c_o[38]
    DIRECTION OUTPUT ;
    USE SIGNAL ;
    PORT
      LAYER M5 ;
        RECT  197.04 0 197.064 0.084 ;
    END
  END c_o[38]
  PIN c_o[39]
    DIRECTION OUTPUT ;
    USE SIGNAL ;
    PORT
      LAYER M5 ;
        RECT  197.184 0 197.208 0.084 ;
    END
  END c_o[39]
  PIN c_o[3]
    DIRECTION OUTPUT ;
    USE SIGNAL ;
    PORT
      LAYER M5 ;
        RECT  192 0 192.024 0.084 ;
    END
  END c_o[3]
  PIN c_o[40]
    DIRECTION OUTPUT ;
    USE SIGNAL ;
    PORT
      LAYER M5 ;
        RECT  197.328 0 197.352 0.084 ;
    END
  END c_o[40]
  PIN c_o[41]
    DIRECTION OUTPUT ;
    USE SIGNAL ;
    PORT
      LAYER M5 ;
        RECT  197.472 0 197.496 0.084 ;
    END
  END c_o[41]
  PIN c_o[42]
    DIRECTION OUTPUT ;
    USE SIGNAL ;
    PORT
      LAYER M5 ;
        RECT  197.616 0 197.64 0.084 ;
    END
  END c_o[42]
  PIN c_o[43]
    DIRECTION OUTPUT ;
    USE SIGNAL ;
    PORT
      LAYER M5 ;
        RECT  197.76 0 197.784 0.084 ;
    END
  END c_o[43]
  PIN c_o[44]
    DIRECTION OUTPUT ;
    USE SIGNAL ;
    PORT
      LAYER M5 ;
        RECT  197.904 0 197.928 0.084 ;
    END
  END c_o[44]
  PIN c_o[45]
    DIRECTION OUTPUT ;
    USE SIGNAL ;
    PORT
      LAYER M5 ;
        RECT  198.048 0 198.072 0.084 ;
    END
  END c_o[45]
  PIN c_o[46]
    DIRECTION OUTPUT ;
    USE SIGNAL ;
    PORT
      LAYER M5 ;
        RECT  198.192 0 198.216 0.084 ;
    END
  END c_o[46]
  PIN c_o[47]
    DIRECTION OUTPUT ;
    USE SIGNAL ;
    PORT
      LAYER M5 ;
        RECT  198.336 0 198.36 0.084 ;
    END
  END c_o[47]
  PIN c_o[48]
    DIRECTION OUTPUT ;
    USE SIGNAL ;
    PORT
      LAYER M5 ;
        RECT  198.48 0 198.504 0.084 ;
    END
  END c_o[48]
  PIN c_o[49]
    DIRECTION OUTPUT ;
    USE SIGNAL ;
    PORT
      LAYER M5 ;
        RECT  198.624 0 198.648 0.084 ;
    END
  END c_o[49]
  PIN c_o[4]
    DIRECTION OUTPUT ;
    USE SIGNAL ;
    PORT
      LAYER M5 ;
        RECT  192.144 0 192.168 0.084 ;
    END
  END c_o[4]
  PIN c_o[50]
    DIRECTION OUTPUT ;
    USE SIGNAL ;
    PORT
      LAYER M5 ;
        RECT  198.768 0 198.792 0.084 ;
    END
  END c_o[50]
  PIN c_o[51]
    DIRECTION OUTPUT ;
    USE SIGNAL ;
    PORT
      LAYER M5 ;
        RECT  198.912 0 198.936 0.084 ;
    END
  END c_o[51]
  PIN c_o[52]
    DIRECTION OUTPUT ;
    USE SIGNAL ;
    PORT
      LAYER M5 ;
        RECT  199.056 0 199.08 0.084 ;
    END
  END c_o[52]
  PIN c_o[53]
    DIRECTION OUTPUT ;
    USE SIGNAL ;
    PORT
      LAYER M5 ;
        RECT  199.2 0 199.224 0.084 ;
    END
  END c_o[53]
  PIN c_o[54]
    DIRECTION OUTPUT ;
    USE SIGNAL ;
    PORT
      LAYER M5 ;
        RECT  199.344 0 199.368 0.084 ;
    END
  END c_o[54]
  PIN c_o[55]
    DIRECTION OUTPUT ;
    USE SIGNAL ;
    PORT
      LAYER M5 ;
        RECT  199.488 0 199.512 0.084 ;
    END
  END c_o[55]
  PIN c_o[56]
    DIRECTION OUTPUT ;
    USE SIGNAL ;
    PORT
      LAYER M5 ;
        RECT  199.632 0 199.656 0.084 ;
    END
  END c_o[56]
  PIN c_o[57]
    DIRECTION OUTPUT ;
    USE SIGNAL ;
    PORT
      LAYER M5 ;
        RECT  199.776 0 199.8 0.084 ;
    END
  END c_o[57]
  PIN c_o[58]
    DIRECTION OUTPUT ;
    USE SIGNAL ;
    PORT
      LAYER M5 ;
        RECT  199.92 0 199.944 0.084 ;
    END
  END c_o[58]
  PIN c_o[59]
    DIRECTION OUTPUT ;
    USE SIGNAL ;
    PORT
      LAYER M5 ;
        RECT  200.064 0 200.088 0.084 ;
    END
  END c_o[59]
  PIN c_o[5]
    DIRECTION OUTPUT ;
    USE SIGNAL ;
    PORT
      LAYER M5 ;
        RECT  192.288 0 192.312 0.084 ;
    END
  END c_o[5]
  PIN c_o[60]
    DIRECTION OUTPUT ;
    USE SIGNAL ;
    PORT
      LAYER M5 ;
        RECT  200.208 0 200.232 0.084 ;
    END
  END c_o[60]
  PIN c_o[61]
    DIRECTION OUTPUT ;
    USE SIGNAL ;
    PORT
      LAYER M5 ;
        RECT  200.352 0 200.376 0.084 ;
    END
  END c_o[61]
  PIN c_o[62]
    DIRECTION OUTPUT ;
    USE SIGNAL ;
    PORT
      LAYER M5 ;
        RECT  200.496 0 200.52 0.084 ;
    END
  END c_o[62]
  PIN c_o[63]
    DIRECTION OUTPUT ;
    USE SIGNAL ;
    PORT
      LAYER M5 ;
        RECT  200.64 0 200.664 0.084 ;
    END
  END c_o[63]
  PIN c_o[64]
    DIRECTION OUTPUT ;
    USE SIGNAL ;
    PORT
      LAYER M5 ;
        RECT  200.784 0 200.808 0.084 ;
    END
  END c_o[64]
  PIN c_o[65]
    DIRECTION OUTPUT ;
    USE SIGNAL ;
    PORT
      LAYER M5 ;
        RECT  200.928 0 200.952 0.084 ;
    END
  END c_o[65]
  PIN c_o[66]
    DIRECTION OUTPUT ;
    USE SIGNAL ;
    PORT
      LAYER M5 ;
        RECT  201.072 0 201.096 0.084 ;
    END
  END c_o[66]
  PIN c_o[67]
    DIRECTION OUTPUT ;
    USE SIGNAL ;
    PORT
      LAYER M5 ;
        RECT  201.216 0 201.24 0.084 ;
    END
  END c_o[67]
  PIN c_o[68]
    DIRECTION OUTPUT ;
    USE SIGNAL ;
    PORT
      LAYER M5 ;
        RECT  201.36 0 201.384 0.084 ;
    END
  END c_o[68]
  PIN c_o[69]
    DIRECTION OUTPUT ;
    USE SIGNAL ;
    PORT
      LAYER M5 ;
        RECT  201.504 0 201.528 0.084 ;
    END
  END c_o[69]
  PIN c_o[6]
    DIRECTION OUTPUT ;
    USE SIGNAL ;
    PORT
      LAYER M5 ;
        RECT  192.432 0 192.456 0.084 ;
    END
  END c_o[6]
  PIN c_o[70]
    DIRECTION OUTPUT ;
    USE SIGNAL ;
    PORT
      LAYER M5 ;
        RECT  201.648 0 201.672 0.084 ;
    END
  END c_o[70]
  PIN c_o[71]
    DIRECTION OUTPUT ;
    USE SIGNAL ;
    PORT
      LAYER M5 ;
        RECT  201.792 0 201.816 0.084 ;
    END
  END c_o[71]
  PIN c_o[72]
    DIRECTION OUTPUT ;
    USE SIGNAL ;
    PORT
      LAYER M5 ;
        RECT  201.936 0 201.96 0.084 ;
    END
  END c_o[72]
  PIN c_o[73]
    DIRECTION OUTPUT ;
    USE SIGNAL ;
    PORT
      LAYER M5 ;
        RECT  202.08 0 202.104 0.084 ;
    END
  END c_o[73]
  PIN c_o[74]
    DIRECTION OUTPUT ;
    USE SIGNAL ;
    PORT
      LAYER M5 ;
        RECT  202.224 0 202.248 0.084 ;
    END
  END c_o[74]
  PIN c_o[75]
    DIRECTION OUTPUT ;
    USE SIGNAL ;
    PORT
      LAYER M5 ;
        RECT  202.368 0 202.392 0.084 ;
    END
  END c_o[75]
  PIN c_o[76]
    DIRECTION OUTPUT ;
    USE SIGNAL ;
    PORT
      LAYER M5 ;
        RECT  202.512 0 202.536 0.084 ;
    END
  END c_o[76]
  PIN c_o[77]
    DIRECTION OUTPUT ;
    USE SIGNAL ;
    PORT
      LAYER M5 ;
        RECT  202.656 0 202.68 0.084 ;
    END
  END c_o[77]
  PIN c_o[78]
    DIRECTION OUTPUT ;
    USE SIGNAL ;
    PORT
      LAYER M5 ;
        RECT  202.8 0 202.824 0.084 ;
    END
  END c_o[78]
  PIN c_o[79]
    DIRECTION OUTPUT ;
    USE SIGNAL ;
    PORT
      LAYER M5 ;
        RECT  202.944 0 202.968 0.084 ;
    END
  END c_o[79]
  PIN c_o[7]
    DIRECTION OUTPUT ;
    USE SIGNAL ;
    PORT
      LAYER M5 ;
        RECT  192.576 0 192.6 0.084 ;
    END
  END c_o[7]
  PIN c_o[80]
    DIRECTION OUTPUT ;
    USE SIGNAL ;
    PORT
      LAYER M5 ;
        RECT  203.088 0 203.112 0.084 ;
    END
  END c_o[80]
  PIN c_o[81]
    DIRECTION OUTPUT ;
    USE SIGNAL ;
    PORT
      LAYER M5 ;
        RECT  203.232 0 203.256 0.084 ;
    END
  END c_o[81]
  PIN c_o[82]
    DIRECTION OUTPUT ;
    USE SIGNAL ;
    PORT
      LAYER M5 ;
        RECT  203.376 0 203.4 0.084 ;
    END
  END c_o[82]
  PIN c_o[83]
    DIRECTION OUTPUT ;
    USE SIGNAL ;
    PORT
      LAYER M5 ;
        RECT  203.52 0 203.544 0.084 ;
    END
  END c_o[83]
  PIN c_o[84]
    DIRECTION OUTPUT ;
    USE SIGNAL ;
    PORT
      LAYER M5 ;
        RECT  203.664 0 203.688 0.084 ;
    END
  END c_o[84]
  PIN c_o[85]
    DIRECTION OUTPUT ;
    USE SIGNAL ;
    PORT
      LAYER M5 ;
        RECT  203.808 0 203.832 0.084 ;
    END
  END c_o[85]
  PIN c_o[86]
    DIRECTION OUTPUT ;
    USE SIGNAL ;
    PORT
      LAYER M5 ;
        RECT  203.952 0 203.976 0.084 ;
    END
  END c_o[86]
  PIN c_o[87]
    DIRECTION OUTPUT ;
    USE SIGNAL ;
    PORT
      LAYER M5 ;
        RECT  204.096 0 204.12 0.084 ;
    END
  END c_o[87]
  PIN c_o[88]
    DIRECTION OUTPUT ;
    USE SIGNAL ;
    PORT
      LAYER M5 ;
        RECT  204.24 0 204.264 0.084 ;
    END
  END c_o[88]
  PIN c_o[89]
    DIRECTION OUTPUT ;
    USE SIGNAL ;
    PORT
      LAYER M5 ;
        RECT  204.384 0 204.408 0.084 ;
    END
  END c_o[89]
  PIN c_o[8]
    DIRECTION OUTPUT ;
    USE SIGNAL ;
    PORT
      LAYER M5 ;
        RECT  192.72 0 192.744 0.084 ;
    END
  END c_o[8]
  PIN c_o[90]
    DIRECTION OUTPUT ;
    USE SIGNAL ;
    PORT
      LAYER M5 ;
        RECT  204.528 0 204.552 0.084 ;
    END
  END c_o[90]
  PIN c_o[91]
    DIRECTION OUTPUT ;
    USE SIGNAL ;
    PORT
      LAYER M5 ;
        RECT  204.672 0 204.696 0.084 ;
    END
  END c_o[91]
  PIN c_o[92]
    DIRECTION OUTPUT ;
    USE SIGNAL ;
    PORT
      LAYER M5 ;
        RECT  204.816 0 204.84 0.084 ;
    END
  END c_o[92]
  PIN c_o[93]
    DIRECTION OUTPUT ;
    USE SIGNAL ;
    PORT
      LAYER M5 ;
        RECT  204.96 0 204.984 0.084 ;
    END
  END c_o[93]
  PIN c_o[94]
    DIRECTION OUTPUT ;
    USE SIGNAL ;
    PORT
      LAYER M5 ;
        RECT  205.104 0 205.128 0.084 ;
    END
  END c_o[94]
  PIN c_o[95]
    DIRECTION OUTPUT ;
    USE SIGNAL ;
    PORT
      LAYER M5 ;
        RECT  205.248 0 205.272 0.084 ;
    END
  END c_o[95]
  PIN c_o[96]
    DIRECTION OUTPUT ;
    USE SIGNAL ;
    PORT
      LAYER M5 ;
        RECT  205.392 0 205.416 0.084 ;
    END
  END c_o[96]
  PIN c_o[97]
    DIRECTION OUTPUT ;
    USE SIGNAL ;
    PORT
      LAYER M5 ;
        RECT  205.536 0 205.56 0.084 ;
    END
  END c_o[97]
  PIN c_o[98]
    DIRECTION OUTPUT ;
    USE SIGNAL ;
    PORT
      LAYER M5 ;
        RECT  205.68 0 205.704 0.084 ;
    END
  END c_o[98]
  PIN c_o[99]
    DIRECTION OUTPUT ;
    USE SIGNAL ;
    PORT
      LAYER M5 ;
        RECT  205.824 0 205.848 0.084 ;
    END
  END c_o[99]
  PIN c_o[9]
    DIRECTION OUTPUT ;
    USE SIGNAL ;
    PORT
      LAYER M5 ;
        RECT  192.864 0 192.888 0.084 ;
    END
  END c_o[9]
  PIN clk
    DIRECTION INPUT ;
    USE SIGNAL ;
    PORT
      LAYER M5 ;
        RECT  223.104 0 223.128 0.084 ;
    END
  END clk
  PIN rst_n
    DIRECTION INPUT ;
    USE SIGNAL ;
    PORT
      LAYER M5 ;
        RECT  191.424 0 191.448 0.084 ;
    END
  END rst_n
  PIN VSS
    DIRECTION INOUT ;
    USE GROUND ;
    PORT
      LAYER M5 ;
        RECT  408.084 4.297 408.204 263.543 ;
        RECT  403.764 4.297 403.884 263.543 ;
        RECT  399.444 4.297 399.564 263.543 ;
        RECT  395.124 4.297 395.244 263.543 ;
        RECT  390.804 4.297 390.924 263.543 ;
        RECT  386.484 4.297 386.604 263.543 ;
        RECT  382.164 4.297 382.284 263.543 ;
        RECT  377.844 4.297 377.964 263.543 ;
        RECT  373.524 4.297 373.644 263.543 ;
        RECT  369.204 4.297 369.324 263.543 ;
        RECT  364.884 4.297 365.004 263.543 ;
        RECT  360.564 4.297 360.684 263.543 ;
        RECT  356.244 4.297 356.364 263.543 ;
        RECT  351.924 4.297 352.044 263.543 ;
        RECT  347.604 4.297 347.724 263.543 ;
        RECT  343.284 4.297 343.404 263.543 ;
        RECT  338.964 4.297 339.084 263.543 ;
        RECT  334.644 4.297 334.764 263.543 ;
        RECT  330.324 4.297 330.444 263.543 ;
        RECT  326.004 4.297 326.124 263.543 ;
        RECT  321.684 4.297 321.804 263.543 ;
        RECT  317.364 4.297 317.484 263.543 ;
        RECT  313.044 4.297 313.164 263.543 ;
        RECT  308.724 4.297 308.844 263.543 ;
        RECT  304.404 4.297 304.524 263.543 ;
        RECT  300.084 4.297 300.204 263.543 ;
        RECT  295.764 4.297 295.884 263.543 ;
        RECT  291.444 4.297 291.564 263.543 ;
        RECT  287.124 4.297 287.244 263.543 ;
        RECT  282.804 4.297 282.924 263.543 ;
        RECT  278.484 4.297 278.604 263.543 ;
        RECT  274.164 4.297 274.284 263.543 ;
        RECT  269.844 4.297 269.964 263.543 ;
        RECT  265.524 4.297 265.644 263.543 ;
        RECT  261.204 4.297 261.324 263.543 ;
        RECT  256.884 4.297 257.004 263.543 ;
        RECT  252.564 4.297 252.684 263.543 ;
        RECT  248.244 4.297 248.364 263.543 ;
        RECT  243.924 4.297 244.044 263.543 ;
        RECT  239.604 4.297 239.724 263.543 ;
        RECT  235.284 4.297 235.404 263.543 ;
        RECT  230.964 4.297 231.084 263.543 ;
        RECT  226.644 4.297 226.764 263.543 ;
        RECT  222.324 4.297 222.444 263.543 ;
        RECT  218.004 4.297 218.124 263.543 ;
        RECT  213.684 4.297 213.804 263.543 ;
        RECT  209.364 4.297 209.484 263.543 ;
        RECT  205.044 4.297 205.164 263.543 ;
        RECT  200.724 4.297 200.844 263.543 ;
        RECT  196.404 4.297 196.524 263.543 ;
        RECT  192.084 4.297 192.204 263.543 ;
        RECT  187.764 4.297 187.884 263.543 ;
        RECT  183.444 4.297 183.564 263.543 ;
        RECT  179.124 4.297 179.244 263.543 ;
        RECT  174.804 4.297 174.924 263.543 ;
        RECT  170.484 4.297 170.604 263.543 ;
        RECT  166.164 4.297 166.284 263.543 ;
        RECT  161.844 4.297 161.964 263.543 ;
        RECT  157.524 4.297 157.644 263.543 ;
        RECT  153.204 4.297 153.324 263.543 ;
        RECT  148.884 4.297 149.004 263.543 ;
        RECT  144.564 4.297 144.684 263.543 ;
        RECT  140.244 4.297 140.364 263.543 ;
        RECT  135.924 4.297 136.044 263.543 ;
        RECT  131.604 4.297 131.724 263.543 ;
        RECT  127.284 4.297 127.404 263.543 ;
        RECT  122.964 4.297 123.084 263.543 ;
        RECT  118.644 4.297 118.764 263.543 ;
        RECT  114.324 4.297 114.444 263.543 ;
        RECT  110.004 4.297 110.124 263.543 ;
        RECT  105.684 4.297 105.804 263.543 ;
        RECT  101.364 4.297 101.484 263.543 ;
        RECT  97.044 4.297 97.164 263.543 ;
        RECT  92.724 4.297 92.844 263.543 ;
        RECT  88.404 4.297 88.524 263.543 ;
        RECT  84.084 4.297 84.204 263.543 ;
        RECT  79.764 4.297 79.884 263.543 ;
        RECT  75.444 4.297 75.564 263.543 ;
        RECT  71.124 4.297 71.244 263.543 ;
        RECT  66.804 4.297 66.924 263.543 ;
        RECT  62.484 4.297 62.604 263.543 ;
        RECT  58.164 4.297 58.284 263.543 ;
        RECT  53.844 4.297 53.964 263.543 ;
        RECT  49.524 4.297 49.644 263.543 ;
        RECT  45.204 4.297 45.324 263.543 ;
        RECT  40.884 4.297 41.004 263.543 ;
        RECT  36.564 4.297 36.684 263.543 ;
        RECT  32.244 4.297 32.364 263.543 ;
        RECT  27.924 4.297 28.044 263.543 ;
        RECT  23.604 4.297 23.724 263.543 ;
        RECT  19.284 4.297 19.404 263.543 ;
        RECT  14.964 4.297 15.084 263.543 ;
        RECT  10.644 4.297 10.764 263.543 ;
        RECT  6.324 4.297 6.444 263.543 ;
    END
  END VSS
  PIN VDD
    DIRECTION INOUT ;
    USE POWER ;
    PORT
      LAYER M5 ;
        RECT  408.276 4.311 408.396 263.529 ;
        RECT  403.956 4.311 404.076 263.529 ;
        RECT  399.636 4.311 399.756 263.529 ;
        RECT  395.316 4.311 395.436 263.529 ;
        RECT  390.996 4.311 391.116 263.529 ;
        RECT  386.676 4.311 386.796 263.529 ;
        RECT  382.356 4.311 382.476 263.529 ;
        RECT  378.036 4.311 378.156 263.529 ;
        RECT  373.716 4.311 373.836 263.529 ;
        RECT  369.396 4.311 369.516 263.529 ;
        RECT  365.076 4.311 365.196 263.529 ;
        RECT  360.756 4.311 360.876 263.529 ;
        RECT  356.436 4.311 356.556 263.529 ;
        RECT  352.116 4.311 352.236 263.529 ;
        RECT  347.796 4.311 347.916 263.529 ;
        RECT  343.476 4.311 343.596 263.529 ;
        RECT  339.156 4.311 339.276 263.529 ;
        RECT  334.836 4.311 334.956 263.529 ;
        RECT  330.516 4.311 330.636 263.529 ;
        RECT  326.196 4.311 326.316 263.529 ;
        RECT  321.876 4.311 321.996 263.529 ;
        RECT  317.556 4.311 317.676 263.529 ;
        RECT  313.236 4.311 313.356 263.529 ;
        RECT  308.916 4.311 309.036 263.529 ;
        RECT  304.596 4.311 304.716 263.529 ;
        RECT  300.276 4.311 300.396 263.529 ;
        RECT  295.956 4.311 296.076 263.529 ;
        RECT  291.636 4.311 291.756 263.529 ;
        RECT  287.316 4.311 287.436 263.529 ;
        RECT  282.996 4.311 283.116 263.529 ;
        RECT  278.676 4.311 278.796 263.529 ;
        RECT  274.356 4.311 274.476 263.529 ;
        RECT  270.036 4.311 270.156 263.529 ;
        RECT  265.716 4.311 265.836 263.529 ;
        RECT  261.396 4.311 261.516 263.529 ;
        RECT  257.076 4.311 257.196 263.529 ;
        RECT  252.756 4.311 252.876 263.529 ;
        RECT  248.436 4.311 248.556 263.529 ;
        RECT  244.116 4.311 244.236 263.529 ;
        RECT  239.796 4.311 239.916 263.529 ;
        RECT  235.476 4.311 235.596 263.529 ;
        RECT  231.156 4.311 231.276 263.529 ;
        RECT  226.836 4.311 226.956 263.529 ;
        RECT  222.516 4.311 222.636 263.529 ;
        RECT  218.196 4.311 218.316 263.529 ;
        RECT  213.876 4.311 213.996 263.529 ;
        RECT  209.556 4.311 209.676 263.529 ;
        RECT  205.236 4.311 205.356 263.529 ;
        RECT  200.916 4.311 201.036 263.529 ;
        RECT  196.596 4.311 196.716 263.529 ;
        RECT  192.276 4.311 192.396 263.529 ;
        RECT  187.956 4.311 188.076 263.529 ;
        RECT  183.636 4.311 183.756 263.529 ;
        RECT  179.316 4.311 179.436 263.529 ;
        RECT  174.996 4.311 175.116 263.529 ;
        RECT  170.676 4.311 170.796 263.529 ;
        RECT  166.356 4.311 166.476 263.529 ;
        RECT  162.036 4.311 162.156 263.529 ;
        RECT  157.716 4.311 157.836 263.529 ;
        RECT  153.396 4.311 153.516 263.529 ;
        RECT  149.076 4.311 149.196 263.529 ;
        RECT  144.756 4.311 144.876 263.529 ;
        RECT  140.436 4.311 140.556 263.529 ;
        RECT  136.116 4.311 136.236 263.529 ;
        RECT  131.796 4.311 131.916 263.529 ;
        RECT  127.476 4.311 127.596 263.529 ;
        RECT  123.156 4.311 123.276 263.529 ;
        RECT  118.836 4.311 118.956 263.529 ;
        RECT  114.516 4.311 114.636 263.529 ;
        RECT  110.196 4.311 110.316 263.529 ;
        RECT  105.876 4.311 105.996 263.529 ;
        RECT  101.556 4.311 101.676 263.529 ;
        RECT  97.236 4.311 97.356 263.529 ;
        RECT  92.916 4.311 93.036 263.529 ;
        RECT  88.596 4.311 88.716 263.529 ;
        RECT  84.276 4.311 84.396 263.529 ;
        RECT  79.956 4.311 80.076 263.529 ;
        RECT  75.636 4.311 75.756 263.529 ;
        RECT  71.316 4.311 71.436 263.529 ;
        RECT  66.996 4.311 67.116 263.529 ;
        RECT  62.676 4.311 62.796 263.529 ;
        RECT  58.356 4.311 58.476 263.529 ;
        RECT  54.036 4.311 54.156 263.529 ;
        RECT  49.716 4.311 49.836 263.529 ;
        RECT  45.396 4.311 45.516 263.529 ;
        RECT  41.076 4.311 41.196 263.529 ;
        RECT  36.756 4.311 36.876 263.529 ;
        RECT  32.436 4.311 32.556 263.529 ;
        RECT  28.116 4.311 28.236 263.529 ;
        RECT  23.796 4.311 23.916 263.529 ;
        RECT  19.476 4.311 19.596 263.529 ;
        RECT  15.156 4.311 15.276 263.529 ;
        RECT  10.836 4.311 10.956 263.529 ;
        RECT  6.516 4.311 6.636 263.529 ;
    END
  END VDD
  OBS
    LAYER LVTN ;
     RECT  0 0 410.4 267.84 ;
    LAYER LVTP ;
     RECT  0 0 410.4 267.84 ;
    LAYER RVTN ;
     RECT  0 0 410.4 267.84 ;
    LAYER RVTP ;
     RECT  0 0 410.4 267.84 ;
    LAYER M1 ;
     RECT  0 0 410.4 267.84 ;
    LAYER M2 ;
     RECT  0 0 410.4 267.84 ;
    LAYER M3 ;
     RECT  0 0 410.4 267.84 ;
    LAYER M4 ;
     RECT  0 0 410.4 267.84 ;
    LAYER M5 ;
     RECT  0 0 410.4 267.84 ;
  END
END qfd_qc_su_lane_w_l1
END LIBRARY
